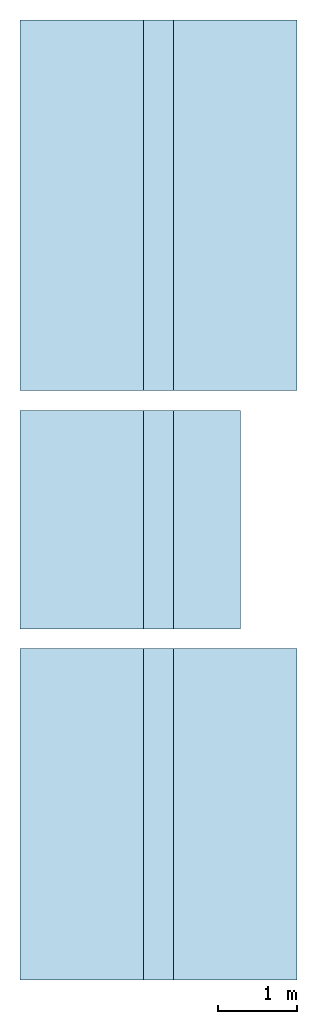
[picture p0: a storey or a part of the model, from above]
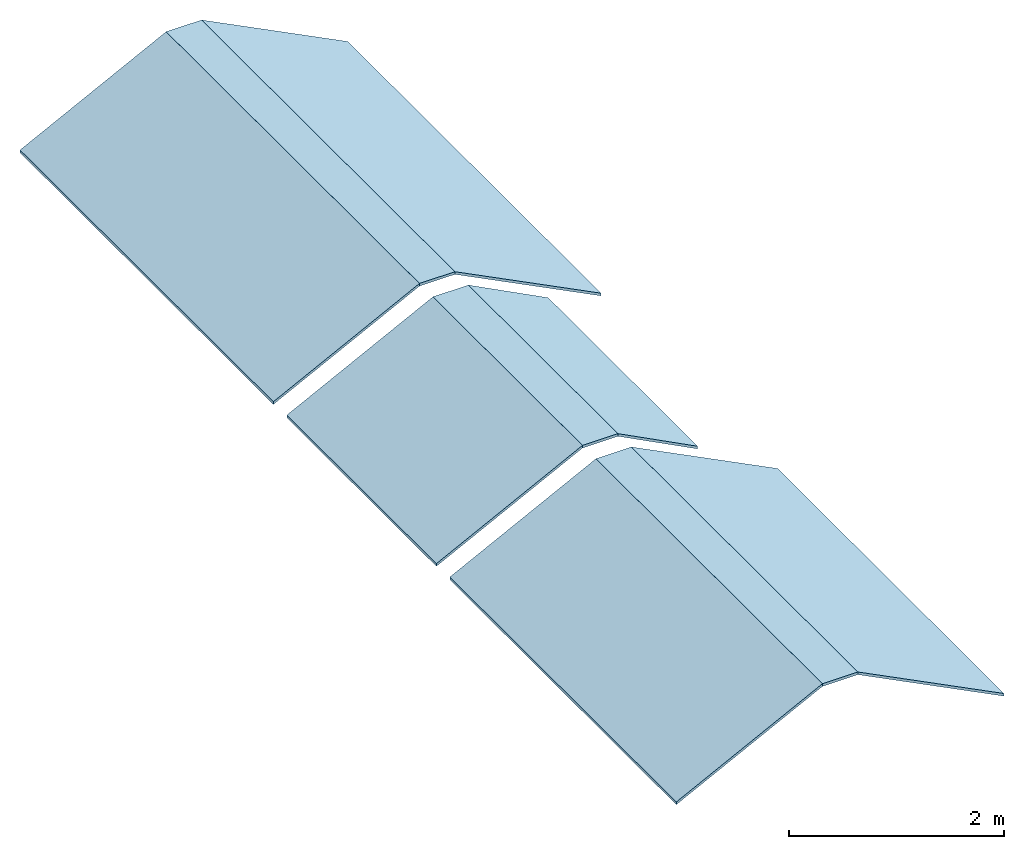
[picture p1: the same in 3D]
Properties of the parts of a building model (IFC2X3), part 1 of 5

# File
Description: ViewDefinition [CoordinationView_V2.0, QuantityTakeOffAddOnView], RevitIdentifiers [ContentGUID: d7be6c1a-651b-40f5-b81f-00204cea7fad, VersionGUID: a0f5081a-c94c-4963-9edc-757abe7cdd60, NumberOfSaves: 85], CoordinateReference [CoordinateBase: Gemeinsam genutzte Koordinaten, ProjectSite: Intern]
File name: Weber Haus.ifc
Time: 2025-12-15T00:05:59+01:00
Written by: ODA SDAI 24.12
Made in: Autodesk Revit 25.4.30.30 (DEU) - IFC 25.4.30.30

# IfcProject, 00-00
LongName: Scan2BIM - Beispiel Datei; Phase: Projekt Status

# IfcSite, Default
RefLatitude: 48, 8, 15, 359802; RefLongitude: 11, 34, 47, 783432; RefElevation: 0 m
Andere - Auftraggeber: Bauherr; Kategorie: Projektinformationen; Projektadresse: Projektadresse; Projektausgabedatum: Projekt Datum; Projektname: Scan2BIM - Beispiel Datei; Projektnummer: 00-00; Projektstatus: Projekt Status; Verfasser eMail: bjarne.weber@flyrender.de; Verfasser Firma 1: FlyRender; Verfasser PLZ Ort: 63928 Eichenbühl; Verfasser Strasse: Im Scheibling 19; Verfasser Telefon: +49 152 09980161; Verfasser URL: www.flyrender.de
Text - Bauherr: Dr. Thomas Weber; Baustellenort: Eichenbühl; Baustellenstraße: Im Scheibling 19; Einlagezahl: 123-45; Gerichtsbezirk: GERICHTSBEZIRK; Grundstücksnummer: GR; Katastralgemeinde: KG; Kundenadresse: KUNDENSTRASSE 1; Kundenort: KUNDENORT; Kundentelefon: 0000-00000-1; Kundenzusatz: KUNDENZUSATZ

# IfcBuilding
Pset_BuildingCommon - NumberOfStoreys: 4
Andere - Auftraggeber: Bauherr; Kategorie: Projektinformationen; Projektadresse: Projektadresse; Projektausgabedatum: Projekt Datum; Projektname: Scan2BIM - Beispiel Datei; Projektnummer: 00-00; Projektstatus: Projekt Status; Verfasser eMail: bjarne.weber@flyrender.de; Verfasser Firma 1: FlyRender; Verfasser PLZ Ort: 63928 Eichenbühl; Verfasser Strasse: Im Scheibling 19; Verfasser Telefon: +49 152 09980161; Verfasser URL: www.flyrender.de
Text - Bauherr: Dr. Thomas Weber; Baustellenort: Eichenbühl; Baustellenstraße: Im Scheibling 19; Einlagezahl: 123-45; Gerichtsbezirk: GERICHTSBEZIRK; Grundstücksnummer: GR; Katastralgemeinde: KG; Kundenadresse: KUNDENSTRASSE 1; Kundenort: KUNDENORT; Kundentelefon: 0000-00000-1; Kundenzusatz: KUNDENZUSATZ

# IfcBuildingStorey: Ebene:Ebene 2 (4)
Pset_AirSideSystemInformation - sets with these values: 2
00_EBENENLISTE - Tragwerk: no; Typ: Ebene 2; Gebäudegeschoss: yes
Andere - Familie: Ebene; Familie und Typ: Ebene: Ebene 2; Kategorie: Ebenen; Typ: Ebene 2; Typ-ID: 2017674
ID-Daten - Tragwerk: no; Gebäudegeschoss: yes
Andere(Typ) - Kategorie: Ebenen; Familienname: Ebene
Abhängigkeiten(Typ) - Basishöhe: Projekt-Basispunkt
Grafiken(Typ) - Farbe: 6579300; Linienmuster: (Referenzebene); Linienstärke: 2; Symbol: Beschriftung Ebene Oberkante : Rohbau; Symbol bei Ende 1 Standard: no; Symbol bei Ende 2 Standard: yes
ID-Daten(Typ) - Typname: Ebene 2
Name | LongName = Pset_AirSideSystemInformation, Name = 00_EBENENLISTE, Name = ID-Daten, Name | Elevation (m) = Ansicht (m) = Höhe (m) | Höhe für Berechnung (m)
Untergeschoss | Untergeschoss | 0 | 1 | Daten - FM Geschoss: EG
Erdgeschoss | Erdgeschoss | 2.6 | 1 | Daten - FM Geschoss: OG 1
1. Obergeschoss | 1. Obergeschoss | 5.4 | 0
First OK | First OK | 9.15 | 0

# IfcSpace: Abseite 1 18:2833431, 18
In: 1. Obergeschoss
LongName: Abseite 1; InteriorOrExteriorSpace: INTERNAL
Pset_AirSideSystemInformation - Name: Abseite 1; sets with these values: 2
Pset_SpaceCommon - Reference: Abseite 1 18
RÄUME - nach Tops und Flächenzuordnung - Nr: 18; Name: Abseite 1; sets with these values: 2
RÄUME - nach Ebene mit Fläche & Umfang - Ebene: 1. Obergeschoss; Nr: 18; Name: Abseite 1
BaseQuantities - GrossFloorArea: 6.17697 m2; NetFloorArea: 6.17697 m2; GrossCeilingArea: 6.17697 m2; Height: 2.4384 m
Andere - Kategorie: Räume; Phasen-ID: 3
Abhängigkeiten - Basisversatz: 0 m; Versatz Oberkante: 26.2467 m; Obergrenze: 1. Obergeschoss; Ebene: 1. Obergeschoss
Bemaßungen - Lichte Höhe: 26.2467 m; Höhe für Berechnung: 0 m; Fläche: 6.17697 m2; Umfang: 12.0429 m; Volumen: 7.10003 m3
Energieanalyse - Angegebene Beleuchtungslast: 0 W; Angegebene Versorgungsleistung: 0 W; Beleuchtungslast basieren auf: Nach Raumtyp; Beleuchtungslasteinheiten: Leistungsdichte; Heizlastwerte: Nach Raumtyp; Luftraum - Beitrag zu Beleuchtung: 0.2; Personenzahl: 0; Tatsächliche Beleuchtungslast: 0 W; Tatsächliche Versorgungsleistung: 0 W; Versorgungslasteinheiten: Leistungsdichte; Versorgungsleistung basieren auf: Nach Raumtyp; Angegebene Beleuchtungslast pro Fläche: 10.7639 kg/s3; Angegebene Versorgungsleistung pro Fläche: 13.9931 kg/s3; Fläche pro Person: 28.5714 m2; Latente Wärmelast pro Person: 58.6142 W; Tatsächliche Beleuchtungslast pro Fläche: 0 kg/s3; Tatsächliche Versorgungsleistung pro Fläche: 0 kg/s3; Wahrnehmbare Wärmelast pro Person: 73.2678 W; Wärmegewinn insgesamt pro Person: 131.882 W
ID-Daten - Name: Abseite 1; Nummer: 18
Phasen - Phase: Phase 01

# IfcSpace: Abseite 2 21:2833440, 21
In: 1. Obergeschoss
LongName: Abseite 2; InteriorOrExteriorSpace: INTERNAL
Pset_AirSideSystemInformation - Name: Abseite 2; sets with these values: 2
Pset_SpaceCommon - Reference: Abseite 2 21
RÄUME - nach Tops und Flächenzuordnung - Nr: 21; Name: Abseite 2; sets with these values: 2
RÄUME - nach Ebene mit Fläche & Umfang - Ebene: 1. Obergeschoss; Nr: 21; Name: Abseite 2
BaseQuantities - GrossFloorArea: 5.77079 m2; NetFloorArea: 5.77079 m2; GrossCeilingArea: 5.77079 m2; Height: 2.4384 m
Andere - Kategorie: Räume; Phasen-ID: 3
Abhängigkeiten - Basisversatz: 0 m; Versatz Oberkante: 26.2467 m; Obergrenze: 1. Obergeschoss; Ebene: 1. Obergeschoss
Bemaßungen - Lichte Höhe: 26.2467 m; Höhe für Berechnung: 0 m; Fläche: 5.77079 m2; Umfang: 11.1615 m; Volumen: 8.92186 m3
Energieanalyse - Angegebene Beleuchtungslast: 0 W; Angegebene Versorgungsleistung: 0 W; Beleuchtungslast basieren auf: Nach Raumtyp; Beleuchtungslasteinheiten: Leistungsdichte; Heizlastwerte: Nach Raumtyp; Luftraum - Beitrag zu Beleuchtung: 0.2; Personenzahl: 0; Tatsächliche Beleuchtungslast: 0 W; Tatsächliche Versorgungsleistung: 0 W; Versorgungslasteinheiten: Leistungsdichte; Versorgungsleistung basieren auf: Nach Raumtyp; Angegebene Beleuchtungslast pro Fläche: 10.7639 kg/s3; Angegebene Versorgungsleistung pro Fläche: 13.9931 kg/s3; Fläche pro Person: 28.5714 m2; Latente Wärmelast pro Person: 58.6142 W; Tatsächliche Beleuchtungslast pro Fläche: 0 kg/s3; Tatsächliche Versorgungsleistung pro Fläche: 0 kg/s3; Wahrnehmbare Wärmelast pro Person: 73.2678 W; Wärmegewinn insgesamt pro Person: 131.882 W
ID-Daten - Name: Abseite 2; Nummer: 21
Phasen - Phase: Phase 01

# IfcSpace: Arbeitszimmer 12:2832122, 12
In: Erdgeschoss
LongName: Arbeitszimmer; InteriorOrExteriorSpace: INTERNAL
Pset_AirSideSystemInformation - Name: Arbeitszimmer; sets with these values: 2
Pset_SpaceCommon - Reference: Arbeitszimmer 12
RÄUME - nach Tops und Flächenzuordnung - Nr: 12; Name: Arbeitszimmer; sets with these values: 2
RÄUME - nach Ebene mit Fläche & Umfang - Ebene: Erdgeschoss; Nr: 12; Name: Arbeitszimmer
BaseQuantities - GrossFloorArea: 14.6935 m2; NetFloorArea: 14.6935 m2; GrossCeilingArea: 14.6935 m2; Height: 2.4384 m
Andere - Kategorie: Räume; Phasen-ID: 3
Abhängigkeiten - Basisversatz: 0 m; Versatz Oberkante: 26.2467 m; Obergrenze: Erdgeschoss; Ebene: Erdgeschoss
Bemaßungen - Lichte Höhe: 26.2467 m; Fläche: 14.6935 m2; Höhe für Berechnung: 1 m; Umfang: 16.0728 m; Volumen: 35.8287 m3
Energieanalyse - Angegebene Beleuchtungslast: 0 W; Angegebene Versorgungsleistung: 0 W; Beleuchtungslast basieren auf: Nach Raumtyp; Beleuchtungslasteinheiten: Leistungsdichte; Heizlastwerte: Nach Raumtyp; Luftraum - Beitrag zu Beleuchtung: 0.2; Personenzahl: 0; Tatsächliche Beleuchtungslast: 0 W; Tatsächliche Versorgungsleistung: 0 W; Versorgungslasteinheiten: Leistungsdichte; Versorgungsleistung basieren auf: Nach Raumtyp; Angegebene Beleuchtungslast pro Fläche: 10.7639 kg/s3; Angegebene Versorgungsleistung pro Fläche: 13.9931 kg/s3; Fläche pro Person: 28.5714 m2; Latente Wärmelast pro Person: 58.6142 W; Tatsächliche Beleuchtungslast pro Fläche: 0 kg/s3; Tatsächliche Versorgungsleistung pro Fläche: 0 kg/s3; Wahrnehmbare Wärmelast pro Person: 73.2678 W; Wärmegewinn insgesamt pro Person: 131.882 W
ID-Daten - Name: Arbeitszimmer; Nummer: 12
Phasen - Phase: Phase 01

# IfcSpace: Bad 16:2832134, 16
In: Erdgeschoss
LongName: Bad; InteriorOrExteriorSpace: INTERNAL
Pset_AirSideSystemInformation - Name: Bad; sets with these values: 2
Pset_SpaceCommon - Reference: Bad 16
RÄUME - nach Tops und Flächenzuordnung - Nr: 16; Name: Bad; sets with these values: 2
RÄUME - nach Ebene mit Fläche & Umfang - Ebene: Erdgeschoss; Nr: 16; Name: Bad
BaseQuantities - GrossFloorArea: 5.03678 m2; NetFloorArea: 5.03678 m2; GrossCeilingArea: 5.03678 m2; Height: 2.4384 m
Andere - Kategorie: Räume; Phasen-ID: 3
Abhängigkeiten - Basisversatz: 0 m; Versatz Oberkante: 26.2467 m; Obergrenze: Erdgeschoss; Ebene: Erdgeschoss
Bemaßungen - Lichte Höhe: 26.2467 m; Fläche: 5.03678 m2; Höhe für Berechnung: 1 m; Umfang: 9.06593 m; Volumen: 12.2817 m3
Energieanalyse - Angegebene Beleuchtungslast: 0 W; Angegebene Versorgungsleistung: 0 W; Beleuchtungslast basieren auf: Nach Raumtyp; Beleuchtungslasteinheiten: Leistungsdichte; Heizlastwerte: Nach Raumtyp; Luftraum - Beitrag zu Beleuchtung: 0.2; Personenzahl: 0; Tatsächliche Beleuchtungslast: 0 W; Tatsächliche Versorgungsleistung: 0 W; Versorgungslasteinheiten: Leistungsdichte; Versorgungsleistung basieren auf: Nach Raumtyp; Angegebene Beleuchtungslast pro Fläche: 10.7639 kg/s3; Angegebene Versorgungsleistung pro Fläche: 13.9931 kg/s3; Fläche pro Person: 28.5714 m2; Latente Wärmelast pro Person: 58.6142 W; Tatsächliche Beleuchtungslast pro Fläche: 0 kg/s3; Tatsächliche Versorgungsleistung pro Fläche: 0 kg/s3; Wahrnehmbare Wärmelast pro Person: 73.2678 W; Wärmegewinn insgesamt pro Person: 131.882 W
ID-Daten - Name: Bad; Nummer: 16
Phasen - Phase: Phase 01

# IfcSpace: Bad 22:2833443, 22
In: 1. Obergeschoss
LongName: Bad; InteriorOrExteriorSpace: INTERNAL
Pset_AirSideSystemInformation - Name: Bad; sets with these values: 2
Pset_SpaceCommon - Reference: Bad 22
RÄUME - nach Tops und Flächenzuordnung - Nr: 22; Name: Bad; sets with these values: 2
RÄUME - nach Ebene mit Fläche & Umfang - Ebene: 1. Obergeschoss; Nr: 22; Name: Bad
BaseQuantities - GrossFloorArea: 5.27 m2; NetFloorArea: 5.27 m2; GrossCeilingArea: 5.27 m2; Height: 2.4384 m
Andere - Kategorie: Räume; Phasen-ID: 3
Abhängigkeiten - Basisversatz: 0 m; Versatz Oberkante: 26.2467 m; Obergrenze: 1. Obergeschoss; Ebene: 1. Obergeschoss
Bemaßungen - Lichte Höhe: 26.2467 m; Höhe für Berechnung: 0 m; Fläche: 5.27 m2; Umfang: 9.9 m; Volumen: 11.2929 m3
Energieanalyse - Angegebene Beleuchtungslast: 0 W; Angegebene Versorgungsleistung: 0 W; Beleuchtungslast basieren auf: Nach Raumtyp; Beleuchtungslasteinheiten: Leistungsdichte; Heizlastwerte: Nach Raumtyp; Luftraum - Beitrag zu Beleuchtung: 0.2; Personenzahl: 0; Tatsächliche Beleuchtungslast: 0 W; Tatsächliche Versorgungsleistung: 0 W; Versorgungslasteinheiten: Leistungsdichte; Versorgungsleistung basieren auf: Nach Raumtyp; Angegebene Beleuchtungslast pro Fläche: 10.7639 kg/s3; Angegebene Versorgungsleistung pro Fläche: 13.9931 kg/s3; Fläche pro Person: 28.5714 m2; Latente Wärmelast pro Person: 58.6142 W; Tatsächliche Beleuchtungslast pro Fläche: 0 kg/s3; Tatsächliche Versorgungsleistung pro Fläche: 0 kg/s3; Wahrnehmbare Wärmelast pro Person: 73.2678 W; Wärmegewinn insgesamt pro Person: 131.882 W
ID-Daten - Name: Bad; Nummer: 22
Phasen - Phase: Phase 01

# IfcSpace: Bad 7:2812981, 7
In: Untergeschoss
LongName: Bad; InteriorOrExteriorSpace: INTERNAL
Pset_AirSideSystemInformation - Name: Bad; sets with these values: 2
Pset_SpaceCommon - Reference: Bad 7
RÄUME - nach Tops und Flächenzuordnung - Nr: 7; Name: Bad; sets with these values: 2
RÄUME - nach Ebene mit Fläche & Umfang - Ebene: Untergeschoss; Nr: 7; Name: Bad
BaseQuantities - GrossFloorArea: 2.45626 m2; NetFloorArea: 2.45626 m2; GrossCeilingArea: 2.45626 m2; Height: 2.4384 m
Andere - Kategorie: Räume; Phasen-ID: 3
Abhängigkeiten - Basisversatz: 0 m; Obergrenze: Untergeschoss; Versatz Oberkante: 26.2467 m; Ebene: Untergeschoss
Bemaßungen - Lichte Höhe: 26.2467 m; Fläche: 2.45626 m2; Höhe für Berechnung: 1 m; Umfang: 6.66593 m; Volumen: 5.77221 m3
Energieanalyse - Angegebene Beleuchtungslast: 0 W; Angegebene Versorgungsleistung: 0 W; Beleuchtungslast basieren auf: Nach Raumtyp; Beleuchtungslasteinheiten: Leistungsdichte; Heizlastwerte: Nach Raumtyp; Luftraum - Beitrag zu Beleuchtung: 0.2; Personenzahl: 0; Tatsächliche Beleuchtungslast: 0 W; Tatsächliche Versorgungsleistung: 0 W; Versorgungslasteinheiten: Leistungsdichte; Versorgungsleistung basieren auf: Nach Raumtyp; Angegebene Beleuchtungslast pro Fläche: 10.7639 kg/s3; Angegebene Versorgungsleistung pro Fläche: 13.9931 kg/s3; Fläche pro Person: 28.5714 m2; Latente Wärmelast pro Person: 58.6142 W; Tatsächliche Beleuchtungslast pro Fläche: 0 kg/s3; Tatsächliche Versorgungsleistung pro Fläche: 0 kg/s3; Wahrnehmbare Wärmelast pro Person: 73.2678 W; Wärmegewinn insgesamt pro Person: 131.882 W
ID-Daten - Name: Bad; Nummer: 7
Phasen - Phase: Phase 01

# IfcSpace: Bibliothek 19:2833434, 19
In: 1. Obergeschoss
LongName: Bibliothek; InteriorOrExteriorSpace: INTERNAL
Pset_AirSideSystemInformation - Name: Bibliothek; sets with these values: 2
Pset_SpaceCommon - Reference: Bibliothek 19
RÄUME - nach Tops und Flächenzuordnung - Nr: 19; Name: Bibliothek; sets with these values: 2
RÄUME - nach Ebene mit Fläche & Umfang - Ebene: 1. Obergeschoss; Nr: 19; Name: Bibliothek
BaseQuantities - GrossFloorArea: 22.1961 m2; NetFloorArea: 22.1961 m2; GrossCeilingArea: 22.1961 m2; Height: 2.4384 m
Andere - Kategorie: Räume; Phasen-ID: 3
Abhängigkeiten - Basisversatz: 0 m; Versatz Oberkante: 26.2467 m; Obergrenze: 1. Obergeschoss; Ebene: 1. Obergeschoss
Bemaßungen - Lichte Höhe: 26.2467 m; Höhe für Berechnung: 0 m; Fläche: 22.1961 m2; Umfang: 26.1712 m; Volumen: 40.4515 m3
Energieanalyse - Angegebene Beleuchtungslast: 0 W; Angegebene Versorgungsleistung: 0 W; Beleuchtungslast basieren auf: Nach Raumtyp; Beleuchtungslasteinheiten: Leistungsdichte; Heizlastwerte: Nach Raumtyp; Luftraum - Beitrag zu Beleuchtung: 0.2; Personenzahl: 0; Tatsächliche Beleuchtungslast: 0 W; Tatsächliche Versorgungsleistung: 0 W; Versorgungslasteinheiten: Leistungsdichte; Versorgungsleistung basieren auf: Nach Raumtyp; Angegebene Beleuchtungslast pro Fläche: 10.7639 kg/s3; Angegebene Versorgungsleistung pro Fläche: 13.9931 kg/s3; Fläche pro Person: 28.5714 m2; Latente Wärmelast pro Person: 58.6142 W; Tatsächliche Beleuchtungslast pro Fläche: 0 kg/s3; Tatsächliche Versorgungsleistung pro Fläche: 0 kg/s3; Wahrnehmbare Wärmelast pro Person: 73.2678 W; Wärmegewinn insgesamt pro Person: 131.882 W
ID-Daten - Name: Bibliothek; Nummer: 19
Phasen - Phase: Phase 01

# IfcSpace: Billiardzimmer 5:2812975, 5
In: Untergeschoss
LongName: Billiardzimmer; InteriorOrExteriorSpace: INTERNAL
Pset_AirSideSystemInformation - Name: Billiardzimmer; sets with these values: 2
Pset_SpaceCommon - Reference: Billiardzimmer 5
RÄUME - nach Tops und Flächenzuordnung - Nr: 5; Name: Billiardzimmer; sets with these values: 2
RÄUME - nach Ebene mit Fläche & Umfang - Ebene: Untergeschoss; Nr: 5; Name: Billiardzimmer
BaseQuantities - GrossFloorArea: 38.6121 m2; NetFloorArea: 38.6121 m2; GrossCeilingArea: 38.6121 m2; Height: 2.4384 m
Andere - Kategorie: Räume; Phasen-ID: 3
Abhängigkeiten - Basisversatz: 0 m; Obergrenze: Untergeschoss; Versatz Oberkante: 26.2467 m; Ebene: Untergeschoss
Bemaßungen - Lichte Höhe: 26.2467 m; Fläche: 38.6121 m2; Höhe für Berechnung: 1 m; Umfang: 28.9258 m; Volumen: 90.7385 m3
Energieanalyse - Angegebene Beleuchtungslast: 0 W; Angegebene Versorgungsleistung: 0 W; Beleuchtungslast basieren auf: Nach Raumtyp; Beleuchtungslasteinheiten: Leistungsdichte; Heizlastwerte: Nach Raumtyp; Luftraum - Beitrag zu Beleuchtung: 0.2; Personenzahl: 0; Tatsächliche Beleuchtungslast: 0 W; Tatsächliche Versorgungsleistung: 0 W; Versorgungslasteinheiten: Leistungsdichte; Versorgungsleistung basieren auf: Nach Raumtyp; Angegebene Beleuchtungslast pro Fläche: 10.7639 kg/s3; Angegebene Versorgungsleistung pro Fläche: 13.9931 kg/s3; Fläche pro Person: 28.5714 m2; Latente Wärmelast pro Person: 58.6142 W; Tatsächliche Beleuchtungslast pro Fläche: 0 kg/s3; Tatsächliche Versorgungsleistung pro Fläche: 0 kg/s3; Wahrnehmbare Wärmelast pro Person: 73.2678 W; Wärmegewinn insgesamt pro Person: 131.882 W
ID-Daten - Name: Billiardzimmer; Nummer: 5
Phasen - Phase: Phase 01

# IfcSpace: Diele 11:2832119, 11
In: Erdgeschoss
LongName: Diele; InteriorOrExteriorSpace: INTERNAL
Pset_AirSideSystemInformation - Name: Diele; sets with these values: 2
Pset_SpaceCommon - Reference: Diele 11
RÄUME - nach Tops und Flächenzuordnung - Nr: 11; Name: Diele; sets with these values: 2
RÄUME - nach Ebene mit Fläche & Umfang - Ebene: Erdgeschoss; Nr: 11; Name: Diele
BaseQuantities - GrossFloorArea: 10.7251 m2; NetFloorArea: 10.7251 m2; GrossCeilingArea: 10.7251 m2; Height: 2.4384 m
Andere - Kategorie: Räume; Phasen-ID: 3
Abhängigkeiten - Basisversatz: 0 m; Versatz Oberkante: 26.2467 m; Obergrenze: Erdgeschoss; Ebene: Erdgeschoss
Bemaßungen - Lichte Höhe: 26.2467 m; Fläche: 10.7251 m2; Höhe für Berechnung: 1 m; Umfang: 13.2759 m; Volumen: 26.0136 m3
Energieanalyse - Angegebene Beleuchtungslast: 0 W; Angegebene Versorgungsleistung: 0 W; Beleuchtungslast basieren auf: Nach Raumtyp; Beleuchtungslasteinheiten: Leistungsdichte; Heizlastwerte: Nach Raumtyp; Luftraum - Beitrag zu Beleuchtung: 0.2; Personenzahl: 0; Tatsächliche Beleuchtungslast: 0 W; Tatsächliche Versorgungsleistung: 0 W; Versorgungslasteinheiten: Leistungsdichte; Versorgungsleistung basieren auf: Nach Raumtyp; Angegebene Beleuchtungslast pro Fläche: 10.7639 kg/s3; Angegebene Versorgungsleistung pro Fläche: 13.9931 kg/s3; Fläche pro Person: 28.5714 m2; Latente Wärmelast pro Person: 58.6142 W; Tatsächliche Beleuchtungslast pro Fläche: 0 kg/s3; Tatsächliche Versorgungsleistung pro Fläche: 0 kg/s3; Wahrnehmbare Wärmelast pro Person: 73.2678 W; Wärmegewinn insgesamt pro Person: 131.882 W
ID-Daten - Name: Diele; Nummer: 11
Phasen - Phase: Phase 01

# IfcSpace: Flur 1 4:2812972, 4
In: Untergeschoss
LongName: Flur 1; InteriorOrExteriorSpace: INTERNAL
Pset_AirSideSystemInformation - Name: Flur 1; sets with these values: 2
Pset_SpaceCommon - Reference: Flur 1 4
RÄUME - nach Tops und Flächenzuordnung - Nr: 4; Name: Flur 1; sets with these values: 2
RÄUME - nach Ebene mit Fläche & Umfang - Ebene: Untergeschoss; Nr: 4; Name: Flur 1
BaseQuantities - GrossFloorArea: 3.8512 m2; NetFloorArea: 3.8512 m2; GrossCeilingArea: 3.8512 m2; Height: 2.4384 m
Andere - Kategorie: Räume; Phasen-ID: 3
Abhängigkeiten - Basisversatz: 0 m; Obergrenze: Untergeschoss; Versatz Oberkante: 26.2467 m; Ebene: Untergeschoss
Bemaßungen - Lichte Höhe: 26.2467 m; Fläche: 3.8512 m2; Höhe für Berechnung: 1 m; Umfang: 9.56 m; Volumen: 9.05032 m3
Energieanalyse - Angegebene Beleuchtungslast: 0 W; Angegebene Versorgungsleistung: 0 W; Beleuchtungslast basieren auf: Nach Raumtyp; Beleuchtungslasteinheiten: Leistungsdichte; Heizlastwerte: Nach Raumtyp; Luftraum - Beitrag zu Beleuchtung: 0.2; Personenzahl: 0; Tatsächliche Beleuchtungslast: 0 W; Tatsächliche Versorgungsleistung: 0 W; Versorgungslasteinheiten: Leistungsdichte; Versorgungsleistung basieren auf: Nach Raumtyp; Angegebene Beleuchtungslast pro Fläche: 10.7639 kg/s3; Angegebene Versorgungsleistung pro Fläche: 13.9931 kg/s3; Fläche pro Person: 28.5714 m2; Latente Wärmelast pro Person: 58.6142 W; Tatsächliche Beleuchtungslast pro Fläche: 0 kg/s3; Tatsächliche Versorgungsleistung pro Fläche: 0 kg/s3; Wahrnehmbare Wärmelast pro Person: 73.2678 W; Wärmegewinn insgesamt pro Person: 131.882 W
ID-Daten - Name: Flur 1; Nummer: 4
Phasen - Phase: Phase 01

# IfcSpace: Flur 15:2832131, 15
In: Erdgeschoss
LongName: Flur; InteriorOrExteriorSpace: INTERNAL
Pset_AirSideSystemInformation - Name: Flur; sets with these values: 2
Pset_SpaceCommon - Reference: Flur 15
RÄUME - nach Tops und Flächenzuordnung - Nr: 15; Name: Flur; sets with these values: 2
RÄUME - nach Ebene mit Fläche & Umfang - Ebene: Erdgeschoss; Nr: 15; Name: Flur
BaseQuantities - GrossFloorArea: 2.09625 m2; NetFloorArea: 2.09625 m2; GrossCeilingArea: 2.09625 m2; Height: 2.4384 m
Andere - Kategorie: Räume; Phasen-ID: 3
Abhängigkeiten - Basisversatz: 0 m; Versatz Oberkante: 26.2467 m; Obergrenze: Erdgeschoss; Ebene: Erdgeschoss
Bemaßungen - Lichte Höhe: 26.2467 m; Fläche: 2.09625 m2; Höhe für Berechnung: 1 m; Umfang: 6.05 m; Volumen: 5.1115 m3
Energieanalyse - Angegebene Beleuchtungslast: 0 W; Angegebene Versorgungsleistung: 0 W; Beleuchtungslast basieren auf: Nach Raumtyp; Beleuchtungslasteinheiten: Leistungsdichte; Heizlastwerte: Nach Raumtyp; Luftraum - Beitrag zu Beleuchtung: 0.2; Personenzahl: 0; Tatsächliche Beleuchtungslast: 0 W; Tatsächliche Versorgungsleistung: 0 W; Versorgungslasteinheiten: Leistungsdichte; Versorgungsleistung basieren auf: Nach Raumtyp; Angegebene Beleuchtungslast pro Fläche: 10.7639 kg/s3; Angegebene Versorgungsleistung pro Fläche: 13.9931 kg/s3; Fläche pro Person: 28.5714 m2; Latente Wärmelast pro Person: 58.6142 W; Tatsächliche Beleuchtungslast pro Fläche: 0 kg/s3; Tatsächliche Versorgungsleistung pro Fläche: 0 kg/s3; Wahrnehmbare Wärmelast pro Person: 73.2678 W; Wärmegewinn insgesamt pro Person: 131.882 W
ID-Daten - Name: Flur; Nummer: 15
Phasen - Phase: Phase 01

# IfcSpace: Flur 2 8:2812984, 8
In: Untergeschoss
LongName: Flur 2; InteriorOrExteriorSpace: INTERNAL
Pset_AirSideSystemInformation - Name: Flur 2; sets with these values: 2
Pset_SpaceCommon - Reference: Flur 2 8
RÄUME - nach Tops und Flächenzuordnung - Nr: 8; Name: Flur 2; sets with these values: 2
RÄUME - nach Ebene mit Fläche & Umfang - Ebene: Untergeschoss; Nr: 8; Name: Flur 2
BaseQuantities - GrossFloorArea: 10.4721 m2; NetFloorArea: 10.4483 m2; GrossCeilingArea: 10.4721 m2; Height: 2.4384 m
Andere - Kategorie: Räume; Phasen-ID: 3
Abhängigkeiten - Basisversatz: 0 m; Obergrenze: Untergeschoss; Versatz Oberkante: 26.2467 m; Ebene: Untergeschoss
Bemaßungen - Lichte Höhe: 26.2467 m; Fläche: 10.4483 m2; Höhe für Berechnung: 1 m; Umfang: 13.8029 m; Volumen: 24.7864 m3
Energieanalyse - Angegebene Beleuchtungslast: 0 W; Angegebene Versorgungsleistung: 0 W; Beleuchtungslast basieren auf: Nach Raumtyp; Beleuchtungslasteinheiten: Leistungsdichte; Heizlastwerte: Nach Raumtyp; Luftraum - Beitrag zu Beleuchtung: 0.2; Personenzahl: 0; Tatsächliche Beleuchtungslast: 0 W; Tatsächliche Versorgungsleistung: 0 W; Versorgungslasteinheiten: Leistungsdichte; Versorgungsleistung basieren auf: Nach Raumtyp; Angegebene Beleuchtungslast pro Fläche: 10.7639 kg/s3; Angegebene Versorgungsleistung pro Fläche: 13.9931 kg/s3; Fläche pro Person: 28.5714 m2; Latente Wärmelast pro Person: 58.6142 W; Tatsächliche Beleuchtungslast pro Fläche: 0 kg/s3; Tatsächliche Versorgungsleistung pro Fläche: 0 kg/s3; Wahrnehmbare Wärmelast pro Person: 73.2678 W; Wärmegewinn insgesamt pro Person: 131.882 W
ID-Daten - Name: Flur 2; Nummer: 8
Phasen - Phase: Phase 01

# IfcSpace: Gästezimmer 1:2812963, 1
In: Untergeschoss
LongName: Gästezimmer; InteriorOrExteriorSpace: INTERNAL
Pset_AirSideSystemInformation - Name: Gästezimmer; sets with these values: 2
Pset_SpaceCommon - Reference: Gästezimmer 1
RÄUME - nach Tops und Flächenzuordnung - Nr: 1; Name: Gästezimmer; sets with these values: 2
RÄUME - nach Ebene mit Fläche & Umfang - Ebene: Untergeschoss; Nr: 1; Name: Gästezimmer
BaseQuantities - GrossFloorArea: 13.3279 m2; NetFloorArea: 13.3279 m2; GrossCeilingArea: 13.3279 m2; Height: 2.4384 m
Andere - Kategorie: Räume; Phasen-ID: 3
Abhängigkeiten - Basisversatz: 0 m; Ebene: Untergeschoss; Obergrenze: Untergeschoss; Versatz Oberkante: 26.2467 m
Bemaßungen - Fläche: 13.3279 m2; Höhe für Berechnung: 1 m; Lichte Höhe: 26.2467 m; Umfang: 14.6341 m; Volumen: 31.3205 m3
Energieanalyse - Angegebene Beleuchtungslast: 0 W; Angegebene Beleuchtungslast pro Fläche: 10.7639 kg/s3; Angegebene Versorgungsleistung: 0 W; Angegebene Versorgungsleistung pro Fläche: 13.9931 kg/s3; Beleuchtungslast basieren auf: Nach Raumtyp; Beleuchtungslasteinheiten: Leistungsdichte; Fläche pro Person: 28.5714 m2; Heizlastwerte: Nach Raumtyp; Latente Wärmelast pro Person: 58.6142 W; Luftraum - Beitrag zu Beleuchtung: 0.2; Personenzahl: 0; Tatsächliche Beleuchtungslast: 0 W; Tatsächliche Beleuchtungslast pro Fläche: 0 kg/s3; Tatsächliche Versorgungsleistung: 0 W; Tatsächliche Versorgungsleistung pro Fläche: 0 kg/s3; Versorgungslasteinheiten: Leistungsdichte; Versorgungsleistung basieren auf: Nach Raumtyp; Wahrnehmbare Wärmelast pro Person: 73.2678 W; Wärmegewinn insgesamt pro Person: 131.882 W
ID-Daten - Name: Gästezimmer; Nummer: 1
Phasen - Phase: Phase 01

# IfcSpace: Kinderzimmer 1 17:2833427, 17
In: 1. Obergeschoss
LongName: Kinderzimmer 1; InteriorOrExteriorSpace: INTERNAL
Pset_AirSideSystemInformation - Name: Kinderzimmer 1; sets with these values: 2
Pset_SpaceCommon - Reference: Kinderzimmer 1 17
RÄUME - nach Tops und Flächenzuordnung - Nr: 17; Name: Kinderzimmer 1; sets with these values: 2
RÄUME - nach Ebene mit Fläche & Umfang - Ebene: 1. Obergeschoss; Nr: 17; Name: Kinderzimmer 1
BaseQuantities - GrossFloorArea: 24.6849 m2; NetFloorArea: 24.6849 m2; GrossCeilingArea: 24.6849 m2; Height: 2.4384 m
Andere - Kategorie: Räume; Phasen-ID: 3
Abhängigkeiten - Basisversatz: 0 m; Versatz Oberkante: 26.2467 m; Ebene: 1. Obergeschoss; Obergrenze: 1. Obergeschoss
Bemaßungen - Lichte Höhe: 26.2467 m; Fläche: 24.6849 m2; Höhe für Berechnung: 0 m; Umfang: 22.5771 m; Volumen: 53.802 m3
Energieanalyse - Angegebene Beleuchtungslast: 0 W; Angegebene Versorgungsleistung: 0 W; Beleuchtungslast basieren auf: Nach Raumtyp; Beleuchtungslasteinheiten: Leistungsdichte; Heizlastwerte: Nach Raumtyp; Luftraum - Beitrag zu Beleuchtung: 0.2; Personenzahl: 0; Tatsächliche Beleuchtungslast: 0 W; Tatsächliche Versorgungsleistung: 0 W; Versorgungslasteinheiten: Leistungsdichte; Versorgungsleistung basieren auf: Nach Raumtyp; Angegebene Beleuchtungslast pro Fläche: 10.7639 kg/s3; Angegebene Versorgungsleistung pro Fläche: 13.9931 kg/s3; Fläche pro Person: 28.5714 m2; Latente Wärmelast pro Person: 58.6142 W; Tatsächliche Beleuchtungslast pro Fläche: 0 kg/s3; Tatsächliche Versorgungsleistung pro Fläche: 0 kg/s3; Wahrnehmbare Wärmelast pro Person: 73.2678 W; Wärmegewinn insgesamt pro Person: 131.882 W
ID-Daten - Name: Kinderzimmer 1; Nummer: 17
Phasen - Phase: Phase 01

# IfcSpace: Kinderzimmer 2 20:2833437, 20
In: 1. Obergeschoss
LongName: Kinderzimmer 2; InteriorOrExteriorSpace: INTERNAL
Pset_AirSideSystemInformation - Name: Kinderzimmer 2; sets with these values: 2
Pset_SpaceCommon - Reference: Kinderzimmer 2 20
RÄUME - nach Tops und Flächenzuordnung - Nr: 20; Name: Kinderzimmer 2; sets with these values: 2
RÄUME - nach Ebene mit Fläche & Umfang - Ebene: 1. Obergeschoss; Nr: 20; Name: Kinderzimmer 2
BaseQuantities - GrossFloorArea: 29.2271 m2; NetFloorArea: 29.2271 m2; GrossCeilingArea: 29.2271 m2; Height: 2.4384 m
Andere - Kategorie: Räume; Phasen-ID: 3
Abhängigkeiten - Basisversatz: 0 m; Versatz Oberkante: 26.2467 m; Obergrenze: 1. Obergeschoss; Ebene: 1. Obergeschoss
Bemaßungen - Lichte Höhe: 26.2467 m; Höhe für Berechnung: 0 m; Fläche: 29.2271 m2; Umfang: 22.3046 m; Volumen: 61.4922 m3
Energieanalyse - Angegebene Beleuchtungslast: 0 W; Angegebene Versorgungsleistung: 0 W; Beleuchtungslast basieren auf: Nach Raumtyp; Beleuchtungslasteinheiten: Leistungsdichte; Heizlastwerte: Nach Raumtyp; Luftraum - Beitrag zu Beleuchtung: 0.2; Personenzahl: 0; Tatsächliche Beleuchtungslast: 0 W; Tatsächliche Versorgungsleistung: 0 W; Versorgungslasteinheiten: Leistungsdichte; Versorgungsleistung basieren auf: Nach Raumtyp; Angegebene Beleuchtungslast pro Fläche: 10.7639 kg/s3; Angegebene Versorgungsleistung pro Fläche: 13.9931 kg/s3; Fläche pro Person: 28.5714 m2; Latente Wärmelast pro Person: 58.6142 W; Tatsächliche Beleuchtungslast pro Fläche: 0 kg/s3; Tatsächliche Versorgungsleistung pro Fläche: 0 kg/s3; Wahrnehmbare Wärmelast pro Person: 73.2678 W; Wärmegewinn insgesamt pro Person: 131.882 W
ID-Daten - Name: Kinderzimmer 2; Nummer: 20
Phasen - Phase: Phase 01

# IfcSpace: Küche 10:2832116, 10
In: Erdgeschoss
LongName: Küche; InteriorOrExteriorSpace: INTERNAL
Pset_AirSideSystemInformation - Name: Küche; sets with these values: 2
Pset_SpaceCommon - Reference: Küche 10
RÄUME - nach Tops und Flächenzuordnung - Nr: 10; Name: Küche; sets with these values: 2
RÄUME - nach Ebene mit Fläche & Umfang - Ebene: Erdgeschoss; Nr: 10; Name: Küche
BaseQuantities - GrossFloorArea: 10.0323 m2; NetFloorArea: 10.0323 m2; GrossCeilingArea: 10.0323 m2; Height: 2.4384 m
Andere - Kategorie: Räume; Phasen-ID: 3
Abhängigkeiten - Basisversatz: 0 m; Versatz Oberkante: 26.2467 m; Obergrenze: Erdgeschoss; Ebene: Erdgeschoss
Bemaßungen - Lichte Höhe: 26.2467 m; Fläche: 10.0323 m2; Höhe für Berechnung: 1 m; Umfang: 13.1859 m; Volumen: 24.4627 m3
Energieanalyse - Angegebene Beleuchtungslast: 0 W; Angegebene Versorgungsleistung: 0 W; Beleuchtungslast basieren auf: Nach Raumtyp; Beleuchtungslasteinheiten: Leistungsdichte; Heizlastwerte: Nach Raumtyp; Luftraum - Beitrag zu Beleuchtung: 0.2; Personenzahl: 0; Tatsächliche Beleuchtungslast: 0 W; Tatsächliche Versorgungsleistung: 0 W; Versorgungslasteinheiten: Leistungsdichte; Versorgungsleistung basieren auf: Nach Raumtyp; Angegebene Beleuchtungslast pro Fläche: 10.7639 kg/s3; Angegebene Versorgungsleistung pro Fläche: 13.9931 kg/s3; Fläche pro Person: 28.5714 m2; Latente Wärmelast pro Person: 58.6142 W; Tatsächliche Beleuchtungslast pro Fläche: 0 kg/s3; Tatsächliche Versorgungsleistung pro Fläche: 0 kg/s3; Wahrnehmbare Wärmelast pro Person: 73.2678 W; Wärmegewinn insgesamt pro Person: 131.882 W
ID-Daten - Name: Küche; Nummer: 10
Phasen - Phase: Phase 01

# IfcSpace: Sauna 3:2812969, 3
In: Untergeschoss
LongName: Sauna; InteriorOrExteriorSpace: INTERNAL
Pset_AirSideSystemInformation - Name: Sauna; sets with these values: 2
Pset_SpaceCommon - Reference: Sauna 3
RÄUME - nach Tops und Flächenzuordnung - Nr: 3; Name: Sauna; sets with these values: 2
RÄUME - nach Ebene mit Fläche & Umfang - Ebene: Untergeschoss; Nr: 3; Name: Sauna
BaseQuantities - GrossFloorArea: 4.86593 m2; NetFloorArea: 4.86593 m2; GrossCeilingArea: 4.86593 m2; Height: 2.4384 m
Andere - Kategorie: Räume; Phasen-ID: 3
Abhängigkeiten - Basisversatz: 0 m; Obergrenze: Untergeschoss; Versatz Oberkante: 26.2467 m; Ebene: Untergeschoss
Bemaßungen - Lichte Höhe: 26.2467 m; Fläche: 4.86593 m2; Höhe für Berechnung: 1 m; Umfang: 8.86593 m; Volumen: 11.4349 m3
Energieanalyse - Angegebene Beleuchtungslast: 0 W; Angegebene Versorgungsleistung: 0 W; Beleuchtungslast basieren auf: Nach Raumtyp; Beleuchtungslasteinheiten: Leistungsdichte; Heizlastwerte: Nach Raumtyp; Luftraum - Beitrag zu Beleuchtung: 0.2; Personenzahl: 0; Tatsächliche Beleuchtungslast: 0 W; Tatsächliche Versorgungsleistung: 0 W; Versorgungslasteinheiten: Leistungsdichte; Versorgungsleistung basieren auf: Nach Raumtyp; Angegebene Beleuchtungslast pro Fläche: 10.7639 kg/s3; Angegebene Versorgungsleistung pro Fläche: 13.9931 kg/s3; Fläche pro Person: 28.5714 m2; Latente Wärmelast pro Person: 58.6142 W; Tatsächliche Beleuchtungslast pro Fläche: 0 kg/s3; Tatsächliche Versorgungsleistung pro Fläche: 0 kg/s3; Wahrnehmbare Wärmelast pro Person: 73.2678 W; Wärmegewinn insgesamt pro Person: 131.882 W
ID-Daten - Name: Sauna; Nummer: 3
Phasen - Phase: Phase 01

# IfcSpace: Schlafzimmer 1 13:2832125, 13
In: Erdgeschoss
LongName: Schlafzimmer 1; InteriorOrExteriorSpace: INTERNAL
Pset_AirSideSystemInformation - Name: Schlafzimmer 1; sets with these values: 2
Pset_SpaceCommon - Reference: Schlafzimmer 1 13
RÄUME - nach Tops und Flächenzuordnung - Nr: 13; Name: Schlafzimmer 1; sets with these values: 2
RÄUME - nach Ebene mit Fläche & Umfang - Ebene: Erdgeschoss; Nr: 13; Name: Schlafzimmer 1
BaseQuantities - GrossFloorArea: 15.977 m2; NetFloorArea: 15.977 m2; GrossCeilingArea: 15.977 m2; Height: 2.4384 m
Andere - Kategorie: Räume; Phasen-ID: 3
Abhängigkeiten - Basisversatz: 0 m; Versatz Oberkante: 26.2467 m; Obergrenze: Erdgeschoss; Ebene: Erdgeschoss
Bemaßungen - Lichte Höhe: 26.2467 m; Fläche: 15.977 m2; Höhe für Berechnung: 1 m; Umfang: 16.4153 m; Volumen: 38.9583 m3
Energieanalyse - Angegebene Beleuchtungslast: 0 W; Angegebene Versorgungsleistung: 0 W; Beleuchtungslast basieren auf: Nach Raumtyp; Beleuchtungslasteinheiten: Leistungsdichte; Heizlastwerte: Nach Raumtyp; Luftraum - Beitrag zu Beleuchtung: 0.2; Personenzahl: 0; Tatsächliche Beleuchtungslast: 0 W; Tatsächliche Versorgungsleistung: 0 W; Versorgungslasteinheiten: Leistungsdichte; Versorgungsleistung basieren auf: Nach Raumtyp; Angegebene Beleuchtungslast pro Fläche: 10.7639 kg/s3; Angegebene Versorgungsleistung pro Fläche: 13.9931 kg/s3; Fläche pro Person: 28.5714 m2; Latente Wärmelast pro Person: 58.6142 W; Tatsächliche Beleuchtungslast pro Fläche: 0 kg/s3; Tatsächliche Versorgungsleistung pro Fläche: 0 kg/s3; Wahrnehmbare Wärmelast pro Person: 73.2678 W; Wärmegewinn insgesamt pro Person: 131.882 W
ID-Daten - Name: Schlafzimmer 1; Nummer: 13
Phasen - Phase: Phase 01

# IfcSpace: Schlafzimmer 2 14:2832128, 14
In: Erdgeschoss
LongName: Schlafzimmer 2; InteriorOrExteriorSpace: INTERNAL
Pset_AirSideSystemInformation - Name: Schlafzimmer 2; sets with these values: 2
Pset_SpaceCommon - Reference: Schlafzimmer 2 14
RÄUME - nach Tops und Flächenzuordnung - Nr: 14; Name: Schlafzimmer 2; sets with these values: 2
RÄUME - nach Ebene mit Fläche & Umfang - Ebene: Erdgeschoss; Nr: 14; Name: Schlafzimmer 2
BaseQuantities - GrossFloorArea: 9.87639 m2; NetFloorArea: 9.87639 m2; GrossCeilingArea: 9.87639 m2; Height: 2.4384 m
Andere - Kategorie: Räume; Phasen-ID: 3
Abhängigkeiten - Basisversatz: 0 m; Versatz Oberkante: 26.2467 m; Obergrenze: Erdgeschoss; Ebene: Erdgeschoss
Bemaßungen - Lichte Höhe: 26.2467 m; Fläche: 9.87639 m2; Höhe für Berechnung: 1 m; Umfang: 12.8359 m; Volumen: 24.0826 m3
Energieanalyse - Angegebene Beleuchtungslast: 0 W; Angegebene Versorgungsleistung: 0 W; Beleuchtungslast basieren auf: Nach Raumtyp; Beleuchtungslasteinheiten: Leistungsdichte; Heizlastwerte: Nach Raumtyp; Luftraum - Beitrag zu Beleuchtung: 0.2; Personenzahl: 0; Tatsächliche Beleuchtungslast: 0 W; Tatsächliche Versorgungsleistung: 0 W; Versorgungslasteinheiten: Leistungsdichte; Versorgungsleistung basieren auf: Nach Raumtyp; Angegebene Beleuchtungslast pro Fläche: 10.7639 kg/s3; Angegebene Versorgungsleistung pro Fläche: 13.9931 kg/s3; Fläche pro Person: 28.5714 m2; Latente Wärmelast pro Person: 58.6142 W; Tatsächliche Beleuchtungslast pro Fläche: 0 kg/s3; Tatsächliche Versorgungsleistung pro Fläche: 0 kg/s3; Wahrnehmbare Wärmelast pro Person: 73.2678 W; Wärmegewinn insgesamt pro Person: 131.882 W
ID-Daten - Name: Schlafzimmer 2; Nummer: 14
Phasen - Phase: Phase 01

# IfcSpace: Technikraum 6:2812978, 6
In: Untergeschoss
LongName: Technikraum; InteriorOrExteriorSpace: INTERNAL
Pset_AirSideSystemInformation - Name: Technikraum; sets with these values: 2
Pset_SpaceCommon - Reference: Technikraum 6
RÄUME - nach Tops und Flächenzuordnung - Nr: 6; Name: Technikraum; sets with these values: 2
RÄUME - nach Ebene mit Fläche & Umfang - Ebene: Untergeschoss; Nr: 6; Name: Technikraum
BaseQuantities - GrossFloorArea: 16.3753 m2; NetFloorArea: 16.3753 m2; GrossCeilingArea: 16.3753 m2; Height: 2.4384 m
Andere - Kategorie: Räume; Phasen-ID: 3
Abhängigkeiten - Basisversatz: 0 m; Obergrenze: Untergeschoss; Versatz Oberkante: 26.2467 m; Ebene: Untergeschoss
Bemaßungen - Lichte Höhe: 26.2467 m; Fläche: 16.3753 m2; Höhe für Berechnung: 1 m; Umfang: 22.2983 m; Volumen: 38.482 m3
Energieanalyse - Angegebene Beleuchtungslast: 0 W; Angegebene Versorgungsleistung: 0 W; Beleuchtungslast basieren auf: Nach Raumtyp; Beleuchtungslasteinheiten: Leistungsdichte; Heizlastwerte: Nach Raumtyp; Luftraum - Beitrag zu Beleuchtung: 0.2; Personenzahl: 0; Tatsächliche Beleuchtungslast: 0 W; Tatsächliche Versorgungsleistung: 0 W; Versorgungslasteinheiten: Leistungsdichte; Versorgungsleistung basieren auf: Nach Raumtyp; Angegebene Beleuchtungslast pro Fläche: 10.7639 kg/s3; Angegebene Versorgungsleistung pro Fläche: 13.9931 kg/s3; Fläche pro Person: 28.5714 m2; Latente Wärmelast pro Person: 58.6142 W; Tatsächliche Beleuchtungslast pro Fläche: 0 kg/s3; Tatsächliche Versorgungsleistung pro Fläche: 0 kg/s3; Wahrnehmbare Wärmelast pro Person: 73.2678 W; Wärmegewinn insgesamt pro Person: 131.882 W
ID-Daten - Name: Technikraum; Nummer: 6
Phasen - Phase: Phase 01

# IfcSpace: Vorratskeller 2:2812966, 2
In: Untergeschoss
LongName: Vorratskeller; InteriorOrExteriorSpace: INTERNAL
Pset_AirSideSystemInformation - Name: Vorratskeller; sets with these values: 2
Pset_SpaceCommon - Reference: Vorratskeller 2
RÄUME - nach Tops und Flächenzuordnung - Nr: 2; Name: Vorratskeller; sets with these values: 2
RÄUME - nach Ebene mit Fläche & Umfang - Ebene: Untergeschoss; Nr: 2; Name: Vorratskeller
BaseQuantities - GrossFloorArea: 8.33079 m2; NetFloorArea: 8.33079 m2; GrossCeilingArea: 8.33079 m2; Height: 2.4384 m
Andere - Kategorie: Räume; Phasen-ID: 3
Abhängigkeiten - Basisversatz: 0 m; Obergrenze: Untergeschoss; Versatz Oberkante: 26.2467 m; Ebene: Untergeschoss
Bemaßungen - Lichte Höhe: 26.2467 m; Fläche: 8.33079 m2; Höhe für Berechnung: 1 m; Umfang: 12.9059 m; Volumen: 19.5774 m3
Energieanalyse - Angegebene Beleuchtungslast: 0 W; Angegebene Versorgungsleistung: 0 W; Beleuchtungslast basieren auf: Nach Raumtyp; Beleuchtungslasteinheiten: Leistungsdichte; Heizlastwerte: Nach Raumtyp; Luftraum - Beitrag zu Beleuchtung: 0.2; Personenzahl: 0; Tatsächliche Beleuchtungslast: 0 W; Tatsächliche Versorgungsleistung: 0 W; Versorgungslasteinheiten: Leistungsdichte; Versorgungsleistung basieren auf: Nach Raumtyp; Angegebene Beleuchtungslast pro Fläche: 10.7639 kg/s3; Angegebene Versorgungsleistung pro Fläche: 13.9931 kg/s3; Fläche pro Person: 28.5714 m2; Latente Wärmelast pro Person: 58.6142 W; Tatsächliche Beleuchtungslast pro Fläche: 0 kg/s3; Tatsächliche Versorgungsleistung pro Fläche: 0 kg/s3; Wahrnehmbare Wärmelast pro Person: 73.2678 W; Wärmegewinn insgesamt pro Person: 131.882 W
ID-Daten - Name: Vorratskeller; Nummer: 2
Phasen - Phase: Phase 01

# IfcSpace: Wohnzimmer 9:2832112, 9
In: Erdgeschoss
LongName: Wohnzimmer; InteriorOrExteriorSpace: INTERNAL
Pset_AirSideSystemInformation - Name: Wohnzimmer; sets with these values: 2
Pset_SpaceCommon - Reference: Wohnzimmer 9
RÄUME - nach Tops und Flächenzuordnung - Nr: 9; Name: Wohnzimmer; sets with these values: 2
RÄUME - nach Ebene mit Fläche & Umfang - Ebene: Erdgeschoss; Nr: 9; Name: Wohnzimmer
BaseQuantities - GrossFloorArea: 31.7557 m2; NetFloorArea: 31.7557 m2; GrossCeilingArea: 31.7557 m2; Height: 2.4384 m
Andere - Kategorie: Räume; Phasen-ID: 3
Abhängigkeiten - Basisversatz: 0 m; Versatz Oberkante: 26.2467 m; Ebene: Erdgeschoss; Obergrenze: Erdgeschoss
Bemaßungen - Lichte Höhe: 26.2467 m; Fläche: 31.7557 m2; Höhe für Berechnung: 1 m; Umfang: 23.5058 m; Volumen: 77.433 m3
Energieanalyse - Angegebene Beleuchtungslast: 0 W; Angegebene Versorgungsleistung: 0 W; Beleuchtungslast basieren auf: Nach Raumtyp; Beleuchtungslasteinheiten: Leistungsdichte; Heizlastwerte: Nach Raumtyp; Luftraum - Beitrag zu Beleuchtung: 0.2; Personenzahl: 0; Tatsächliche Beleuchtungslast: 0 W; Tatsächliche Versorgungsleistung: 0 W; Versorgungslasteinheiten: Leistungsdichte; Versorgungsleistung basieren auf: Nach Raumtyp; Angegebene Beleuchtungslast pro Fläche: 10.7639 kg/s3; Angegebene Versorgungsleistung pro Fläche: 13.9931 kg/s3; Fläche pro Person: 28.5714 m2; Latente Wärmelast pro Person: 58.6142 W; Tatsächliche Beleuchtungslast pro Fläche: 0 kg/s3; Tatsächliche Versorgungsleistung pro Fläche: 0 kg/s3; Wahrnehmbare Wärmelast pro Person: 73.2678 W; Wärmegewinn insgesamt pro Person: 131.882 W
ID-Daten - Name: Wohnzimmer; Nummer: 9
Phasen - Phase: Phase 01

# IfcBeam: Skelettbau Holz - Pfette mit 2 Zierköpfen:140 x 160 (3)
In: 1. Obergeschoss
Type - PredefinedType: BEAM
Type - Andere - Kategorie: Skelettbau; Familienname: Skelettbau Holz - Pfette mit 2 Zierköpfen
Type - Konstruktion - Höhe Zierelement Anfang: 0.06 m; Höhe Zierelement Ende: 0.06 m; Winkel Anschnitt Zierkopf Anfang: 0 deg; Winkel Anschnitt Zierkopf Ende: 0 deg; Zierkopf Typ Anfang: 3; Zierkopf Typ Ende: 3; Zuschnitt Unten Versatz von Oben Anfang: 0.05 m; Zuschnitt Unten Versatz von Oben Ende: 0.05 m; Zuschnitt unten Winkel Anfang: 18 deg; Zuschnitt unten Winkel Ende: 18 deg
Type - ID-Daten - Beschreibung: Holzbau; OmniClass-Nummer: 23.25.30.21.17.11; OmniClass-Titel: Wood I Joists; Typenkommentare: Pfette; Typname: 140 x 160; URL: www.autodesk.de/BIM
Type - Materialien und Oberflächen - MAT_Hirnholz: Holz - Astfichte Hirnholz
Type - Vollständige Legende - Vertikaler Profilversatz 1: 0.32 m; Vertikaler Profilversatz 1a: 0.32 m; Vertikaler Profilversatz 2: 0.32 m; Vertikaler Profilversatz 2a: 0.32 m; Vertikaler Profilversatz 3: 0 m; Vertikaler Profilversatz 3a: 0 m; Vertikaler Profilversatz 4: 0.32 m; Vertikaler Profilversatz 4a: 0.32 m; Vertikaler Profilversatz 5: 0.32 m; Vertikaler Profilversatz 5a: 0.32 m; Vertikaler Profilversatz 6: 0.32 m; Vertikaler Profilversatz 6a: 0.32 m; Vertikaler Profilversatz 7: -0.32 m; Vertikaler Profilversatz 7a: -0.32 m
Type - Tragwerk - Querschnittsform: 31
Type - Geometrie von Tragwerksschnitt - Breite: 0.14 m; Höhe: 0.16 m; Schwerpunkt horizontal: 0.07 m; Schwerpunkt vertikal: 0.08 m
Type - Pset_BeamCommon - LoadBearing: yes
Material: Holz - Astfichte
BaseQuantities - Length: 14.192 m; CrossSectionArea: 0.0224 m2; OuterSurfaceArea: 8.51518 m2; GrossVolume: 0.3179 m3; NetVolume: 0.317396 m3
Pset_BeamCommon - Reference: 140 x 160; Span: 14.192 m
Pset_QuantityTakeOff - Reference: 140 x 160; sets with these values: 2
AVA - SKELETTBAULISTE - Typ: 140 x 160; Länge: 14.192 m; Volumen: 0.317396 m3
ING - TRÄGERLISTE - Typ: 140 x 160; Länge: 14.192 m; Schnittlänge: 14.192 m; Volumen: 0.317396 m3
Pset_AG_AIA - Balkenlänge: 14.192 m
Andere - Familie: Skelettbau Holz - Pfette mit 2 Zierköpfen; Familie und Typ: Skelettbau Holz - Pfette mit 2 Zierköpfen: 140 x 160; Typ: 140 x 160; Typ-ID: 2634051
Abhängigkeiten - Querschnittdrehung: 0 deg; Referenzebene: Traufe; Winkel Anfang: 90 deg; Winkel Ende: 90 deg; Höhe Referenzebene: 5.65 m
Bemaßungen - Balkenlänge: 14.192 m; Länge: 14.192 m; Volumen: 0.317396 m3
ID-Daten - Hat Verknüpfung: no
Vollständige Legende - Längenzugabe Anfang: 0 m; Längenzugabe Ende: 0 m; B-Verlängerung Balken Anfang: 0.16 m; B-Verlängerung Balken Ende: 0.16 m; Verlängerung Zierprofil: 14.192 m
Phasen - Phase erstellt: Phase 01
Tragwerk - Einfügesymbolposition: Geometrie - Mitte; Tragwerksverwendung: Sonstige; Schnittlänge: 14.192 m
Geometrische Position - Verbindungsstatus: Beide Verbindungen aktiviert; y-Ausrichtung: Ursprung; y-Versatzwert: 0 m; yz-Ausrichtung: Einheitlich; z-Ausrichtung: Oben; Endverlängerung: 0 m; Startverlängerung: 0 m
Name (Skelettbau Holz - Pfette mit 2 Zierköpfen:140 x 160:...) | IsExternal | Slope (deg) | Endebenenversatz (m) | Startebenenversatz (m) | Höhe oben (m) | Höhe unten (m) | Anfangsfugenkürzung (m) | z-Versatzwert (m)
2636648 | yes | 0 | 0.515252 | 0.515252 | 5.98585 | 5.82585 | -0.04 | -0.179399 | Abhängigkeiten - Ausrichtung: Horizontal; Arbeitsebene: Basisdach : Ziegeldach 340; Geometrische Position - Endfugenkürzung: 0 m
2640073 | no | 0.00150542 | 3.21553 | 3.21516 |  |  | -0.04 | -0.179399
2765392 | no | 0 | 0.385 | 0.385 | 6.035 | 5.875 |  | 0

# IfcBeam: Skelettbau Holz - Pfette mit 2 Zierköpfen:160 x 220 (2)
In: 1. Obergeschoss
Type - PredefinedType: BEAM
Type - Andere - Kategorie: Skelettbau; Familienname: Skelettbau Holz - Pfette mit 2 Zierköpfen
Type - Konstruktion - Winkel Anschnitt Zierkopf Anfang: 0 deg; Winkel Anschnitt Zierkopf Ende: 0 deg; Zierkopf Typ Anfang: 3; Zierkopf Typ Ende: 3; Zuschnitt unten Winkel Anfang: 18 deg; Zuschnitt unten Winkel Ende: 18 deg; Höhe Zierelement Anfang: 0.06 m; Höhe Zierelement Ende: 0.06 m; Zuschnitt Unten Versatz von Oben Anfang: 0.05 m; Zuschnitt Unten Versatz von Oben Ende: 0.05 m
Type - ID-Daten - Beschreibung: Holzbau; OmniClass-Nummer: 23.25.30.21.17.11; OmniClass-Titel: Wood I Joists; Typenkommentare: Pfette; Typname: 160 x 220; URL: www.autodesk.de/BIM
Type - Materialien und Oberflächen - MAT_Hirnholz: Holz - Astfichte Hirnholz
Type - Vollständige Legende - Vertikaler Profilversatz 3: 0 m; Vertikaler Profilversatz 3a: 0 m; Vertikaler Profilversatz 1: 0.44 m; Vertikaler Profilversatz 1a: 0.44 m; Vertikaler Profilversatz 2: 0.44 m; Vertikaler Profilversatz 2a: 0.44 m; Vertikaler Profilversatz 4: 0.44 m; Vertikaler Profilversatz 4a: 0.44 m; Vertikaler Profilversatz 5: 0.44 m; Vertikaler Profilversatz 5a: 0.44 m; Vertikaler Profilversatz 6: 0.44 m; Vertikaler Profilversatz 6a: 0.44 m; Vertikaler Profilversatz 7: -0.44 m; Vertikaler Profilversatz 7a: -0.44 m
Type - Tragwerk - Querschnittsform: 31
Type - Geometrie von Tragwerksschnitt - Breite: 0.16 m; Höhe: 0.22 m; Schwerpunkt horizontal: 0.08 m; Schwerpunkt vertikal: 0.11 m
Type - Pset_BeamCommon - LoadBearing: yes
Material: Holz - Astfichte
BaseQuantities - Length: 14.192 m; CrossSectionArea: 0.0352 m2; OuterSurfaceArea: 10.7859 m2; GrossVolume: 0.499557 m3; NetVolume: 0.498981 m3
Pset_BeamCommon - IsExternal: no; Slope: 0 deg; Reference: 160 x 220; Span: 14.192 m
Pset_QuantityTakeOff - Reference: 160 x 220; sets with these values: 2
AVA - SKELETTBAULISTE - Typ: 160 x 220; Länge: 14.192 m; Volumen: 0.498981 m3
ING - TRÄGERLISTE - Typ: 160 x 220; Länge: 14.192 m; Schnittlänge: 14.192 m; Volumen: 0.498981 m3
Pset_AG_AIA - Balkenlänge: 14.192 m
Andere - Familie: Skelettbau Holz - Pfette mit 2 Zierköpfen; Familie und Typ: Skelettbau Holz - Pfette mit 2 Zierköpfen: 160 x 220; Typ: 160 x 220; Typ-ID: 2638323
Abhängigkeiten - Querschnittdrehung: 0 deg; Winkel Anfang: 90 deg; Winkel Ende: 90 deg; Referenzebene: 1OG OK; Höhe Referenzebene: 8.4 m
Bemaßungen - Balkenlänge: 14.192 m; Länge: 14.192 m; Volumen: 0.498981 m3
ID-Daten - Hat Verknüpfung: no
Vollständige Legende - Längenzugabe Anfang: 0 m; Längenzugabe Ende: 0 m; B-Verlängerung Balken Anfang: 0.22 m; B-Verlängerung Balken Ende: 0.22 m; Verlängerung Zierprofil: 14.192 m
Phasen - Phase erstellt: Phase 01
Tragwerk - Einfügesymbolposition: Geometrie - Mitte; Tragwerksverwendung: Sonstige; Schnittlänge: 14.192 m
Geometrische Position - Verbindungsstatus: Beide Verbindungen aktiviert; y-Ausrichtung: Ursprung; y-Versatzwert: 0 m; yz-Ausrichtung: Einheitlich; z-Ausrichtung: Oben; Endfugenkürzung: 0 m; Endverlängerung: 0 m; Startverlängerung: 0 m; Anfangsfugenkürzung: 0 m; z-Versatzwert: -0.15 m
Name (Skelettbau Holz - Pfette mit 2 Zierköpfen:160 x 220:...) | Endebenenversatz (m) = Startebenenversatz (m) | Höhe oben (m) | Höhe unten (m)
2638933 | -0.523147 | 7.72685 | 7.50685
2639730 | -0.52104 | 7.72896 | 7.50896

# IfcBeam: Skelettbau Holz - Riegel mit Schwalbenschwanz:120 x 150 (2)
In: 1. Obergeschoss
Type - PredefinedType: BEAM
Type - Andere - Kategorie: Skelettbau; Familienname: Skelettbau Holz - Riegel mit Schwalbenschwanz
Type - Konstruktion - Winkel Zapfen: 10 deg; Winkel Zapfeneinschnitt: 10 deg; Radius Zapfenende: 0.01 m; Zapfen Tiefe: 0.02 m
Type - ID-Daten - Beschreibung: Holzbau; OmniClass-Nummer: 23.25.30.21.17.11; OmniClass-Titel: Wood I Joists; Typenkommentare: Riegel mit Schwalbenschwanz; Typname: 120 x 150; URL: www.autodesk.de/BIM
Type - Materialien und Oberflächen - MAT_Hirnholz: Holz - Astfichte Hirnholz
Type - Tragwerk - Querschnittsform: 31
Type - Geometrie von Tragwerksschnitt - Breite: 0.12 m; Höhe: 0.15 m; Schwerpunkt horizontal: 0.06 m; Schwerpunkt vertikal: 0.075 m
Type - Pset_BeamCommon - LoadBearing: yes
Material: Holz - Astfichte
Pset_BeamCommon - Slope: 0 deg; Reference: 120 x 150
Pset_QuantityTakeOff - Reference: 120 x 150; sets with these values: 2
AVA - SKELETTBAULISTE - Typ: 120 x 150
ING - TRÄGERLISTE - Typ: 120 x 150
Andere - Familie: Skelettbau Holz - Riegel mit Schwalbenschwanz; Familie und Typ: Skelettbau Holz - Riegel mit Schwalbenschwanz: 120 x 150; Typ: 120 x 150; Typ-ID: 2624598
Abhängigkeiten - Winkel Anfang: 90 deg; Winkel Ende: 90 deg
ID-Daten - Hat Verknüpfung: no
Vollständige Legende - Längenzugabe Anfang: 0 m; Längenzugabe Ende: 0 m
Phasen - Phase erstellt: Phase 01
Tragwerk - Einfügesymbolposition: Geometrie - Mitte; Tragwerksverwendung: Sonstige
Geometrische Position - y-Ausrichtung: Ursprung; y-Versatzwert: 0 m; yz-Ausrichtung: Einheitlich; z-Ausrichtung: Oben; z-Versatzwert: 0 m; Verbindungsstatus: Eine oder zwei Verbindungen deaktiviert; Endverlängerung: 0 m; Startverlängerung: 0 m
Name (Skelettbau Holz - Riegel mit Schwalbenschwanz:120 x 150:...) | CrossSectionArea (m2) | NetVolume (m3) = AVA - SKELETTBAULISTE, Volumen (m3) = ING - TRÄGERLISTE, Volumen (m3) = Bemaßungen, Volumen (m3) | IsExternal | Span (m) = AVA - SKELETTBAULISTE, Länge (m) = ING - TRÄGERLISTE, Länge (m) = Pset_AG_AIA, Balkenlänge (m) = Bemaßungen, Balkenlänge (m) = Bemaßungen, Länge (m) | ING - TRÄGERLISTE, Schnittlänge (m) = Tragwerk, Schnittlänge (m) | Querschnittdrehung (deg) | Referenzebene | Endebenenversatz (m) = Startebenenversatz (m) | Höhe Referenzebene (m) | Höhe oben (m) | Höhe unten (m)
2625228 | 0.399847 | 0.0251385 | yes | 1.3825 | 1.4225 | 0 | Traufe | 2.29859 | 5.65 | 7.97629 | 7.78783 | Abhängigkeiten - Arbeitsebene: Basisdach : Ziegeldach 340; Ausrichtung: Normal
2632803 | 0.380987 | 0.0238811 | no | 1.31265 | 1.35265 | -27.5 | 1OG OK | -0.814812 | 8.4 | 7.61289 | 7.42443

# IfcBeam: Skelettbau Holz - Sparren mit Zierkopf:80 x 150 (42)
In: 1. Obergeschoss
Type - PredefinedType: BEAM
Type - Andere - Kategorie: Skelettbau; Familienname: Skelettbau Holz - Sparren mit Zierkopf
Type - Konstruktion - Höhe Zierelement: 0.04 m; Winkel Anschnitt Zierkopf: 0 deg; Zierkopf Typ: 5; Zuschnitt Unten Versatz von Oben: 0.05 m; Zuschnitt Unten Winkel: 18 deg
Type - ID-Daten - Beschreibung: Holzbau; OmniClass-Nummer: 23.25.30.21.17.11; OmniClass-Titel: Wood I Joists; Typenkommentare: Sparren; Typname: 80 x 150; URL: www.autodesk.de/BIM
Type - Materialien und Oberflächen - MAT_Hirnholz: Holz - Astfichte Hirnholz
Type - Vollständige Legende - Hakenblattung Länge: 0.375 m; Horizontaler Profilversatz 7: 0 m; Vertikaler Profilversatz 1: 0.3 m; Vertikaler Profilversatz 2: 0.3 m; Vertikaler Profilversatz 3: 0.3 m; Vertikaler Profilversatz 4: 0.3 m; Vertikaler Profilversatz 5: 0 m; Vertikaler Profilversatz 6: 0.3 m; Vertikaler Profilversatz 7: -0.3 m
Type - Sekundäres Ende - Radius Zapfenende: 0.01 m; Winkel Zapfen: 10 deg; Winkel Zapfeneinschnitt: 10 deg; Zapfen Tiefe: 0.02 m
Type - Tragwerk - Querschnittsform: 31
Type - Geometrie von Tragwerksschnitt - Breite: 0.08 m; Höhe: 0.15 m; Schwerpunkt horizontal: 0.04 m; Schwerpunkt vertikal: 0.075 m
Type - Pset_BeamCommon - LoadBearing: yes
Material: Holz - Astfichte
Pset_BeamCommon - Reference: 80 x 150; Slope: 27.5 deg
Pset_QuantityTakeOff - Reference: 80 x 150; sets with these values: 2
AVA - SKELETTBAULISTE - Typ: 80 x 150
ING - TRÄGERLISTE - Typ: 80 x 150
Andere - Familie: Skelettbau Holz - Sparren mit Zierkopf; Familie und Typ: Skelettbau Holz - Sparren mit Zierkopf: 80 x 150; Typ: 80 x 150; Typ-ID: 2617096
Abhängigkeiten - Dachneigung: 27.5 deg; Querschnittdrehung: 0 deg; Winkel Anfang: 90 deg; Winkel Ende: 90 deg
ID-Daten - Hat Verknüpfung: no
Vollständige Legende - B_Breite 1 Ende: 0.02 m; B_Breite 2 Ende: 0.02 m; B_Dachneigung: 27.5 deg; B_Erstes Ende: 0.04 m; B_Hakenblattung Ende Oben: 0.15 m; B_Hakenblattung Ende Unten: 0.15 m; B_Verlängerung Ende: 0.02 m; B_Winkel Anfang: 90 deg; B_Winkel Ende: 90 deg; B_Zweites Ende: -0.04 m; B-Verlängerung Balken: 0.15 m; Keine Zapfenverbindung am Ende: yes; Längenzugabe Anfang: 0 m; Längenzugabe Ende: 0 m
Phasen - Phase erstellt: Phase 01
Sekundäres Ende - Hakenblattung Ende Oben: no; Hakenblattung Ende Unten: no; Zapfenverbindung am Ende: no
Tragwerk - Einfügesymbolposition: Geometrie - Mitte; Tragwerksverwendung: Sonstige
Geometrische Position - y-Ausrichtung: Ursprung; y-Versatzwert: 0 m; yz-Ausrichtung: Einheitlich; z-Ausrichtung: Oben; z-Versatzwert: 0 m
Name (Skelettbau Holz - Sparren mit Zierkopf:80 x 150:...) | CrossSectionArea (m2) | NetVolume (m3) = AVA - SKELETTBAULISTE, Volumen (m3) = ING - TRÄGERLISTE, Volumen (m3) = Bemaßungen, Volumen (m3) | IsExternal | Span (m) = AVA - SKELETTBAULISTE, Länge (m) = ING - TRÄGERLISTE, Länge (m) = ING - TRÄGERLISTE, Schnittlänge (m) = Pset_AG_AIA, Balkenlänge (m) = Bemaßungen, Balkenlänge (m) = Bemaßungen, Länge (m) = Verlängerung Zierprofil (m) = Tragwerk, Schnittlänge (m) | Arbeitsebene | Ausrichtung | Endebenenversatz (m) | Höhe Referenzebene (m) | Referenzebene | Startebenenversatz (m) | Endverlängerung (m) | Startverlängerung (m) | Verbindungsstatus
2618243 | 1.6415 | 0.0850039 | yes | 7.125 | Basisdach : Ziegeldach 340 | Horizontal | 3.21516 | 5.65 | Traufe | -0.0748014 | 0.685312 | 0.180414 | Beide Verbindungen aktiviert
2619582 | 1.6415 | 0.0850039 | yes | 7.125 | Basisdach : Ziegeldach 340 | Horizontal | 3.21516 | 5.65 | Traufe | -0.0748014 | 0.685312 | 0.180414 | Beide Verbindungen aktiviert
2619662 | 1.6415 | 0.0850039 | yes | 7.125 | Basisdach : Ziegeldach 340 | Horizontal | 3.21516 | 5.65 | Traufe | -0.0748014 | 0.685312 | 0.180414 | Beide Verbindungen aktiviert
2619673 | 1.6415 | 0.0850039 | yes | 7.125 | Basisdach : Ziegeldach 340 | Horizontal | 3.21516 | 5.65 | Traufe | -0.0748014 | 0.685312 | 0.180414 | Beide Verbindungen aktiviert
2619682 | 1.6415 | 0.0850039 | yes | 7.125 | Basisdach : Ziegeldach 340 | Horizontal | 3.21516 | 5.65 | Traufe | -0.0748014 | 0.685312 | 0.180414 | Beide Verbindungen aktiviert
2619875 | 1.6415 | 0.0850039 | yes | 7.125 | Basisdach : Ziegeldach 340 | Horizontal | 3.21516 | 5.65 | Traufe | -0.0748014 | 0.685312 | 0.180414 | Beide Verbindungen aktiviert
2619899 | 1.6415 | 0.0850039 | yes | 7.125 | Basisdach : Ziegeldach 340 | Horizontal | 3.21516 | 5.65 | Traufe | -0.0748014 | 0.685312 | 0.180414 | Beide Verbindungen aktiviert
2619928 | 1.6415 | 0.0850039 | yes | 7.125 | Basisdach : Ziegeldach 340 | Horizontal | 3.21516 | 5.65 | Traufe | -0.0748014 | 0.685312 | 0.180414 | Beide Verbindungen aktiviert
2619956 | 1.6415 | 0.0850039 | yes | 7.125 | Basisdach : Ziegeldach 340 | Horizontal | 3.21516 | 5.65 | Traufe | -0.0748014 | 0.685312 | 0.180414 | Beide Verbindungen aktiviert
2619967 | 1.64439 | 0.0848778 | yes | 7.125 | Basisdach : Ziegeldach 340 | Horizontal | 3.21516 | 5.65 | Traufe | -0.0748014 | 0.685312 | 0.180414 | Beide Verbindungen aktiviert
2619987 | 0.721504 | 0.037004 | yes | 3.125 | Basisdach : Ziegeldach 340 | Horizontal | 1.36816 | 5.65 | Traufe | -0.0748014 | -0.834637 | 0.180414 | Eine oder zwei Verbindungen deaktiviert
2619999 | 1.64439 | 0.0848778 | yes | 7.125 | Basisdach : Ziegeldach 340 | Horizontal | 3.21516 | 5.65 | Traufe | -0.0748014 | 0.685312 | 0.180414 | Beide Verbindungen aktiviert
2620029 | 1.6415 | 0.0850039 | yes | 7.125 | Basisdach : Ziegeldach 340 | Horizontal | 3.21516 | 5.65 | Traufe | -0.0748014 | 0.685312 | 0.180414 | Beide Verbindungen aktiviert
2620052 | 1.6415 | 0.0850039 | yes | 7.125 | Basisdach : Ziegeldach 340 | Horizontal | 3.21516 | 5.65 | Traufe | -0.0748014 | 0.685312 | 0.180414 | Beide Verbindungen aktiviert | Geometrische Position - Endfugenkürzung: 0 m
2620072 | 1.6415 | 0.0850039 | yes | 7.125 | Basisdach : Ziegeldach 340 | Horizontal | 3.21516 | 5.65 | Traufe | -0.0748014 | 0.685312 | 0.180414 | Beide Verbindungen aktiviert
2620087 | 1.6415 | 0.0850039 | yes | 7.125 | Basisdach : Ziegeldach 340 | Horizontal | 3.21516 | 5.65 | Traufe | -0.0748014 | 0.685312 | 0.180414 | Beide Verbindungen aktiviert
2620100 | 1.6415 | 0.0850039 | yes | 7.125 | Basisdach : Ziegeldach 340 | Horizontal | 3.21516 | 5.65 | Traufe | -0.0748014 | 0.685312 | 0.180414 | Beide Verbindungen aktiviert
2620134 | 1.6415 | 0.0850039 | yes | 7.125 | Basisdach : Ziegeldach 340 | Horizontal | 3.21516 | 5.65 | Traufe | -0.0748014 | 0.685312 | 0.180414 | Beide Verbindungen aktiviert
2620143 | 1.6415 | 0.0850039 | yes | 7.125 | Basisdach : Ziegeldach 340 | Horizontal | 3.21516 | 5.65 | Traufe | -0.0748014 | 0.685312 | 0.180414 | Beide Verbindungen aktiviert
2620156 | 1.6415 | 0.0850039 | yes | 7.125 | Basisdach : Ziegeldach 340 | Horizontal | 3.21516 | 5.65 | Traufe | -0.0748014 | 0.685312 | 0.180414 | Beide Verbindungen aktiviert
2620200 | 1.6415 | 0.0850039 | yes | 7.125 | Basisdach : Ziegeldach 340 | Horizontal | 3.21516 | 5.65 | Traufe | -0.0748014 | 0.685312 | 0.180414 | Beide Verbindungen aktiviert
2631950 | 1.6415 | 0.0850039 | no | 7.125 |  |  | 0.465157 | 8.4 | 1OG OK | -2.8248 | 0 | 0 | Beide Verbindungen aktiviert
2632204 | 1.6415 | 0.0850039 | no | 7.125 |  |  | 0.465157 | 8.4 | 1OG OK | -2.8248 | 0 | 0 | Beide Verbindungen aktiviert
2632213 | 1.6415 | 0.0850039 | no | 7.125 |  |  | 0.465157 | 8.4 | 1OG OK | -2.8248 | 0 | 0 | Beide Verbindungen aktiviert
2632222 | 1.6415 | 0.0850039 | no | 7.125 |  |  | 0.465157 | 8.4 | 1OG OK | -2.8248 | 0 | 0 | Beide Verbindungen aktiviert
2632231 | 1.6415 | 0.0850039 | no | 7.125 |  |  | 0.465157 | 8.4 | 1OG OK | -2.8248 | 0 | 0 | Beide Verbindungen aktiviert
2632246 | 1.6415 | 0.0850039 | no | 7.125 |  |  | 0.465157 | 8.4 | 1OG OK | -2.8248 | 0 | 0 | Beide Verbindungen aktiviert
2632361 | 1.64439 | 0.0848778 | no | 7.125 |  |  | 0.465157 | 8.4 | 1OG OK | -2.8248 | 0 | 0 | Beide Verbindungen aktiviert
2632373 | 0.65812 | 0.033697 | no | 2.84942 |  |  | -1.50909 | 8.4 | 1OG OK | -2.8248 | 0 | 0 | Beide Verbindungen aktiviert
2632382 | 1.64439 | 0.0848778 | no | 7.125 |  |  | 0.465157 | 8.4 | 1OG OK | -2.8248 | 0 | 0 | Beide Verbindungen aktiviert
2632396 | 1.6415 | 0.0850039 | no | 7.125 |  |  | 0.465157 | 8.4 | 1OG OK | -2.8248 | 0 | 0 | Beide Verbindungen aktiviert
2632405 | 1.6415 | 0.0850039 | no | 7.125 |  |  | 0.465157 | 8.4 | 1OG OK | -2.8248 | 0 | 0 | Beide Verbindungen aktiviert
2632418 | 1.6415 | 0.0850039 | no | 7.125 |  |  | 0.465157 | 8.4 | 1OG OK | -2.8248 | 0 | 0 | Beide Verbindungen aktiviert
2632427 | 1.6415 | 0.0850039 | no | 7.125 |  |  | 0.465157 | 8.4 | 1OG OK | -2.8248 | 0 | 0 | Beide Verbindungen aktiviert
2632436 | 1.6415 | 0.0850039 | no | 7.125 |  |  | 0.465157 | 8.4 | 1OG OK | -2.8248 | 0 | 0 | Beide Verbindungen aktiviert
2632449 | 1.6415 | 0.0850039 | no | 7.125 |  |  | 0.465157 | 8.4 | 1OG OK | -2.8248 | 0 | 0 | Beide Verbindungen aktiviert
2632458 | 1.6415 | 0.0850039 | no | 7.125 |  |  | 0.465157 | 8.4 | 1OG OK | -2.8248 | 0 | 0 | Beide Verbindungen aktiviert
2632467 | 1.6415 | 0.0850039 | no | 7.125 |  |  | 0.465157 | 8.4 | 1OG OK | -2.8248 | 0 | 0 | Beide Verbindungen aktiviert
2632476 | 1.6415 | 0.0850039 | no | 7.125 |  |  | 0.465157 | 8.4 | 1OG OK | -2.8248 | 0 | 0 | Beide Verbindungen aktiviert
2632485 | 1.6415 | 0.0850039 | no | 7.125 |  |  | 0.465157 | 8.4 | 1OG OK | -2.8248 | 0 | 0 | Beide Verbindungen aktiviert
2632498 | 1.6415 | 0.0850039 | no | 7.125 |  |  | 0.465157 | 8.4 | 1OG OK | -2.8248 | 0 | 0 | Beide Verbindungen aktiviert
2632507 | 1.6415 | 0.0850039 | yes | 7.125 | Basisdach : Ziegeldach 340 | Horizontal | 3.21516 | 5.65 | Traufe | -0.0748014 | 0 | 0 | Beide Verbindungen aktiviert

# IfcBeam: Skelettbau Holz - Sparren mit Zierkopf:80 x 150_ohne_Zirkopf (2)
In: 1. Obergeschoss
Type - PredefinedType: BEAM
Type - Andere - Kategorie: Skelettbau; Familienname: Skelettbau Holz - Sparren mit Zierkopf
Type - Konstruktion - Winkel Anschnitt Zierkopf: 0 deg; Zuschnitt Unten Winkel: 18 deg; Höhe Zierelement: 0.04 m; Zierkopf Typ: 1; Zuschnitt Unten Versatz von Oben: 0.05 m
Type - ID-Daten - Beschreibung: Holzbau; OmniClass-Nummer: 23.25.30.21.17.11; OmniClass-Titel: Wood I Joists; Typenkommentare: Sparren; Typname: 80 x 150_ohne_Zirkopf; URL: www.autodesk.de/BIM
Type - Materialien und Oberflächen - MAT_Hirnholz: Holz - Astfichte Hirnholz
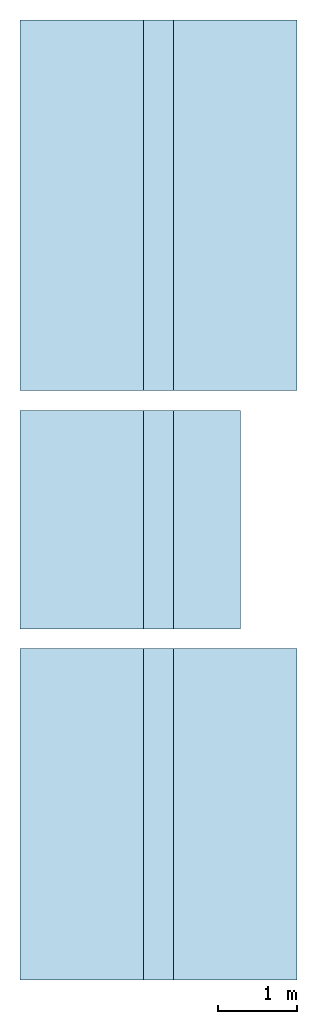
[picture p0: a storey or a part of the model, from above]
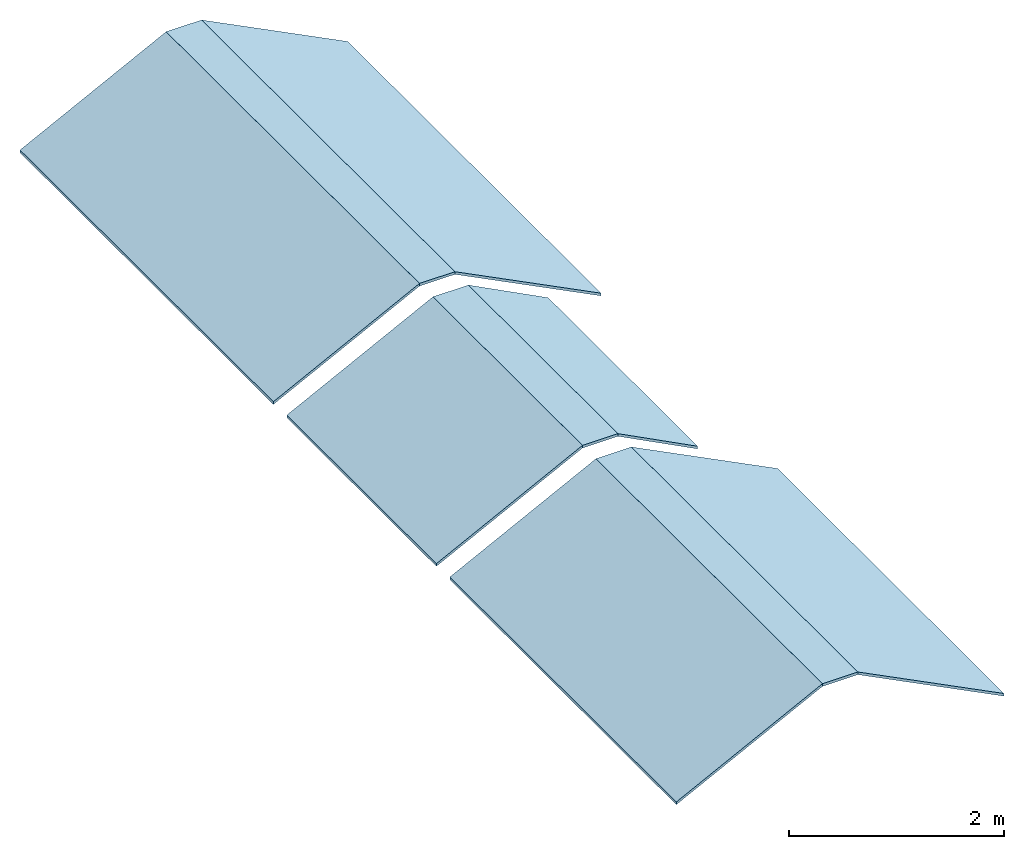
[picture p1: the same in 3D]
Properties of the parts of a building model (IFC2X3), part 2 of 5

# IfcBeam: Skelettbau Holz - Sparren mit Zierkopf:80 x 150_ohne_Zirkopf (2)
Type - Vollständige Legende - Horizontaler Profilversatz 7: 0 m; Hakenblattung Länge: 0.375 m; Vertikaler Profilversatz 1: 0 m; Vertikaler Profilversatz 2: 0.3 m; Vertikaler Profilversatz 3: 0.3 m; Vertikaler Profilversatz 4: 0.3 m; Vertikaler Profilversatz 5: 0.3 m; Vertikaler Profilversatz 6: 0.3 m; Vertikaler Profilversatz 7: -0.3 m
Type - Sekundäres Ende - Winkel Zapfen: 10 deg; Winkel Zapfeneinschnitt: 10 deg; Radius Zapfenende: 0.01 m; Zapfen Tiefe: 0.02 m
Type - Tragwerk - Querschnittsform: 31
Type - Geometrie von Tragwerksschnitt - Breite: 0.08 m; Höhe: 0.15 m; Schwerpunkt horizontal: 0.04 m; Schwerpunkt vertikal: 0.075 m
Type - Pset_BeamCommon - LoadBearing: yes
Material: Holz - Astfichte
BaseQuantities - CrossSectionArea: 0.012 m2
Pset_BeamCommon - Slope: 27.5 deg; Reference: 80 x 150_ohne_Zirkopf
Pset_QuantityTakeOff - Reference: 80 x 150_ohne_Zirkopf; sets with these values: 2
AVA - SKELETTBAULISTE - Typ: 80 x 150_ohne_Zirkopf
ING - TRÄGERLISTE - Typ: 80 x 150_ohne_Zirkopf
Andere - Familie: Skelettbau Holz - Sparren mit Zierkopf; Familie und Typ: Skelettbau Holz - Sparren mit Zierkopf: 80 x 150_ohne_Zirkopf; Typ: 80 x 150_ohne_Zirkopf; Typ-ID: 2627640
Abhängigkeiten - Querschnittdrehung: 0 deg; Winkel Anfang: 90 deg; Winkel Ende: 90 deg
ID-Daten - Hat Verknüpfung: no
Vollständige Legende - B_Winkel Anfang: 90 deg; B_Winkel Ende: 90 deg; Keine Zapfenverbindung am Ende: yes; Längenzugabe Anfang: 0 m; Längenzugabe Ende: 0 m; B_Breite 1 Ende: 0.02 m; B_Breite 2 Ende: 0.02 m; B_Erstes Ende: 0.04 m; B_Hakenblattung Ende Oben: 0.15 m; B_Hakenblattung Ende Unten: 0.15 m; B_Verlängerung Ende: 0.02 m; B_Zweites Ende: -0.04 m; B-Verlängerung Balken: 0.15 m
Phasen - Phase erstellt: Phase 01
Sekundäres Ende - Hakenblattung Ende Oben: no; Hakenblattung Ende Unten: no; Zapfenverbindung am Ende: no
Tragwerk - Einfügesymbolposition: Geometrie - Mitte; Tragwerksverwendung: Sonstige
Geometrische Position - y-Ausrichtung: Ursprung; y-Versatzwert: 0 m; yz-Ausrichtung: Einheitlich; z-Ausrichtung: Oben; z-Versatzwert: 0 m
Name (Skelettbau Holz - Sparren mit Zierkopf:80 x 150_ohne_Zirkopf:...) | Length (m) = Span (m) = AVA - SKELETTBAULISTE, Länge (m) = ING - TRÄGERLISTE, Länge (m) = ING - TRÄGERLISTE, Schnittlänge (m) = Pset_AG_AIA, Balkenlänge (m) = Bemaßungen, Balkenlänge (m) = Bemaßungen, Länge (m) = Verlängerung Zierprofil (m) = Tragwerk, Schnittlänge (m) | OuterSurfaceArea (m2) | GrossVolume (m3) | NetVolume (m3) = AVA - SKELETTBAULISTE, Volumen (m3) = ING - TRÄGERLISTE, Volumen (m3) = Bemaßungen, Volumen (m3) | IsExternal | Dachneigung (deg) = B_Dachneigung (deg) | Referenzebene | Endebenenversatz (m) | Höhe Referenzebene (m) | Startebenenversatz (m) | Verbindungsstatus | Endverlängerung (m) | Startverlängerung (m)
2626900 | 1.925 | 0.8855 | 0.0231 | 0.0226315 | yes | 27.5 | Traufe | 3.21516 | 5.65 | 2.32629 | Eine oder zwei Verbindungen deaktiviert | 0.685312 | -0.645363 | Abhängigkeiten - Ausrichtung: Horizontal; Arbeitsebene: Basisdach : Ziegeldach 340; Geometrische Position - Endfugenkürzung: 0 m
2633113 | 2.56 | 1.1776 | 0.03072 | 0.0304276 | no | 18 | 1OG OK | 0.39497 | 8.4 | -0.787107 | Beide Verbindungen aktiviert | 0 | -0.0684986 | Geometrische Position - Anfangsfugenkürzung: 0 m

# IfcBuildingElementProxy: Geländer 1:Geländer 1, Geländer 1:Geländer 1:2720004
In: Untergeschoss
Type - Andere - Kategorie: Allgemeines Modell; Familienname: Geländer 1
Type - ID-Daten - Bauelement: 18.01.01; Typname: Geländer 1
Pset_BuildingElementProxyCommon - Reference: Geländer 1; sets with these values: 2
Andere - Familie: Geländer 1; Familie und Typ: Geländer 1: Geländer 1; Typ: Geländer 1; Typ-ID: 2720003
Phasen - Phase erstellt: Phase 01
Tragwerk - Betonüberdeckung: c=2.0cm <2,0 cm>

# IfcColumn: STB Stütze - rund:STB ø60 (2)
In: Untergeschoss
Type - PredefinedType: COLUMN; Material: Ortbeton - bewehrt Verputzt
Type - Andere - Kategorie: Tragwerksstützen; Familienname: STB Stütze - rund; R: 0.03 m
Type - Bemaßungen - D: 0.06 m
Type - ID-Daten - Typenkommentare: D=20cm; Typname: STB ø60
Type - Materialien und Oberflächen - Tragendes Material: Ortbeton - bewehrt Verputzt
Type - Tragwerk - Querschnittsform: 35
Type - Statische Berechnung - Querschnittsfläche: 0.00282743 m2; Trägheitsmoment schwache Achse: 6.36173e-07 m4; Trägheitsmoment starke Achse: 6.36173e-07 m4; Umfang: 0.188496 m
Type - Geometrie von Tragwerksschnitt - Durchmesser: 0.06 m
Type - Pset_ColumnCommon - LoadBearing: yes
BaseQuantities - Length: 5.8589 m; CrossSectionArea: 0.00282706 m2; OuterSurfaceArea: 1.10438 m2; GrossVolume: 0.0165634 m3; NetVolume: 0.0165649 m3
Pset_ColumnCommon - IsExternal: no; Reference: STB ø60
Pset_QuantityTakeOff - Reference: STB ø60; sets with these values: 2
AVA - TRAGWERKSSTÜTZEN - Versatz unten: 0 m; Typ: STB ø60; Basisebene: Untergeschoss; Oberste Ebene: Balkon UK; Versatz oben: 3.5439 m; Länge: 5.8589 m; Volumen: 0.0165649 m3
ING - STÜTZENLISTE - Typ: STB ø60; Material: Ortbeton - bewehrt Verputzt; Länge: 5.8589 m; Volumen: 0.0165649 m3
Andere - Familie: STB Stütze - rund; Familie und Typ: STB Stütze - rund: STB ø60; Typ: STB ø60; Typ-ID: 2690563
Abhängigkeiten - Raumbegrenzung: yes; Versatz unten: 0 m; Ebene: Untergeschoss; Basisebene: Untergeschoss; Oberste Ebene: Balkon UK; Stützenstil: Vertikal; Versatz oben: 3.5439 m; Verschieben mit Raster: yes
Bemaßungen - Länge: 5.8589 m; Volumen: 0.0165649 m3
ID-Daten - Hat Verknüpfung: no
Phasen - Phase erstellt: Phase 01
Tragwerk - Betonüberdeckung - Andere Flächen: c=2.0cm <2,0 cm>; Betonüberdeckung - Obere Fläche: c=2.0cm <2,0 cm>; Betonüberdeckung - Untere Fläche: c=2.0cm <2,0 cm>
Name (STB Stütze - rund:STB ø60:...)
2690566
2690846

# IfcDoor: TU DF 1 - Haustüre:ML - 1010 x 2375, TU DF 1 - Haustüre:ML - 1010 x 2375:2563456
In: Erdgeschoss
Type - OperationType: SINGLE_SWING_RIGHT; ParameterTakesPrecedence: no; Sizeable: no; Material: Lack - grau 80-80-80, Metall - Edelstahl gebürstet
Type - TU DF 1 - Haustüre:ML - 1010 x 2375:2563456:1 - PanelOperation: SWINGING
Type - Andere - Kategorie: Türen; Familienname: TU DF 1 - Haustüre
Type - Konstruktion - Funktion: Außen; Wandabschluss: Nach Basisbauteil; Rahmenbreite Links: 0.075 m; Rahmenbreite Oben: 0.075 m; Rahmenbreite Rechts: 0.075 m; Rahmentiefe: 0.09 m
Type - Daten - Anschlag- / Bewegungsart Tür: Drehflügeltür; Anzahl Flügel: einflügelig; Anzahl Oberlichter: 0; Anzahl Seitenteile: 0; Ausführung Zarge: Blockzarge; Form Tür: rechteckig
Type - Bemaßungen - Höhe ab FBOK berechnen: yes; Angabe Lichter Durchgang Breite: 0.8 m; Angabe Lichter Durchgang Höhe: 2 m; Angabe Maueröffnungsmaß Breite: 1.01 m; Angabe Maueröffnungsmaß Höhe: 2.375 m; Breite: 1.01 m; Dicke: 0.09 m; Durchgangsbreite: 0.86 m; Durchgangshöhe: 2.3 m; Griffhöhe: 1.05 m; Größenberechnung über Lichten Durchgang: no; Größenberechnung über Maueröffnungsmaß: yes; Höhe ab FBOK: 2.375 m; Rohbaubreite: 1.01 m
Type - Grafiken - Randabstand Öffnungssymbol: 0 m
Type - ID-Daten - Beschreibung: Haustüren; OmniClass-Nummer: 23.30.10.00; OmniClass-Titel: Doors; Typenkommentare: Haustüre; Typenmarkierung: 233; Typname: ML - 1010 x 2375; URL: http://www.autodesk.de/BIM
Type - Materialien und Oberflächen - Material_Rahmen: Lack - grau 80-80-80; Material_Schwelle Fußboden: Lack - grau 80-80-80; Material_Sichtbeschläge: Metall - Edelstahl gebürstet; Material_Stoßprofil: Lack - grau 80-80-80; Material_Türblatt: Lack - grau 80-80-80; Material_Türschwelle: Metall - Edelstahl gebürstet
Type - Segmente und Formteile - Stangengriff Dicke: 0.025 m; Stangengriff Länge: 1.7 m; Stangengriff Tiefe: 0.06 m
Type - Analytische Eigenschaften - Thermische Eigenschaften definieren durch: Schemaplantypen; Analytische Konstruktion: <Keine Auswahl>
OverallHeight: 2.555 m; OverallWidth: 1.01 m
Pset_DoorCommon - IsExternal: yes; Reference: ML - 1010 x 2375
Pset_QuantityTakeOff - Reference: ML - 1010 x 2375
AVA - TÜRLISTE - Nr: TU 19; Familie: TU DF 1 - Haustüre; Typ: ML - 1010 x 2375; Breite: 1.01 m; Höhe: 2.375 m; Geschoss: Erdgeschoss
BaseQuantities - Height: 2.375 m; Width: 1.01 m; Area: 2.39875 m2
Andere - Host-ID: 2542777; AL Breite: 0.95 m; AL Höhe: 2.245 m; Familie: TU DF 1 - Haustüre; Familie und Typ: TU DF 1 - Haustüre: ML - 1010 x 2375; Sturzhöhe: 2.375 m; Typ: ML - 1010 x 2375; Typ-ID: 2563451
Abhängigkeiten - Ebene: Erdgeschoss; Schwelle/Brüstung: 0 m; Winkel Öffnungsbogen: 90 deg; Wandaufbau Innen: 0 m; Einbautiefe: 0 m; Fußbodenaufbau: 0.18 m; Wandaufbau Aussen: 0.16 m
Konstruktion - Leibungsschräge Oben: 0 m; Leibungsschräge Bandseite: 0 m; Leibungsschräge Drückerseite: 0 m
Bemaßungen - AL Abzug Bandseite: 0.03 m; AL Abzug Drückerseite: 0.03 m; AL Abzug Oben: 0.03 m; AL Abzug Unten: 0.1 m; Fläche: 5.6139 m2; Höhe: 2.375 m; Rohbauhöhe: 2.555 m; Volumen: 0.000211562 m3
Grafiken - Grundrissdarstellung Türsturz: no; Kollisionskörper einschalten: no; Tür mit Anschlag: no
ID-Daten - Kennzeichen: TU 19
Vollständige Legende - B_Einbautiefe: 1 m
Phasen - Phase erstellt: Phase 01
Schichten - Drücker Aussenseite: no; Stangengriff Aussenseite: yes

# IfcDoor: TU DF 1 - Rahmenstock flächenbündig:DL - 720 x 1300, TU DF 1 - Rahmenstock flächenbündig:DL - 720 x 1300:2817240
In: 1. Obergeschoss
Type - OperationType: SINGLE_SWING_RIGHT; ParameterTakesPrecedence: no; Sizeable: no; Material: Holz - generisch 140-100-70, Metall - Edelstahl gebürstet, Lack - grau 80-80-80
Type - TU DF 1 - Rahmenstock flächenbündig:DL - 720 x 1300:2817240:1 - PanelOperation: SWINGING
Type - Andere - Kategorie: Türen; Familienname: TU DF 1 - Rahmenstock flächenbündig
Type - Konstruktion - Funktion: Innen; Wandabschluss: Nach Basisbauteil; Drückerhöhe: 1.05 m; Rahmendicke: 0.045 m
Type - Daten - Anschlag- / Bewegungsart Tür: Drehflügeltür; Anzahl Flügel: einflügelig; Anzahl Oberlichter: 0; Anzahl Seitenteile: 0; Ausführung Zarge: Umfassungszarge; Form Tür: rechteckig
Type - Bemaßungen - Größenberechnung über Lichten Durchgang: yes; Größenberechnung über Maueröffnungsmaß: no; Höhe ab FBOK berechnen: yes; Randabstand Öffnungssymbol: 0 m; Angabe Lichter Durchgang Breite: 0.76 m; Angabe Lichter Durchgang Höhe: 1.3 m; Angabe Maueröffnungsmaß Breite: 0.76 m; Angabe Maueröffnungsmaß Höhe: 1.5 m; Breite: 0.85 m; Dicke: 0.045 m; Durchgangsbreite: 0.76 m; Durchgangshöhe: 1.3 m; Höhe ab FBOK: 1.345 m; Rohbaubreite: 0.85 m
Type - ID-Daten - Beschreibung: 1-teilig; OmniClass-Nummer: 23.30.10.00; OmniClass-Titel: Doors; Typenkommentare: Rahmenstock flächenbündig; Typenmarkierung: 236; Typname: DL - 720 x 1300; URL: http://www.autodesk.de/BIM
Type - Analytische Eigenschaften - Thermische Eigenschaften definieren durch: Schemaplantypen; Analytische Konstruktion: <Keine Auswahl>
OverallHeight: 1.525 m; OverallWidth: 0.85 m
Pset_DoorCommon - IsExternal: no; Reference: DL - 720 x 1300
Pset_QuantityTakeOff - Reference: DL - 720 x 1300
AVA - TÜRLISTE - Nr: TU 27; Familie: TU DF 1 - Rahmenstock flächenbündig; Typ: DL - 720 x 1300; Breite: 0.85 m; Höhe: 1.345 m; Geschoss: 1. Obergeschoss
BaseQuantities - Height: 1.345 m; Width: 0.85 m; Area: 1.14325 m2
Andere - Familie: TU DF 1 - Rahmenstock flächenbündig; Familie und Typ: TU DF 1 - Rahmenstock flächenbündig: DL - 720 x 1300; Host-ID: 2549374; Sturzhöhe: 1.345 m; Typ: DL - 720 x 1300; Typ-ID: 2817235
Abhängigkeiten - Schwelle/Brüstung: 0 m; Wandaufbau Bandseite: 0 m; Wandaufbau Gegenbandseite: 0 m; Winkel Öffnungsbogen: 90 deg; Ebene: 1. Obergeschoss; Fußbodenaufbau: 0.18 m
Bemaßungen - Fläche: 3.1238 m2; Höhe: 1.345 m; Rohbauhöhe: 1.525 m; Volumen: 0.000116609 m3
Grafiken - Grundrissdarstellung Türsturz: no; Kollisionskörper einschalten: no; Tür mit Anschlag: no
ID-Daten - Kennzeichen: TU 27
Vollständige Legende - Knauf Außenseite: no; Knauf Innenseite: no; Wandstärke: 0.25 m; Wandstärke Gesamt: 0.25 m
Phasen - Phase erstellt: Phase 01
Schichten - Drücker Bandseite: yes; Drücker Gegenbandseite: yes; Zylinderrosette: yes

# IfcDoor: TU DF 1 - Rahmenstock flächenbündig:DL - 720 x 1700, TU DF 1 - Rahmenstock flächenbündig:DL - 720 x 1700:2803522
In: 1. Obergeschoss
Type - OperationType: SINGLE_SWING_RIGHT; ParameterTakesPrecedence: no; Sizeable: no; Material: Holz - generisch 140-100-70, Metall - Edelstahl gebürstet, Lack - grau 80-80-80
Type - TU DF 1 - Rahmenstock flächenbündig:DL - 720 x 1700:2803522:1 - PanelOperation: SWINGING
Type - Andere - Kategorie: Türen; Familienname: TU DF 1 - Rahmenstock flächenbündig
Type - Konstruktion - Funktion: Innen; Wandabschluss: Nach Basisbauteil; Drückerhöhe: 1.05 m; Rahmendicke: 0.045 m
Type - Daten - Anschlag- / Bewegungsart Tür: Drehflügeltür; Anzahl Flügel: einflügelig; Anzahl Oberlichter: 0; Anzahl Seitenteile: 0; Ausführung Zarge: Umfassungszarge; Form Tür: rechteckig
Type - Bemaßungen - Größenberechnung über Lichten Durchgang: yes; Größenberechnung über Maueröffnungsmaß: no; Höhe ab FBOK berechnen: yes; Randabstand Öffnungssymbol: 0 m; Angabe Lichter Durchgang Breite: 0.76 m; Angabe Lichter Durchgang Höhe: 1.75 m; Angabe Maueröffnungsmaß Breite: 0.76 m; Angabe Maueröffnungsmaß Höhe: 1.5 m; Breite: 0.85 m; Dicke: 0.045 m; Durchgangsbreite: 0.76 m; Durchgangshöhe: 1.75 m; Höhe ab FBOK: 1.795 m; Rohbaubreite: 0.85 m
Type - ID-Daten - Beschreibung: 1-teilig; OmniClass-Nummer: 23.30.10.00; OmniClass-Titel: Doors; Typenkommentare: Rahmenstock flächenbündig; Typenmarkierung: 235; Typname: DL - 720 x 1700; URL: http://www.autodesk.de/BIM
Type - Analytische Eigenschaften - Thermische Eigenschaften definieren durch: Schemaplantypen; Analytische Konstruktion: <Keine Auswahl>
OverallHeight: 1.975 m; OverallWidth: 0.85 m
Pset_DoorCommon - IsExternal: no; Reference: DL - 720 x 1700
Pset_QuantityTakeOff - Reference: DL - 720 x 1700
AVA - TÜRLISTE - Nr: TU 26; Familie: TU DF 1 - Rahmenstock flächenbündig; Typ: DL - 720 x 1700; Breite: 0.85 m; Höhe: 1.795 m; Geschoss: 1. Obergeschoss
BaseQuantities - Height: 1.795 m; Width: 0.85 m; Area: 1.52575 m2
Andere - Familie: TU DF 1 - Rahmenstock flächenbündig; Familie und Typ: TU DF 1 - Rahmenstock flächenbündig: DL - 720 x 1700; Host-ID: 2549715; Sturzhöhe: 1.795 m; Typ: DL - 720 x 1700; Typ-ID: 2803517
Abhängigkeiten - Schwelle/Brüstung: 0 m; Wandaufbau Bandseite: 0 m; Wandaufbau Gegenbandseite: 0 m; Winkel Öffnungsbogen: 90 deg; Ebene: 1. Obergeschoss; Fußbodenaufbau: 0.18 m
Bemaßungen - Fläche: 3.91766 m2; Höhe: 1.795 m; Rohbauhöhe: 1.975 m; Volumen: 0.000140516 m3
Grafiken - Grundrissdarstellung Türsturz: no; Kollisionskörper einschalten: no; Tür mit Anschlag: no
ID-Daten - Kennzeichen: TU 26
Vollständige Legende - Knauf Außenseite: no; Knauf Innenseite: no; Wandstärke: 0.2 m; Wandstärke Gesamt: 0.2 m
Phasen - Phase erstellt: Phase 01
Schichten - Drücker Bandseite: yes; Drücker Gegenbandseite: yes; Zylinderrosette: yes

# IfcDoor: TU DF 1 - Rahmenstock flächenbündig:DL - 720 x 2000, TU DF 1 - Rahmenstock flächenbündig:DL - 720 x 2000:2573756
In: 1. Obergeschoss
Type - OperationType: SINGLE_SWING_LEFT; ParameterTakesPrecedence: no; Sizeable: no; Material: Holz - generisch 140-100-70, Metall - Edelstahl gebürstet, Lack - grau 80-80-80
Type - TU DF 1 - Rahmenstock flächenbündig:DL - 720 x 2000:2573756:1 - PanelOperation: SWINGING
Type - Andere - Kategorie: Türen; Familienname: TU DF 1 - Rahmenstock flächenbündig
Type - Konstruktion - Funktion: Innen; Wandabschluss: Nach Basisbauteil; Drückerhöhe: 1.05 m; Rahmendicke: 0.045 m
Type - Daten - Anschlag- / Bewegungsart Tür: Drehflügeltür; Anzahl Flügel: einflügelig; Anzahl Oberlichter: 0; Anzahl Seitenteile: 0; Ausführung Zarge: Umfassungszarge; Form Tür: rechteckig
Type - Bemaßungen - Größenberechnung über Lichten Durchgang: yes; Größenberechnung über Maueröffnungsmaß: no; Höhe ab FBOK berechnen: yes; Randabstand Öffnungssymbol: 0 m; Angabe Lichter Durchgang Breite: 0.76 m; Angabe Lichter Durchgang Höhe: 2 m; Angabe Maueröffnungsmaß Breite: 0.76 m; Angabe Maueröffnungsmaß Höhe: 2.005 m; Breite: 0.85 m; Dicke: 0.045 m; Durchgangsbreite: 0.76 m; Durchgangshöhe: 2 m; Höhe ab FBOK: 2.045 m; Rohbaubreite: 0.85 m
Type - ID-Daten - Beschreibung: 1-teilig; OmniClass-Nummer: 23.30.10.00; OmniClass-Titel: Doors; Typenkommentare: Rahmenstock flächenbündig; Typenmarkierung: 234; Typname: DL - 720 x 2000; URL: http://www.autodesk.de/BIM
Type - Analytische Eigenschaften - Thermische Eigenschaften definieren durch: Schemaplantypen; Analytische Konstruktion: <Keine Auswahl>
OverallHeight: 2.225 m; OverallWidth: 0.85 m
Pset_DoorCommon - IsExternal: no; Reference: DL - 720 x 2000
Pset_QuantityTakeOff - Reference: DL - 720 x 2000
AVA - TÜRLISTE - Nr: TU 20; Familie: TU DF 1 - Rahmenstock flächenbündig; Typ: DL - 720 x 2000; Breite: 0.85 m; Höhe: 2.045 m; Geschoss: 1. Obergeschoss
BaseQuantities - Height: 2.045 m; Width: 0.85 m; Area: 1.73825 m2
Andere - Familie: TU DF 1 - Rahmenstock flächenbündig; Familie und Typ: TU DF 1 - Rahmenstock flächenbündig: DL - 720 x 2000; Host-ID: 2549631; Sturzhöhe: 2.045 m; Typ: DL - 720 x 2000; Typ-ID: 2573752
Abhängigkeiten - Schwelle/Brüstung: 0 m; Wandaufbau Bandseite: 0 m; Wandaufbau Gegenbandseite: 0 m; Winkel Öffnungsbogen: 90 deg; Ebene: 1. Obergeschoss; Fußbodenaufbau: 0.18 m
Bemaßungen - Fläche: 4.35869 m2; Höhe: 2.045 m; Rohbauhöhe: 2.225 m; Volumen: 0.000153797 m3
Grafiken - Grundrissdarstellung Türsturz: no; Kollisionskörper einschalten: no; Tür mit Anschlag: no
ID-Daten - Kennzeichen: TU 20
Vollständige Legende - Knauf Außenseite: no; Knauf Innenseite: no; Wandstärke: 0.25 m; Wandstärke Gesamt: 0.25 m
Phasen - Phase erstellt: Phase 01
Schichten - Drücker Bandseite: yes; Drücker Gegenbandseite: yes; Zylinderrosette: yes

# IfcDoor: TU DF 1 - Rahmenstock flächenbündig:DL - 760 x 2000, TU DF 1 - Rahmenstock flächenbündig:DL - 760 x 2000:2553855
In: Erdgeschoss
Type - OperationType: SINGLE_SWING_LEFT; ParameterTakesPrecedence: no; Sizeable: no; Material: Holz - generisch 140-100-70, Metall - Edelstahl gebürstet, Lack - grau 80-80-80
Type - TU DF 1 - Rahmenstock flächenbündig:DL - 760 x 2000:2553855:1 - PanelOperation: SWINGING
Type - Andere - Kategorie: Türen; Familienname: TU DF 1 - Rahmenstock flächenbündig
Type - Konstruktion - Funktion: Innen; Wandabschluss: Nach Basisbauteil; Drückerhöhe: 1.05 m; Rahmendicke: 0.045 m
Type - Daten - Anschlag- / Bewegungsart Tür: Drehflügeltür; Anzahl Flügel: einflügelig; Anzahl Oberlichter: 0; Anzahl Seitenteile: 0; Ausführung Zarge: Umfassungszarge; Form Tür: rechteckig
Type - Bemaßungen - Größenberechnung über Lichten Durchgang: yes; Größenberechnung über Maueröffnungsmaß: no; Höhe ab FBOK berechnen: yes; Randabstand Öffnungssymbol: 0 m; Angabe Lichter Durchgang Breite: 0.76 m; Angabe Lichter Durchgang Höhe: 2 m; Angabe Maueröffnungsmaß Breite: 0.76 m; Angabe Maueröffnungsmaß Höhe: 2.005 m; Breite: 0.85 m; Dicke: 0.045 m; Durchgangsbreite: 0.76 m; Durchgangshöhe: 2 m; Höhe ab FBOK: 2.045 m; Rohbaubreite: 0.85 m
Type - ID-Daten - Beschreibung: 1-teilig; OmniClass-Nummer: 23.30.10.00; OmniClass-Titel: Doors; Typenkommentare: Rahmenstock flächenbündig; Typenmarkierung: 232; Typname: DL - 760 x 2000; URL: http://www.autodesk.de/BIM
Type - Analytische Eigenschaften - Thermische Eigenschaften definieren durch: Schemaplantypen; Analytische Konstruktion: <Keine Auswahl>
OverallHeight: 2.225 m; OverallWidth: 0.85 m
Pset_DoorCommon - IsExternal: no; Reference: DL - 760 x 2000
Pset_QuantityTakeOff - Reference: DL - 760 x 2000
AVA - TÜRLISTE - Nr: TU 14; Familie: TU DF 1 - Rahmenstock flächenbündig; Typ: DL - 760 x 2000; Breite: 0.85 m; Höhe: 2.045 m; Geschoss: Erdgeschoss
BaseQuantities - Height: 2.045 m; Width: 0.85 m; Area: 1.73825 m2
Andere - Familie: TU DF 1 - Rahmenstock flächenbündig; Familie und Typ: TU DF 1 - Rahmenstock flächenbündig: DL - 760 x 2000; Host-ID: 2543580; Sturzhöhe: 2.045 m; Typ: DL - 760 x 2000; Typ-ID: 2553532
Abhängigkeiten - Ebene: Erdgeschoss; Schwelle/Brüstung: 0 m; Wandaufbau Bandseite: 0 m; Wandaufbau Gegenbandseite: 0 m; Winkel Öffnungsbogen: 90 deg; Fußbodenaufbau: 0.18 m
Bemaßungen - Fläche: 4.35869 m2; Höhe: 2.045 m; Rohbauhöhe: 2.225 m; Volumen: 0.000153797 m3
Grafiken - Grundrissdarstellung Türsturz: no; Kollisionskörper einschalten: no; Tür mit Anschlag: no
ID-Daten - Kennzeichen: TU 14
Vollständige Legende - Knauf Außenseite: no; Knauf Innenseite: no; Wandstärke: 0.2 m; Wandstärke Gesamt: 0.2 m
Phasen - Phase erstellt: Phase 01
Schichten - Drücker Bandseite: yes; Drücker Gegenbandseite: yes; Zylinderrosette: yes

# IfcDoor: TU DF 1 - Rahmenstock flächenbündig:DL - 760 x 2000 (2)
In: 1. Obergeschoss
Type - OperationType: SINGLE_SWING_RIGHT; ParameterTakesPrecedence: no; Sizeable: no; Material: Holz - generisch 140-100-70, Metall - Edelstahl gebürstet, Lack - grau 80-80-80
Type - Andere - Kategorie: Türen; Familienname: TU DF 1 - Rahmenstock flächenbündig
Type - Konstruktion - Funktion: Innen; Wandabschluss: Nach Basisbauteil; Drückerhöhe: 1.05 m; Rahmendicke: 0.045 m
Type - Daten - Anschlag- / Bewegungsart Tür: Drehflügeltür; Anzahl Flügel: einflügelig; Anzahl Oberlichter: 0; Anzahl Seitenteile: 0; Ausführung Zarge: Umfassungszarge; Form Tür: rechteckig
Type - Bemaßungen - Größenberechnung über Lichten Durchgang: yes; Größenberechnung über Maueröffnungsmaß: no; Höhe ab FBOK berechnen: yes; Randabstand Öffnungssymbol: 0 m; Angabe Lichter Durchgang Breite: 0.76 m; Angabe Lichter Durchgang Höhe: 2 m; Angabe Maueröffnungsmaß Breite: 0.76 m; Angabe Maueröffnungsmaß Höhe: 2.005 m; Breite: 0.85 m; Dicke: 0.045 m; Durchgangsbreite: 0.76 m; Durchgangshöhe: 2 m; Höhe ab FBOK: 2.045 m; Rohbaubreite: 0.85 m
Type - ID-Daten - Beschreibung: 1-teilig; OmniClass-Nummer: 23.30.10.00; OmniClass-Titel: Doors; Typenkommentare: Rahmenstock flächenbündig; Typenmarkierung: 232; Typname: DL - 760 x 2000; URL: http://www.autodesk.de/BIM
Type - Analytische Eigenschaften - Thermische Eigenschaften definieren durch: Schemaplantypen; Analytische Konstruktion: <Keine Auswahl>
Type - TU DF 1 - Rahmenstock flächenbündig:DL - 760 x 2000:2574201:1 - PanelOperation: SWINGING
OverallHeight: 2.225 m; OverallWidth: 0.85 m
Pset_DoorCommon - IsExternal: no; Reference: DL - 760 x 2000
Pset_QuantityTakeOff - Reference: DL - 760 x 2000
AVA - TÜRLISTE - Familie: TU DF 1 - Rahmenstock flächenbündig; Typ: DL - 760 x 2000; Breite: 0.85 m; Höhe: 2.045 m; Geschoss: 1. Obergeschoss
BaseQuantities - Height: 2.045 m; Width: 0.85 m; Area: 1.73825 m2
Andere - Familie: TU DF 1 - Rahmenstock flächenbündig; Familie und Typ: TU DF 1 - Rahmenstock flächenbündig: DL - 760 x 2000; Typ: DL - 760 x 2000; Typ-ID: 2553532; Sturzhöhe: 2.045 m
Abhängigkeiten - Schwelle/Brüstung: 0 m; Wandaufbau Bandseite: 0 m; Wandaufbau Gegenbandseite: 0 m; Winkel Öffnungsbogen: 90 deg; Ebene: 1. Obergeschoss; Fußbodenaufbau: 0.18 m
Bemaßungen - Fläche: 4.35869 m2; Höhe: 2.045 m; Rohbauhöhe: 2.225 m; Volumen: 0.000153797 m3
Grafiken - Grundrissdarstellung Türsturz: no; Kollisionskörper einschalten: no; Tür mit Anschlag: no
Vollständige Legende - Knauf Außenseite: no; Knauf Innenseite: no; Wandstärke: 0.25 m; Wandstärke Gesamt: 0.25 m
Phasen - Phase erstellt: Phase 01
Schichten - Drücker Bandseite: yes; Drücker Gegenbandseite: yes; Zylinderrosette: yes
Name (TU DF 1 - Rahmenstock flächenbündig:DL - 760 x 2000:...) | Nr = Kennzeichen | Host-ID
2574201 | TU 22 | 2549120
2885807 | TU 29 | 2548959

# IfcDoor: TU DF 1 - Rahmenstock flächenbündig:DL - 780 x 2000 (6)
In: Untergeschoss
Type - OperationType: SINGLE_SWING_LEFT; ParameterTakesPrecedence: no; Sizeable: no; Material: Holz - generisch 140-100-70, Metall - Edelstahl gebürstet, Lack - grau 80-80-80
Type - TU DF 1 - Rahmenstock flächenbündig:DL - 780 x 2000:2550031:1 - PanelOperation: SWINGING
Type - Andere - Kategorie: Türen; Familienname: TU DF 1 - Rahmenstock flächenbündig
Type - Konstruktion - Funktion: Innen; Drückerhöhe: 1.05 m; Rahmendicke: 0.045 m; Wandabschluss: Nach Basisbauteil
Type - Daten - Anschlag- / Bewegungsart Tür: Drehflügeltür; Anzahl Flügel: einflügelig; Anzahl Oberlichter: 0; Anzahl Seitenteile: 0; Ausführung Zarge: Umfassungszarge; Form Tür: rechteckig
Type - Bemaßungen - Angabe Lichter Durchgang Breite: 0.78 m; Angabe Lichter Durchgang Höhe: 2 m; Angabe Maueröffnungsmaß Breite: 0.76 m; Angabe Maueröffnungsmaß Höhe: 2.005 m; Breite: 0.87 m; Dicke: 0.045 m; Durchgangsbreite: 0.78 m; Durchgangshöhe: 2 m; Größenberechnung über Lichten Durchgang: yes; Größenberechnung über Maueröffnungsmaß: no; Höhe ab FBOK: 2.045 m; Höhe ab FBOK berechnen: yes; Randabstand Öffnungssymbol: 0 m; Rohbaubreite: 0.87 m
Type - ID-Daten - Beschreibung: 1-teilig; OmniClass-Nummer: 23.30.10.00; OmniClass-Titel: Doors; Typenkommentare: Rahmenstock flächenbündig; Typenmarkierung: 230; Typname: DL - 780 x 2000; URL: http://www.autodesk.de/BIM
Type - Analytische Eigenschaften - Analytische Konstruktion: <Keine Auswahl>; Thermische Eigenschaften definieren durch: Schemaplantypen
OverallHeight: 2.225 m; OverallWidth: 0.87 m
Pset_DoorCommon - IsExternal: no; Reference: DL - 780 x 2000
Pset_QuantityTakeOff - Reference: DL - 780 x 2000
AVA - TÜRLISTE - Familie: TU DF 1 - Rahmenstock flächenbündig; Typ: DL - 780 x 2000; Breite: 0.87 m; Höhe: 2.045 m; Geschoss: Untergeschoss
BaseQuantities - Height: 2.045 m; Width: 0.87 m; Area: 1.77915 m2
Andere - Familie: TU DF 1 - Rahmenstock flächenbündig; Familie und Typ: TU DF 1 - Rahmenstock flächenbündig: DL - 780 x 2000; Sturzhöhe: 2.045 m; Typ: DL - 780 x 2000; Typ-ID: 2550027
Abhängigkeiten - Ebene: Untergeschoss; Fußbodenaufbau: 0.18 m; Schwelle/Brüstung: 0 m; Wandaufbau Bandseite: 0 m; Wandaufbau Gegenbandseite: 0 m; Winkel Öffnungsbogen: 90 deg
Bemaßungen - Fläche: 4.47921 m2; Höhe: 2.045 m; Rohbauhöhe: 2.225 m; Volumen: 0.000158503 m3
Grafiken - Grundrissdarstellung Türsturz: no; Kollisionskörper einschalten: no; Tür mit Anschlag: no
Vollständige Legende - Knauf Außenseite: no; Knauf Innenseite: no; Wandstärke: 0.2 m; Wandstärke Gesamt: 0.2 m
Phasen - Phase erstellt: Phase 01
Schichten - Drücker Bandseite: yes; Drücker Gegenbandseite: yes; Zylinderrosette: yes
Name (TU DF 1 - Rahmenstock flächenbündig:DL - 780 x 2000:...) | Nr = Kennzeichen | Host-ID
2550031 | TU 1 | 2521004
2550363 | TU 2 | 2521336
2550474 | TU 3 | 2521438
2550607 | TU 4 | 2521985
2551221 | TU 8 | 2522173
2551358 | TU 9 | 2522173

# IfcDoor: TU DF 1 - Rahmenstock flächenbündig:DL - 800 x 2000, TU DF 1 - Rahmenstock flächenbündig:DL - 800 x 2000:2552536
In: Erdgeschoss
Type - OperationType: SINGLE_SWING_LEFT; ParameterTakesPrecedence: no; Sizeable: no; Material: Holz - generisch 140-100-70, Metall - Edelstahl gebürstet, Lack - grau 80-80-80
Type - Andere(Typ) - Kategorie: Türen; Familienname: TU DF 1 - Rahmenstock flächenbündig
Type - Konstruktion(Typ) - Funktion: Innen; Wandabschluss: Nach Basisbauteil; Drückerhöhe: 1.05 m; Rahmendicke: 0.045 m
Type - Daten(Typ) - Anschlag- / Bewegungsart Tür: Drehflügeltür; Anzahl Flügel: einflügelig; Anzahl Oberlichter: 0; Anzahl Seitenteile: 0; Ausführung Zarge: Umfassungszarge; Form Tür: rechteckig
Type - Bemaßungen(Typ) - Größenberechnung über Lichten Durchgang: yes; Größenberechnung über Maueröffnungsmaß: no; Höhe ab FBOK berechnen: yes; Randabstand Öffnungssymbol: 0 m; Angabe Lichter Durchgang Breite: 0.8 m; Angabe Lichter Durchgang Höhe: 2 m; Angabe Maueröffnungsmaß Breite: 0.76 m; Angabe Maueröffnungsmaß Höhe: 2.005 m; Breite: 0.89 m; Dicke: 0.045 m; Durchgangsbreite: 0.8 m; Durchgangshöhe: 2 m; Höhe ab FBOK: 2.045 m; Rohbaubreite: 0.89 m
Type - ID-Daten(Typ) - Beschreibung: 1-teilig; OmniClass-Nummer: 23.30.10.00; OmniClass-Titel: Doors; Typenkommentare: Rahmenstock flächenbündig; Typenmarkierung: 185; Typname: DL - 800 x 2000; URL: http://www.autodesk.de/BIM
Type - Analytische Eigenschaften(Typ) - Thermische Eigenschaften definieren durch: Schemaplantypen; Analytische Konstruktion: <Keine Auswahl>
Type - TU DF 1 - Rahmenstock flächenbündig:DL - 800 x 2000:2552536:1 - PanelOperation: SWINGING
OverallHeight: 2.225 m; OverallWidth: 0.89 m
Pset_DoorCommon - IsExternal: no; Reference: DL - 800 x 2000
Pset_QuantityTakeOff - Reference: DL - 800 x 2000
AVA - TÜRLISTE - Nr: TU 10; Familie: TU DF 1 - Rahmenstock flächenbündig; Typ: DL - 800 x 2000; Breite: 0.89 m; Höhe: 2.045 m; Geschoss: Erdgeschoss
BaseQuantities - Height: 2.045 m; Width: 0.89 m; Area: 1.82005 m2
Andere - Familie: TU DF 1 - Rahmenstock flächenbündig; Kategorie: Türen; Familie und Typ: TU DF 1 - Rahmenstock flächenbündig: DL - 800 x 2000; Host-ID: 2544267; Sturzhöhe: 2.045 m; Typ: DL - 800 x 2000; Typ-ID: 2097345
Abhängigkeiten - Ebene: Erdgeschoss; Schwelle/Brüstung: 0 m; Wandaufbau Bandseite: 0 m; Wandaufbau Gegenbandseite: 0 m; Winkel Öffnungsbogen: 90 deg; Fußbodenaufbau: 0.18 m
Bemaßungen - Fläche: 4.60059 m2; Höhe: 2.045 m; Rohbauhöhe: 2.225 m; Volumen: 0.000163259 m3
Grafiken - Grundrissdarstellung Türsturz: no; Kollisionskörper einschalten: no; Tür mit Anschlag: no
ID-Daten - Kennzeichen: TU 10
Vollständige Legende - Knauf Außenseite: no; Knauf Innenseite: no; Wandstärke: 0.2 m; Wandstärke Gesamt: 0.2 m
Phasen - Phase erstellt: Phase 01
Schichten - Drücker Bandseite: yes; Drücker Gegenbandseite: yes; Zylinderrosette: yes

# IfcDoor: TU DF 1 - Rahmenstock flächenbündig:DL - 800 x 2000 (2)
In: Erdgeschoss
Type - OperationType: SINGLE_SWING_RIGHT; ParameterTakesPrecedence: no; Sizeable: no; Material: Holz - generisch 140-100-70, Metall - Edelstahl gebürstet, Lack - grau 80-80-80
Type - Andere(Typ) - Kategorie: Türen; Familienname: TU DF 1 - Rahmenstock flächenbündig
Type - Konstruktion(Typ) - Funktion: Innen; Wandabschluss: Nach Basisbauteil; Drückerhöhe: 1.05 m; Rahmendicke: 0.045 m
Type - Daten(Typ) - Anschlag- / Bewegungsart Tür: Drehflügeltür; Anzahl Flügel: einflügelig; Anzahl Oberlichter: 0; Anzahl Seitenteile: 0; Ausführung Zarge: Umfassungszarge; Form Tür: rechteckig
Type - Bemaßungen(Typ) - Größenberechnung über Lichten Durchgang: yes; Größenberechnung über Maueröffnungsmaß: no; Höhe ab FBOK berechnen: yes; Randabstand Öffnungssymbol: 0 m; Angabe Lichter Durchgang Breite: 0.8 m; Angabe Lichter Durchgang Höhe: 2 m; Angabe Maueröffnungsmaß Breite: 0.76 m; Angabe Maueröffnungsmaß Höhe: 2.005 m; Breite: 0.89 m; Dicke: 0.045 m; Durchgangsbreite: 0.8 m; Durchgangshöhe: 2 m; Höhe ab FBOK: 2.045 m; Rohbaubreite: 0.89 m
Type - ID-Daten(Typ) - Beschreibung: 1-teilig; OmniClass-Nummer: 23.30.10.00; OmniClass-Titel: Doors; Typenkommentare: Rahmenstock flächenbündig; Typenmarkierung: 185; Typname: DL - 800 x 2000; URL: http://www.autodesk.de/BIM
Type - Analytische Eigenschaften(Typ) - Thermische Eigenschaften definieren durch: Schemaplantypen; Analytische Konstruktion: <Keine Auswahl>
Type - TU DF 1 - Rahmenstock flächenbündig:DL - 800 x 2000:2552634:1 - PanelOperation: SWINGING
OverallHeight: 2.225 m; OverallWidth: 0.89 m
Pset_DoorCommon - IsExternal: no; Reference: DL - 800 x 2000
Pset_QuantityTakeOff - Reference: DL - 800 x 2000
AVA - TÜRLISTE - Familie: TU DF 1 - Rahmenstock flächenbündig; Typ: DL - 800 x 2000; Breite: 0.89 m; Höhe: 2.045 m; Geschoss: Erdgeschoss
BaseQuantities - Height: 2.045 m; Width: 0.89 m; Area: 1.82005 m2
Andere - Familie: TU DF 1 - Rahmenstock flächenbündig; Kategorie: Türen; Familie und Typ: TU DF 1 - Rahmenstock flächenbündig: DL - 800 x 2000; Typ: DL - 800 x 2000; Typ-ID: 2097345; Sturzhöhe: 2.045 m
Abhängigkeiten - Ebene: Erdgeschoss; Schwelle/Brüstung: 0 m; Wandaufbau Bandseite: 0 m; Wandaufbau Gegenbandseite: 0 m; Winkel Öffnungsbogen: 90 deg; Fußbodenaufbau: 0.18 m
Bemaßungen - Fläche: 4.60059 m2; Höhe: 2.045 m; Rohbauhöhe: 2.225 m; Volumen: 0.000163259 m3
Grafiken - Grundrissdarstellung Türsturz: no; Kollisionskörper einschalten: no; Tür mit Anschlag: no
Vollständige Legende - Knauf Außenseite: no; Knauf Innenseite: no; Wandstärke: 0.2 m; Wandstärke Gesamt: 0.2 m
Phasen - Phase erstellt: Phase 01
Schichten - Drücker Bandseite: yes; Drücker Gegenbandseite: yes; Zylinderrosette: yes
Name (TU DF 1 - Rahmenstock flächenbündig:DL - 800 x 2000:...) | Nr = Kennzeichen | Host-ID
2552634 | TU 11 | 2544570
2554094 | TU 15 | 2543580

# IfcDoor: TU DF 1 - Rahmenstock flächenbündig:DL - 800 x 2000, TU DF 1 - Rahmenstock flächenbündig:DL - 800 x 2000:2554294
In: Erdgeschoss
Type - OperationType: SINGLE_SWING_RIGHT; ParameterTakesPrecedence: no; Sizeable: no; Material: Holz - generisch 140-100-70, Metall - Edelstahl gebürstet, Lack - grau 80-80-80
Type - Andere(Typ) - Kategorie: Türen; Familienname: TU DF 1 - Rahmenstock flächenbündig
Type - Konstruktion(Typ) - Funktion: Innen; Wandabschluss: Nach Basisbauteil; Drückerhöhe: 1.05 m; Rahmendicke: 0.045 m
Type - Daten(Typ) - Anschlag- / Bewegungsart Tür: Drehflügeltür; Anzahl Flügel: einflügelig; Anzahl Oberlichter: 0; Anzahl Seitenteile: 0; Ausführung Zarge: Umfassungszarge; Form Tür: rechteckig
Type - Bemaßungen(Typ) - Größenberechnung über Lichten Durchgang: yes; Größenberechnung über Maueröffnungsmaß: no; Höhe ab FBOK berechnen: yes; Randabstand Öffnungssymbol: 0 m; Angabe Lichter Durchgang Breite: 0.8 m; Angabe Lichter Durchgang Höhe: 2 m; Angabe Maueröffnungsmaß Breite: 0.76 m; Angabe Maueröffnungsmaß Höhe: 2.005 m; Breite: 0.89 m; Dicke: 0.045 m; Durchgangsbreite: 0.8 m; Durchgangshöhe: 2 m; Höhe ab FBOK: 2.045 m; Rohbaubreite: 0.89 m
Type - ID-Daten(Typ) - Beschreibung: 1-teilig; OmniClass-Nummer: 23.30.10.00; OmniClass-Titel: Doors; Typenkommentare: Rahmenstock flächenbündig; Typenmarkierung: 185; Typname: DL - 800 x 2000; URL: http://www.autodesk.de/BIM
Type - Analytische Eigenschaften(Typ) - Thermische Eigenschaften definieren durch: Schemaplantypen; Analytische Konstruktion: <Keine Auswahl>
Type - TU DF 1 - Rahmenstock flächenbündig:DL - 800 x 2000:2554294:1 - PanelOperation: SWINGING
OverallHeight: 2.225 m; OverallWidth: 0.89 m
Pset_DoorCommon - IsExternal: no; Reference: DL - 800 x 2000
Pset_QuantityTakeOff - Reference: DL - 800 x 2000
AVA - TÜRLISTE - Nr: TU 16; Familie: TU DF 1 - Rahmenstock flächenbündig; Typ: DL - 800 x 2000; Breite: 0.89 m; Höhe: 2.045 m; Geschoss: Erdgeschoss
BaseQuantities - Height: 2.045 m; Width: 0.89 m; Area: 1.82005 m2
Andere - Familie: TU DF 1 - Rahmenstock flächenbündig; Kategorie: Türen; Familie und Typ: TU DF 1 - Rahmenstock flächenbündig: DL - 800 x 2000; Typ: DL - 800 x 2000; Typ-ID: 2097345; Host-ID: 2543919; Sturzhöhe: 2.045 m
Abhängigkeiten - Ebene: Erdgeschoss; Schwelle/Brüstung: 0 m; Wandaufbau Bandseite: 0 m; Wandaufbau Gegenbandseite: 0 m; Winkel Öffnungsbogen: 90 deg; Fußbodenaufbau: 0.18 m
Bemaßungen - Fläche: 4.60059 m2; Höhe: 2.045 m; Rohbauhöhe: 2.225 m; Volumen: 0.000163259 m3
Grafiken - Grundrissdarstellung Türsturz: no; Kollisionskörper einschalten: no; Tür mit Anschlag: no
ID-Daten - Kennzeichen: TU 16
Vollständige Legende - Knauf Außenseite: no; Knauf Innenseite: no; Wandstärke: 0.25 m; Wandstärke Gesamt: 0.25 m
Phasen - Phase erstellt: Phase 01
Schichten - Drücker Bandseite: yes; Drücker Gegenbandseite: yes; Zylinderrosette: yes

# IfcDoor: TU DF 1 - Rahmenstock flächenbündig:DL - 900 x 2000, TU DF 1 - Rahmenstock flächenbündig:DL - 900 x 2000:2550906
In: Untergeschoss
Type - OperationType: SINGLE_SWING_LEFT; ParameterTakesPrecedence: no; Sizeable: no; Material: Holz - generisch 140-100-70, Metall - Edelstahl gebürstet, Lack - grau 80-80-80
Type - TU DF 1 - Rahmenstock flächenbündig:DL - 900 x 2000:2550906:1 - PanelOperation: SWINGING
Type - Andere - Kategorie: Türen; Familienname: TU DF 1 - Rahmenstock flächenbündig
Type - Konstruktion - Funktion: Innen; Wandabschluss: Nach Basisbauteil; Drückerhöhe: 1.05 m; Rahmendicke: 0.045 m
Type - Daten - Anschlag- / Bewegungsart Tür: Drehflügeltür; Anzahl Flügel: einflügelig; Anzahl Oberlichter: 0; Anzahl Seitenteile: 0; Ausführung Zarge: Umfassungszarge; Form Tür: rechteckig
Type - Bemaßungen - Größenberechnung über Lichten Durchgang: yes; Größenberechnung über Maueröffnungsmaß: no; Höhe ab FBOK berechnen: yes; Randabstand Öffnungssymbol: 0 m; Angabe Lichter Durchgang Breite: 0.78 m; Angabe Lichter Durchgang Höhe: 2 m; Angabe Maueröffnungsmaß Breite: 0.9 m; Angabe Maueröffnungsmaß Höhe: 2.005 m; Breite: 0.87 m; Dicke: 0.045 m; Durchgangsbreite: 0.78 m; Durchgangshöhe: 2 m; Höhe ab FBOK: 2.045 m; Rohbaubreite: 0.87 m
Type - ID-Daten - Beschreibung: 1-teilig; OmniClass-Nummer: 23.30.10.00; OmniClass-Titel: Doors; Typenkommentare: Rahmenstock flächenbündig; Typenmarkierung: 231; Typname: DL - 900 x 2000; URL: http://www.autodesk.de/BIM
Type - Analytische Eigenschaften - Thermische Eigenschaften definieren durch: Schemaplantypen; Analytische Konstruktion: <Keine Auswahl>
OverallHeight: 2.225 m; OverallWidth: 0.87 m
Pset_DoorCommon - IsExternal: no; Reference: DL - 900 x 2000
Pset_QuantityTakeOff - Reference: DL - 900 x 2000
AVA - TÜRLISTE - Nr: TU 7; Familie: TU DF 1 - Rahmenstock flächenbündig; Typ: DL - 900 x 2000; Breite: 0.87 m; Höhe: 2.045 m; Geschoss: Untergeschoss
BaseQuantities - Height: 2.045 m; Width: 0.87 m; Area: 1.77915 m2
Andere - Familie: TU DF 1 - Rahmenstock flächenbündig; Host-ID: 2521004; Familie und Typ: TU DF 1 - Rahmenstock flächenbündig: DL - 900 x 2000; Sturzhöhe: 2.045 m; Typ: DL - 900 x 2000; Typ-ID: 2550728
Abhängigkeiten - Ebene: Untergeschoss; Schwelle/Brüstung: 0 m; Wandaufbau Bandseite: 0 m; Wandaufbau Gegenbandseite: 0 m; Winkel Öffnungsbogen: 90 deg; Fußbodenaufbau: 0.18 m
Bemaßungen - Fläche: 4.47921 m2; Höhe: 2.045 m; Rohbauhöhe: 2.225 m; Volumen: 0.000158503 m3
Grafiken - Grundrissdarstellung Türsturz: no; Kollisionskörper einschalten: no; Tür mit Anschlag: no
ID-Daten - Kennzeichen: TU 7
Vollständige Legende - Knauf Außenseite: no; Knauf Innenseite: no; Wandstärke: 0.2 m; Wandstärke Gesamt: 0.2 m
Phasen - Phase erstellt: Phase 01
Schichten - Drücker Bandseite: yes; Drücker Gegenbandseite: yes; Zylinderrosette: yes

# IfcFlowTerminal: Duschwanne 01:750x1100, Duschwanne 01:750x1100:2808811
In: 7
Type - Material: Metall - Edelstahl satiniert, Keramik - weiß 255_255_255
Type - Andere - Kategorie: Sanitärinstallationen; Familienname: Duschwanne 01
Type - Abhängigkeiten - Vorgabe-Ansicht: 0 m
Type - Bemaßungen - Breite: 0.75 m; Tiefe: 1.1 m
Type - ID-Daten - OmniClass-Nummer: 23.40.35.00; OmniClass-Titel: Casework; Typenkommentare: Duschwanne; Typname: 750x1100; URL: www.autodesk.de/BIM
Type - Materialien und Oberflächen - Ablauf: Metall - Edelstahl satiniert; Wanne: Keramik - weiß 255_255_255
Pset_DistributionFlowElementCommon - Reference: 750x1100; sets with these values: 2
Andere - Familie: Duschwanne 01; Familie und Typ: Duschwanne 01: 750x1100; Typ: 750x1100; Typ-ID: 2808660
Abhängigkeiten - Ebene: Untergeschoss; Bauteillistenebene: Untergeschoss; Versatz von Host: 0 m; Höhe von Ebene: 0 m; Arbeitsebene: Geschossdecke : Geschossdecke 200 + 50 Bad
Bemaßungen - Fläche: 1.08149 m2; Volumen: 0.0462262 m3
Phasen - Phase erstellt: Phase 01

# IfcFlowTerminal: Duschwanne 01:750x1200, Duschwanne 01:750x1200:2807819
In: 16
Type - Material: Metall - Edelstahl satiniert, Keramik - weiß 255_255_255
Type - Andere - Kategorie: Sanitärinstallationen; Familienname: Duschwanne 01
Type - Abhängigkeiten - Vorgabe-Ansicht: 0 m
Type - Bemaßungen - Breite: 0.75 m; Tiefe: 1.2 m
Type - ID-Daten - OmniClass-Nummer: 23.40.35.00; OmniClass-Titel: Casework; Typenkommentare: Duschwanne; Typname: 750x1200; URL: www.autodesk.de/BIM
Type - Materialien und Oberflächen - Ablauf: Metall - Edelstahl satiniert; Wanne: Keramik - weiß 255_255_255
Pset_DistributionFlowElementCommon - Reference: 750x1200; sets with these values: 2
Andere - Familie: Duschwanne 01; Familie und Typ: Duschwanne 01: 750x1200; Typ: 750x1200; Typ-ID: 2807471
Abhängigkeiten - Ebene: Erdgeschoss; Versatz von Host: 0 m; Höhe von Ebene: 0 m; Arbeitsebene: Geschossdecke : Geschossdecke 200 + 50 Bad; Bauteillistenebene: Erdgeschoss
Bemaßungen - Fläche: 1.17061 m2; Volumen: 0.0502537 m3
Phasen - Phase erstellt: Phase 01

# IfcFlowTerminal: Duschwanne 01:750x900, Duschwanne 01:750x900:2806094
In: 22
Type - Material: Metall - Edelstahl satiniert, Keramik - weiß 255_255_255
Type - Andere - Kategorie: Sanitärinstallationen; Familienname: Duschwanne 01
Type - Abhängigkeiten - Vorgabe-Ansicht: 0 m
Type - Bemaßungen - Breite: 0.75 m; Tiefe: 0.9 m
Type - ID-Daten - OmniClass-Nummer: 23.40.35.00; OmniClass-Titel: Casework; Typenkommentare: Duschwanne; Typname: 750x900; URL: www.autodesk.de/BIM
Type - Materialien und Oberflächen - Ablauf: Metall - Edelstahl satiniert; Wanne: Keramik - weiß 255_255_255
Pset_DistributionFlowElementCommon - Reference: 750x900; sets with these values: 2
Andere - Familie: Duschwanne 01; Familie und Typ: Duschwanne 01: 750x900; Typ: 750x900; Typ-ID: 1602378
Abhängigkeiten - Ebene: 1. Obergeschoss; Versatz von Host: 0 m; Bauteillistenebene: 1. Obergeschoss; Höhe von Ebene: 0 m; Arbeitsebene: Geschossdecke : Geschossdecke 200 + 50 Bad
Bemaßungen - Fläche: 0.903243 m2; Volumen: 0.0381712 m3
Phasen - Phase erstellt: Phase 01

# IfcFlowTerminal: WC 03:WC (3)
Type - Material: Keramik - weiß 255_255_255
Type - Andere - Kategorie: Sanitärinstallationen; Familienname: WC 03
Type - Abhängigkeiten - Vorgabe-Ansicht: 0 m
Type - ID-Daten - Typenkommentare: WC; Typname: WC; URL: www.autodesk.de/BIM
Type - Materialien und Oberflächen - Material: Keramik - weiß 255_255_255
Pset_DistributionFlowElementCommon - Reference: WC; sets with these values: 2
Andere - Familie: WC 03; Familie und Typ: WC 03: WC; Typ: WC; Typ-ID: 1602365
Abhängigkeiten - Versatz von Host: 0 m; Höhe von Ebene: 0 m
Bemaßungen - Fläche: 0.933012 m2; Volumen: 0.0258186 m3
Phasen - Phase erstellt: Phase 01
Name (WC 03:WC:...) | In | Ebene = Bauteillistenebene | Arbeitsebene
2804312 | 22 | 1. Obergeschoss | Geschossdecke : Geschossdecke 200 + 50
2807962 | 16 | Erdgeschoss | Geschossdecke : Geschossdecke 200 + 50 Bad
2809467 | 7 | Untergeschoss | Geschossdecke : Geschossdecke 200 + 50 Bad

# IfcFlowTerminal: Waschbecken 08:300 x 500, Waschbecken 08:300 x 500:2810055
In: 7
Type - Material: Metall - Edelstahl satiniert, Keramik - weiß 255_255_255
Type - Andere - Kategorie: Sanitärinstallationen; Familienname: Waschbecken 08
Type - Abhängigkeiten - Vorgabe-Ansicht: 0 m
Type - Bemaßungen - Breite: 0.5 m; Tiefe: 0.3 m
Type - ID-Daten - Beschreibung: Waschbecken; OmniClass-Nummer: 23.45.00.00; OmniClass-Titel: Sanitary, Laundry, and Cleaning Equipment; Typenkommentare: Waschbecken; Typname: 300 x 500; URL: www.autodesk.de/BIM
Type - Materialien und Oberflächen - Ablauf: Metall - Edelstahl satiniert; Schüssel: Keramik - weiß 255_255_255
Pset_DistributionFlowElementCommon - Reference: 300 x 500; sets with these values: 2
Andere - Familie: Waschbecken 08; Familie und Typ: Waschbecken 08: 300 x 500; Typ: 300 x 500; Typ-ID: 2809886
Abhängigkeiten - Ebene: Untergeschoss; Bauteillistenebene: Untergeschoss; Versatz von Host: 0 m; Höhe von Ebene: 0 m; Arbeitsebene: Geschossdecke : Geschossdecke 200 + 50 Bad
Bemaßungen - Fläche: 0.310444 m2; Volumen: 0.0120063 m3
Phasen - Phase erstellt: Phase 01

# IfcFlowTerminal: Waschbecken 08:900 x 500 (2)
Type - Material: Metall - Edelstahl satiniert, Keramik - weiß 255_255_255
Type - Andere - Kategorie: Sanitärinstallationen; Familienname: Waschbecken 08
Type - Abhängigkeiten - Vorgabe-Ansicht: 0 m
Type - Bemaßungen - Breite: 0.9 m; Tiefe: 0.5 m
Type - ID-Daten - Beschreibung: Waschbecken; OmniClass-Nummer: 23.45.00.00; OmniClass-Titel: Sanitary, Laundry, and Cleaning Equipment; Typenkommentare: Waschbecken; Typname: 900 x 500; URL: www.autodesk.de/BIM
Type - Materialien und Oberflächen - Ablauf: Metall - Edelstahl satiniert; Schüssel: Keramik - weiß 255_255_255
Pset_DistributionFlowElementCommon - Reference: 900 x 500; sets with these values: 2
Andere - Familie: Waschbecken 08; Familie und Typ: Waschbecken 08: 900 x 500; Typ: 900 x 500; Typ-ID: 2292323
Abhängigkeiten - Arbeitsebene: Geschossdecke : Geschossdecke 200 + 50 Bad
Bemaßungen - Fläche: 0.747287 m2; Volumen: 0.0240946 m3
Phasen - Phase erstellt: Phase 01
Name (Waschbecken 08:900 x 500:...) | In | Ebene = Bauteillistenebene | Höhe von Ebene (m) = Versatz von Host (m)
2805156 | 22 | 1. Obergeschoss | 0.78
2808381 | 16 | Erdgeschoss | 0.8

# IfcFooting: Wandfundament:STB 1000 x 500 (6)
In: Untergeschoss
Type - Andere - Kategorie: Fundamente; Familienname: Wandfundament
Type - Bemaßungen - Breite: 1 m; Fundamentstärke: 0.5 m; Keine Unterbrechung bei eingefügten Elementen: yes; Standardlänge der Enderweiterung: 0 m
Type - ID-Daten - Beschreibung: Wandfundament; Modell: Streifenfundament; Typenkommentare: B/H=100/50cm; Typname: STB 1000 x 500
Type - Materialien und Oberflächen - Tragendes Material: Ortbeton - bewehrt
Type - Tragwerk - Tragwerksverwendung: Tragend
PredefinedType: STRIP_FOOTING; Material: Ortbeton - bewehrt
Pset_QuantityTakeOff - Reference: STB 1000 x 500; sets with these values: 3
ING - FUNDAMENTLISTE - Typ: STB 1000 x 500; Material: Ortbeton - bewehrt; Breite: 1 m
Andere - Familie: Wandfundament; Familie und Typ: Wandfundament: STB 1000 x 500; Typ: STB 1000 x 500; Typ-ID: 712163
Abhängigkeiten - Exzentrizität: 0 m
Bemaßungen - Höhe oben: -0.2 m; Höhe unten: -0.7 m; Höhe Vermessung oben: -0.2 m; Höhe Vermessung unten: -0.7 m
ID-Daten - Hat Verknüpfung: no
Phasen - Phase erstellt: Phase 01
Tragwerk - Betonüberdeckung - Andere Flächen: c=2.0cm <2,0 cm>; Betonüberdeckung - Obere Fläche: c=2.0cm <2,0 cm>; Betonüberdeckung - Untere Fläche: c=2.0cm <2,0 cm>
Name (Wandfundament:STB 1000 x 500:...) | ING - FUNDAMENTLISTE, Länge (m) = Bemaßungen, Länge (m) | ING - FUNDAMENTLISTE, Volumen (m3) = Bemaßungen, Volumen (m3) | Fläche (m2)
2538050 | 4.51 | 2.755 | 5.51
2538065 | 10.2759 | 5.13794 | 10.2759
2538080 | 1.98588 | 0.992939 | 1.98588
2538095 | 7.69 | 3.995 | 7.99
2538110 | 8.59 | 3.97 | 7.94
2538125 | 12.5 | 5.925 | 11.85

# IfcFurnishingElement: Küchenzeile-01 Generisch:Typ1 (2)
In: 10
Type - Material: Holz - Dunkelbraun 90-80-70, Kunststoff - grau 80-80-80
Type - Andere - Kategorie: Möbel; Familienname: Küchenzeile-01 Generisch
Type - Abhängigkeiten - Vorgabe-Ansicht: 0 m
Type - Bemaßungen - Arbeitsplatten Stärke: 0.03 m; Frontplatte: 0.03 m; Korpushöhe: 0.795 m; Korpustiefe: 0.6 m; Sockelhöhe: 0.085 m; Sockeltiefe: 0.55 m; Tiefe: 0.63 m; Tiefe Arbeitsplatte: 0.66 m
Type - ID-Daten - OmniClass-Nummer: 23.40.00.00; OmniClass-Titel: Equipment and Furnishings; Typenkommentare: Küche; Typname: Typ1; URL: www.autodesk.de/BIM
Type - Materialien und Oberflächen - Arbeitsplatte: Kunststoff - grau 80-80-80; Front: Holz - Dunkelbraun 90-80-70; Korpus: Holz - Dunkelbraun 90-80-70; Sockel: Kunststoff - grau 80-80-80
Pset_QuantityTakeOff - Reference: Typ1
Andere - Typ: Typ1; Familie: Küchenzeile-01 Generisch; Familie und Typ: Küchenzeile-01 Generisch: Typ1; Typ-ID: 2299038
Abhängigkeiten - Ebene: Erdgeschoss; Höhe von Ebene: 0 m; Bauteillistenebene: Erdgeschoss
Bemaßungen - Länge 2: 3 m
Phasen - Phase erstellt: Phase 01
Sichtbarkeit - L Form: no; U Form: no; Zeile: yes
Name (Küchenzeile-01 Generisch:Typ1:...) | Versatz von Host (m) | Arbeitsebene | Fläche (m2) | Länge 1 (m) | Länge 3 (m) | Volumen (m3)
2864523 | 0 | Geschossdecke : Geschossdecke 200 + 50 | 44.3786 | 1.76216 | 3 | 0.999851
2864679 | 0.149213 | Geschossdecke : FB Hof | 32.5942 | 1.38 | 0.822252 | 0.783012

# IfcFurnishingElement: Küchenzeile-03 Kombination:Typ1, Küchenzeile-03 Kombination:Typ1:2859376
In: 10
Type - Material: Holz - Dunkelbraun 90-80-70, Kunststoff - grau 80-80-80, <Unnamed>, Metall - Stahl matt, Metall - Edelstahl satiniert
Type - Andere - Kategorie: Möbel; Familienname: Küchenzeile-03 Kombination
Type - Abhängigkeiten - Vorgabe-Ansicht: 0 m
Type - Bemaßungen - Korpushöhe: 0.87 m; Schrankhöhe: 0.91 m; Sockelhöhe: 0.08 m; Sockeltiefe: 0.05 m
Type - Grafiken - Symbolik: yes
Type - ID-Daten - OmniClass-Nummer: 23.40.00.00; OmniClass-Titel: Equipment and Furnishings; Typenkommentare: Küche; Typname: Typ1; URL: www.autodesk.de/BIM
Type - Materialien und Oberflächen - Arbeitsplatte: Kunststoff - grau 80-80-80; Front: Holz - Dunkelbraun 90-80-70; Korpus: Holz - Dunkelbraun 90-80-70; Sockel: Kunststoff - grau 80-80-80
Pset_QuantityTakeOff - Reference: Typ1
Andere - Familie: Küchenzeile-03 Kombination; Familie und Typ: Küchenzeile-03 Kombination: Typ1; Typ: Typ1; Typ-ID: 2858735
Abhängigkeiten - Ebene: Erdgeschoss; Versatz von Host: 0 m; Höhe von Ebene: 0 m; Basisbauteil: Geschossdecke : Geschossdecke 200 + 50; Verschieben mit umliegenden Elementen: no
Bemaßungen - Fläche: 17.5341 m2; Volumen: 0.765813 m3
Phasen - Phase erstellt: Phase 01

# IfcMember: Wange:Metall 10 x 260 (3)
Type - PredefinedType: STRINGER
Material: <Unnamed>
Pset_MemberCommon - IsExternal: no; Reference: Metall 10 x 260
Pset_QuantityTakeOff - Reference: Metall 10 x 260
Andere - Familie: Wange; Familie und Typ: Wange: Metall 10 x 260; Kategorie: Treppen: Auflager; Typ: Metall 10 x 260; Typ-ID: 769396
Abhängigkeiten - Auflager von oben schneiden: Nicht abschneiden; Schnitt oberes Ende: Vertikal schneiden; Schnitt unteres Ende: Vertikal schneiden
Phasen - Phase erstellt: Phase 01
Andere(Typ) - Kategorie: Treppen: Auflager; Familienname: Wange
Bemaßungen(Typ) - Breite: 0.01 m; Gesamttiefe: 0.26 m; Konstruktionstiefe an Lauf: 0.04 m; Konstruktionstiefe an Podest: 0.1 m; Schnittprofil umkehren: no
ID-Daten(Typ) - Typname: Metall 10 x 260
Name (Zusammengebaute Treppe:Treppe:...) | In | Slope (deg) | CrossSectionArea (m2) | OuterSurfaceArea (m2) | GrossSurfaceArea (m2) | GrossVolume (m3) = NetVolume (m3)
2594539 Stringer 1 | Erdgeschoss | 52.0848 | 0.162315 | 0.0192865 | 0.343916 | 0.00162315
2594539 Stringer 2 | Erdgeschoss | 42.7971 | 0.658346 | 0.0577288 | 1.37442 | 0.00658346
2595612 Stringer 1 | 1. Obergeschoss | 0 | 0.0026 | 0.1404 | 0.1456 | 0.000676 | BaseQuantities - Length: 0.26 m; Height: 0.01 m; Width: 0.26 m

# IfcOpeningElement: Opening (36)
Name | In | Depth (m) | Height (m) | Width (m)
Basiswand:Ziegel 200:2522307 | Untergeschoss | 0.2 | 2.03546 | 0.843828 | Pset_OpeningElementCommon - Reference: Ziegel 200; sets with these values: 2; Andere - Kategorie: Wände: Rechteckige Öffnung der geraden Wand; Abhängigkeiten - Abhängigkeit unten: Untergeschoss; Versatz unten: 0 m; Abhängigkeit oben: Bis Ebene: Erdgeschoss; Nicht verknüpfte Höhe: 2.03546 m; Versatz oben: -0.564544 m; Phasen - Phase erstellt: Phase 01
Geschossdecke:Geschossdecke 200 + 50:712247 | Erdgeschoss | Pset_OpeningElementCommon - Reference: Geschossdecke 200 + 50; sets with these values: 2; Andere - Kategorie: Linien: <Skizze>; Betonauskragung: 0 m; Stahlauskragung: 0 m; BaseQuantities - Area: 2.8366 m2; Abhängigkeiten - Bestimmt Neigung: no; Definiert die konstante Höhe: no; Versatz von Basis: 0 m; Bemaßungen - Länge: 1.8 m; Neigung: 0.0833333
Geschossdecke:Geschossdecke 200 + 50:712247 | Erdgeschoss |  | 1.95 | 2.58297 | Pset_OpeningElementCommon - Reference: Geschossdecke 200 + 50; sets with these values: 2; Andere - Kategorie: Linien: <Skizze>; Betonauskragung: 0 m; Stahlauskragung: 0 m; Abhängigkeiten - Bestimmt Neigung: no; Definiert die konstante Höhe: no; Versatz von Basis: 0 m; Bemaßungen - Länge: 2.58297 m; Neigung: 0.0833333
Geschossdecke:Geschossdecke 200 + 50:712247 | Erdgeschoss |  | 1.55 | 3.4 | Pset_OpeningElementCommon - Reference: Geschossdecke 200 + 50; sets with these values: 2; Andere - Kategorie: Linien: <Skizze>; Betonauskragung: 0 m; Stahlauskragung: 0 m; Abhängigkeiten - Bestimmt Neigung: no; Definiert die konstante Höhe: no; Versatz von Basis: 0 m; Bemaßungen - Länge: 3.4 m; Neigung: 0.0833333
Basiswand:Ziegel 200:2551705 | Untergeschoss | 0.2 | 1.96 | 0.86 | Pset_OpeningElementCommon - Reference: Ziegel 200; sets with these values: 2; Andere - Kategorie: Wände: Rechteckige Öffnung der geraden Wand; Abhängigkeiten - Abhängigkeit unten: Untergeschoss; Versatz unten: 0 m; Abhängigkeit oben: Bis Ebene: Erdgeschoss; Nicht verknüpfte Höhe: 1.96 m; Versatz oben: -0.64 m; Phasen - Phase erstellt: Phase 01
Basiswand:Ziegel 200:2551705 | Untergeschoss | 3.048 | 2.225 | 0.89 | Pset_OpeningElementCommon - Reference: DL - 800 x 2000; sets with these values: 2; Andere - Kategorie: Türen; Familie: TU DF 1 - Rahmenstock flächenbündig; Familie und Typ: TU DF 1 - Rahmenstock flächenbündig: DL - 800 x 2000; Host-ID: 2544267; Sturzhöhe: 2.045 m; Typ: DL - 800 x 2000; Typ-ID: 2097345; Phasen - Phase erstellt: Phase 01; AVA - TÜRLISTE - Nr: TU 10; Familie: TU DF 1 - Rahmenstock flächenbündig; Typ: DL - 800 x 2000; Breite: 0.89 m; Höhe: 2.045 m; Geschoss: Erdgeschoss; Abhängigkeiten - Ebene: Erdgeschoss; Schwelle/Brüstung: 0 m; Wandaufbau Bandseite: 0 m; Wandaufbau Gegenbandseite: 0 m; Winkel Öffnungsbogen: 90 deg; Fußbodenaufbau: 0.18 m; Bemaßungen - Fläche: 4.60059 m2; Höhe: 2.045 m; Rohbauhöhe: 2.225 m; Volumen: 0.000163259 m3; Grafiken - Grundrissdarstellung Türsturz: no; Kollisionskörper einschalten: no; Tür mit Anschlag: no; ID-Daten - Kennzeichen: TU 10; Vollständige Legende - Knauf Außenseite: no; Knauf Innenseite: no; Wandstärke: 0.2 m; Wandstärke Gesamt: 0.2 m; Schichten - Drücker Bandseite: yes; Drücker Gegenbandseite: yes; Zylinderrosette: yes
Geschossdecke:1OG Decke 30:2776395 | 1. Obergeschoss |  | 0.799979 | 0.948706 | Pset_OpeningElementCommon - Reference: 1OG Decke 30; sets with these values: 2; Andere - Kategorie: Geschossdecken: Geschossdeckenöffnungsschnitt; Phasen - Phase erstellt: Phase 01
Geschossdecke:1OG Decke 30:2776395 | 1. Obergeschoss |  | 1.104 | 0.916134 | Pset_OpeningElementCommon - Reference: 1OG Decke 30; sets with these values: 2; Andere - Kategorie: Geschossdecken: Geschossdeckenöffnungsschnitt; Phasen - Phase erstellt: Phase 01
TU DF 1 - Rahmenstock flächenbündig:DL - 780 x 2000:2550031:1 | Untergeschoss | 0.2 | 0.87 | 2.225
TU DF 1 - Rahmenstock flächenbündig:DL - 900 x 2000:2550906:1 | Untergeschoss | 0.2 | 0.87 | 2.225
TU DF 1 - Rahmenstock flächenbündig:DL - 780 x 2000:2550363:1 | Untergeschoss | 0.2 | 2.225 | 0.87
TU DF 1 - Rahmenstock flächenbündig:DL - 780 x 2000:2550474:1 | Untergeschoss | 0.2 | 0.87 | 2.225
TU DF 1 - Rahmenstock flächenbündig:DL - 780 x 2000:2550607:1 | Untergeschoss | 0.2 | 2.225 | 0.87
TU DF 1 - Rahmenstock flächenbündig:DL - 780 x 2000:2551221:1 | Untergeschoss | 0.2 | 2.225 | 0.87
TU DF 1 - Rahmenstock flächenbündig:DL - 780 x 2000:2551358:1 | Untergeschoss | 0.2 | 2.225 | 0.87
2 x Basiswand:Ziegel+WD hart 300+250:2542197 | Untergeschoss
Basiswand:Ziegel+WD hart 300+250:2542556 | Erdgeschoss
TU DF 1 - Rahmenstock flächenbündig:DL - 760 x 2000:2553855:1 | Erdgeschoss | 0.2 | 0.85 | 2.225
TU DF 1 - Rahmenstock flächenbündig:DL - 800 x 2000:2554094:1 | Erdgeschoss | 0.2 | 0.89 | 2.225
TU DF 1 - Rahmenstock flächenbündig:DL - 800 x 2000:2554294:1 | Erdgeschoss | 0.25 | 2.225 | 0.89
Basiswand:Ziegel 250:2543919 | Erdgeschoss | 3.048 | 2.18 | 0.84
Basiswand:Ziegel 200:2544161 | Erdgeschoss | 3.048 | 2.18 | 0.84
TU DF 1 - Rahmenstock flächenbündig:DL - 800 x 2000:2552536:1 | Erdgeschoss | 0.2 | 2.225 | 0.89
TU DF 1 - Rahmenstock flächenbündig:DL - 800 x 2000:2552634:1 | Erdgeschoss | 0.2 | 0.89 | 2.225
Basiswand:Ziegel 250:2544834 | Erdgeschoss | 3.048 | 2.18 | 0.84
5 x Basiswand:Ziegel+WD hart 300+250:2546884 | 1. Obergeschoss
TU DF 1 - Rahmenstock flächenbündig:DL - 760 x 2000:2885807:1 | 1. Obergeschoss | 0.25 | 2.225 | 0.85
TU DF 1 - Rahmenstock flächenbündig:DL - 760 x 2000:2574201:1 | 1. Obergeschoss | 0.25 | 2.225 | 0.85
TU DF 1 - Rahmenstock flächenbündig:DL - 720 x 1300:2817240:1 | 1. Obergeschoss | 0.25 | 0.85 | 1.525
TU DF 1 - Rahmenstock flächenbündig:DL - 720 x 2000:2573756:1 | 1. Obergeschoss | 0.25 | 2.225 | 0.85
TU DF 1 - Rahmenstock flächenbündig:DL - 720 x 1700:2803522:1 | 1. Obergeschoss | 0.2 | 0.85 | 1.975

# IfcRailing: Geländer:Vertikale Stäbe (2)
Type - Andere - Kategorie: Geländer; Familienname: Geländer
Type - Konstruktion - Geländerhöhe: 1 m; Geländerholmversatz: -0.02 m; Geländerverbindung: Verschmelzen; Podesthöhenanpassung: 0 m; Podesthöhenanpassung verwenden: no; Tangentiales Anschlussstück: Geländer bis Berührung verlängern; Winkeliges Anschlussstück: Vertikale/Horizontale Segmente hinzufügen
Type - ID-Daten - Typname: Vertikale Stäbe
Material: Kunststoff - grau 70-70-70
Pset_QuantityTakeOff - Reference: Vertikale Stäbe
Pset_RailingCommon - IsExternal: no; Reference: Vertikale Stäbe; Height: 1.2192 m
AVA - GELÄNDERLISTE - Typ: Vertikale Stäbe
Andere - Familie: Geländer; Familie und Typ: Geländer: Vertikale Stäbe; Typ: Vertikale Stäbe; Typ-ID: 90568
Phasen - Phase erstellt: Phase 01
Name (Geländer:Vertikale Stäbe:...) | In | AVA - GELÄNDERLISTE, Länge (m) = Length (m) = Bemaßungen, Länge (m) | Versatz unten (m) | Versatz von Pfad (m)
2592438 | 1. Obergeschoss | 1.96 | -0.335 | 0 | Abhängigkeiten - Basisebene: 1. Obergeschoss
2595321 | Erdgeschoss | 3.19165 | 0 | 0.0254

# IfcRoof: Basisdach:Ziegeldach 340, Basisdach:Ziegeldach 340:2600419
In: 1. Obergeschoss
Type - Andere - Kategorie: Dächer; Familienname: Basisdach
Type - Konstruktion - Standarddicke: 0.24 m
Type - Grafiken - Farbfüllung für groben Maßstab: 12632256
Type - ID-Daten - Typenkommentare: Ziegeldach; Typname: Ziegeldach 340
Type - Analytische Eigenschaften - Absorptionsgrad: 0.1; Rauigkeit: 1; Thermischer Widerstand (R): 4.9888 s3*K/kg; Thermisch wirksame Masse: 77822.4 kg/s2/K; Wärmedurchgangskoeffizient (U): 0.200449 kg/s3/K
Material: Dachdeckung - Ziegeldach 0.04 m, Dämmung - ausgeschäumt 0.04 m, Dachdeckung - Holz 0.02 m, Dämmung - weich 0.1 m, Dämmung - ausgeschäumt 0.02 m, Dachdeckung - Holz 0.02 m
Pset_QuantityTakeOff - Reference: Ziegeldach 340
Pset_RoofCommon - IsExternal: yes; Reference: Ziegeldach 340; ProjectedArea: 186.534 m2; TotalArea: 208.41 m2
AVA - DACHLISTE - Typ: Ziegeldach 340; Fläche: 208.41 m2; Volumen: 49.5844 m3
BaseQuantities - GrossArea: 208.41 m2; NetArea: 208.41 m2
Andere - Familie: Basisdach; Familie und Typ: Basisdach: Ziegeldach 340; Typ: Ziegeldach 340; Typ-ID: 4036
Abhängigkeiten - Abhängig von Körper: no; Raumbegrenzung: yes; Basisebene: Traufe; Basisversatz von Ebene: -0.1425 m; Zuschnittsversatz oben: 0 m
Konstruktion - Dachabschluss Traufe: Lotrecht zur Dachhaut mit Zuschnitt unten; Firsthöhe von Ebene: 9.13573 m; Zuschnittsversatz unten: 0.3 m
Bemaßungen - Dicke: 0.24 m; Fläche: 208.41 m2; Neigung: 0.520567; Volumen: 49.5844 m3
Phasen - Phase erstellt: Phase 01

# IfcSlab: Geschossdecke:1OG Decke 30 (12)
Type - PredefinedType: FLOOR; Material: Trockenbau - Gipsplatte 0.03 m
Type - Andere - Kategorie: Geschossdecken; Familienname: Geschossdecke
Type - Konstruktion - Funktion: Innen; Standarddicke: 0.03 m
Type - Grafiken - Füllmuster für groben Maßstab: <Flächenfüllung>; Farbfüllung für groben Maßstab: 32768
Type - ID-Daten - Bauelement: 50.A9; Beschreibung: STB_200; Typname: 1OG Decke 30
Type - Materialien und Oberflächen - Tragendes Material: Trockenbau - Gipsplatte
Type - Tragwerk - Filter Tragend / Nichttragend: yes
Type - Analytische Eigenschaften - Absorptionsgrad: 0.1; Rauigkeit: 1; Thermischer Widerstand (R): 0.0461538 s3*K/kg; Thermisch wirksame Masse: 27720 kg/s2/K; Wärmedurchgangskoeffizient (U): 21.6667 kg/s3/K
Type - Pset_SlabCommon - ThermalTransmittance: 21.6667 kg/s3/K
Pset_QuantityTakeOff - Reference: 1OG Decke 30; sets with these values: 2
Pset_SlabCommon - IsExternal: no; LoadBearing: no; Reference: 1OG Decke 30
AVA - GESCHOSSDECKENLISTE - Typ: 1OG Decke 30
ING - GESCHOSSDECKENLISTE - Typ: 1OG Decke 30; Material: Trockenbau - Gipsplatte
Andere - Familie: Geschossdecke; Familie und Typ: Geschossdecke: 1OG Decke 30; Typ: 1OG Decke 30; Typ-ID: 2776395
Abhängigkeiten - Abhängig von Körper: no; Raumbegrenzung: yes
Bemaßungen - Dicke: 0.03 m
ID-Daten - Hat Verknüpfung: no
Phasen - Phase erstellt: Phase 01
Plattenformbearbeitung - Bedingung für gekrümmte Kante: 0
Tragwerk - Tragwerk: no
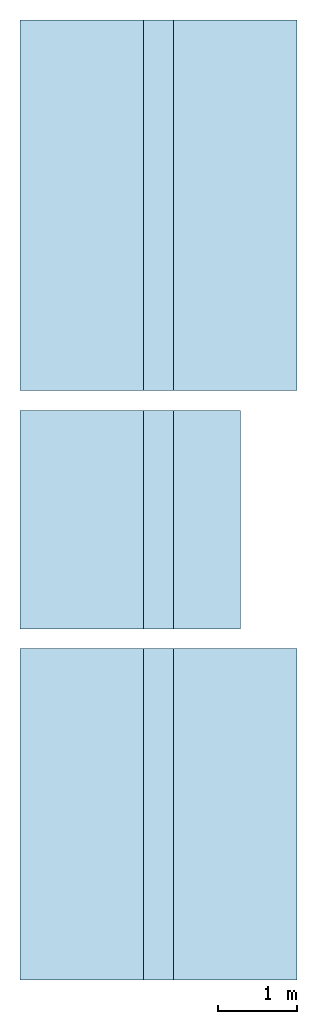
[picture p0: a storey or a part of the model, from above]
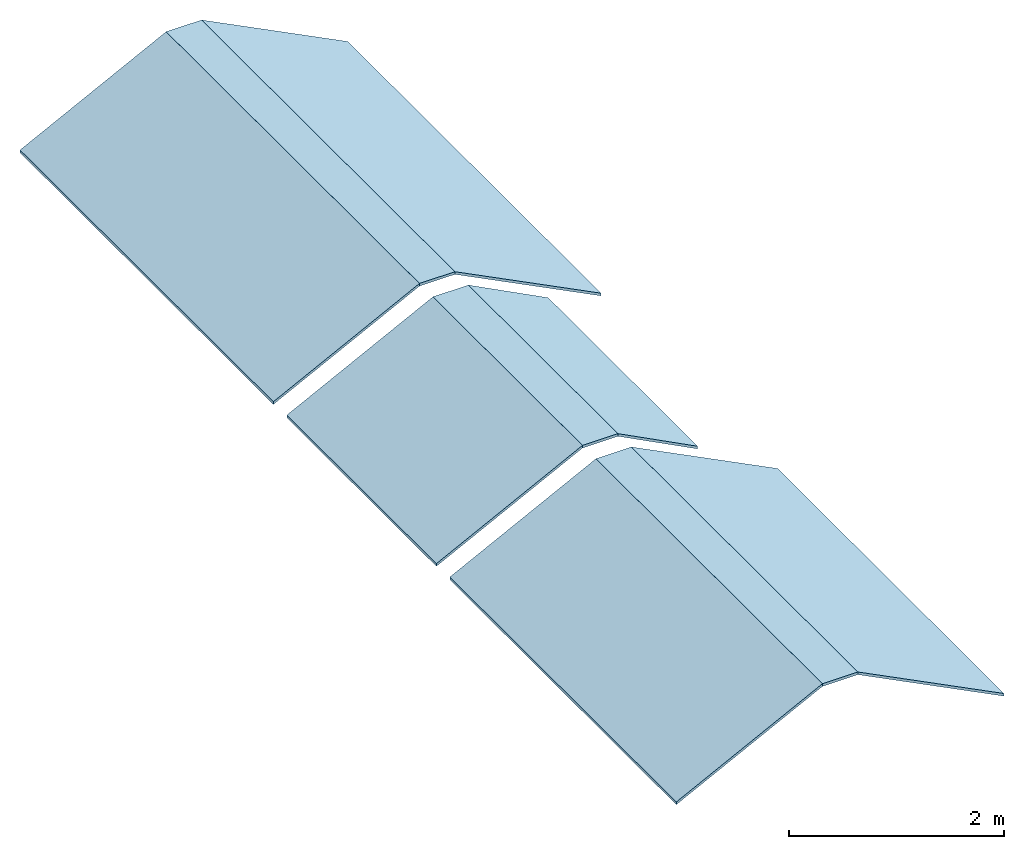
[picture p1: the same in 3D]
Properties of the parts of a building model (IFC2X3), part 3 of 5

# IfcSlab: Geschossdecke:1OG Decke 30 (12)
Name (Geschossdecke:1OG Decke 30:...) | In | PitchAngle (deg) | AVA - GESCHOSSDECKENLISTE, Umfang (m) = ING - GESCHOSSDECKENLISTE, Umfang (m) = Bemaßungen, Umfang (m) | AVA - GESCHOSSDECKENLISTE, Fläche (m2) = ING - GESCHOSSDECKENLISTE, Fläche (m2) = NetArea (m2) = Bemaßungen, Fläche (m2) | AVA - GESCHOSSDECKENLISTE, Volumen (m3) = ING - GESCHOSSDECKENLISTE, Volumen (m3) = Bemaßungen, Volumen (m3) | Perimeter (m) | GrossArea (m2) | GrossVolume (m3) | NetVolume (m3) | Ebene | Höhenversatz von Ebene (m)
2776090 | 1. Obergeschoss | 27.4415 | 12.2451 | 9.07272 | 0.272182 | 12.7301 | 9.07276 | 0.272254 | 0.241557 | 1OG OK | -0.893139
2777304 | First OK | 26.8238 | 11.5571 | 7.39968 | 0.22199 | 11.9353 | 7.39972 | 0.222048 | 0.198104 | First OK | -0.624235
2777830 | First OK | 26.8227 | 11.5571 | 7.39968 | 0.22199 | 11.9353 | 7.39965 | 0.222046 | 0.198105 | First OK | -0.624191
2777893 | 1. Obergeschoss | 27.8953 | 9.56538 | 2.71829 | 0.0815486 |  | 2.71829 |  | 0.072331 | 1OG OK | -0.891531 | Material: Trockenbau - Gipsplatte
2778571 | 1. Obergeschoss | 27.5754 | 11.0346 | 4.28961 | 0.128688 | 11.2415 | 4.28965 | 0.128724 | 0.11407 | 1OG OK | -0.893139
2778585 | First OK | 26.8238 | 12.5571 | 8.2785 | 0.248355 | 12.9353 | 8.27854 | 0.248419 | 0.221632 | First OK | -0.624235
2778600 | First OK | 26.8227 | 12.5571 | 8.2785 | 0.248355 | 12.9353 | 8.27847 | 0.248417 | 0.221633 | First OK | -0.624191
2778607 | 1. Obergeschoss | 27.3093 | 12.0484 | 6.11221 | 0.183366 | 12.3781 | 6.96632 | 0.209044 | 0.162928 | 1OG OK | -0.891531
2831610 | 1. Obergeschoss | 28.085 | 7.31459 | 1.75294 | 0.0525883 | 7.31459 | 2.43888 | 0.064551 | 0.0463963 | 1OG OK | -0.893139
2831617 | First OK | 26.8238 | 8.69705 | 4.88625 | 0.146587 | 9.07529 | 4.88627 | 0.146625 | 0.130815 | First OK | -0.624235
2842198 | First OK | 27.362 | 7.27243 | 2.68015 | 0.0804046 | 7.48817 | 2.68013 | 0.0804251 | 0.0714087 | First OK | -0.624191
2842517 | 1. Obergeschoss | 32.8462 | 11.5795 | 9.95938 | 0.298782 | 12.725 | 9.95936 | 0.29889 | 0.251015 | 1OG OK | -0.891047

# IfcSlab: Geschossdecke:Decke 1OG 30 (9)
Type - PredefinedType: FLOOR; Material: Trockenbau - Gipsplatte 0.03 m
Type - Andere - Kategorie: Geschossdecken; Familienname: Geschossdecke
Type - Konstruktion - Funktion: Innen; Standarddicke: 0.03 m
Type - Grafiken - Füllmuster für groben Maßstab: <Flächenfüllung>; Farbfüllung für groben Maßstab: 32768
Type - ID-Daten - Bauelement: 50.A9; Beschreibung: STB_200; Typname: Decke 1OG 30
Type - Materialien und Oberflächen - Tragendes Material: Trockenbau - Gipsplatte
Type - Tragwerk - Filter Tragend / Nichttragend: yes
Type - Analytische Eigenschaften - Absorptionsgrad: 0.1; Rauigkeit: 1; Thermischer Widerstand (R): 0.0461538 s3*K/kg; Thermisch wirksame Masse: 27720 kg/s2/K; Wärmedurchgangskoeffizient (U): 21.6667 kg/s3/K
Type - Pset_SlabCommon - ThermalTransmittance: 21.6667 kg/s3/K
Pset_QuantityTakeOff - Reference: Decke 1OG 30; sets with these values: 2
Pset_SlabCommon - IsExternal: no; LoadBearing: no; PitchAngle: 0 deg; Reference: Decke 1OG 30
AVA - GESCHOSSDECKENLISTE - Typ: Decke 1OG 30
ING - GESCHOSSDECKENLISTE - Typ: Decke 1OG 30; Material: Trockenbau - Gipsplatte
Andere - Familie: Geschossdecke; Familie und Typ: Geschossdecke: Decke 1OG 30; Typ: Decke 1OG 30; Typ-ID: 2771339
Abhängigkeiten - Abhängig von Körper: no; Raumbegrenzung: yes
Bemaßungen - Dicke: 0.03 m
ID-Daten - Hat Verknüpfung: no
Phasen - Phase erstellt: Phase 01
Tragwerk - Tragwerk: no
Name (Geschossdecke:Decke 1OG 30:...) | In | AVA - GESCHOSSDECKENLISTE, Umfang (m) = ING - GESCHOSSDECKENLISTE, Umfang (m) = Perimeter (m) = Bemaßungen, Umfang (m) | AVA - GESCHOSSDECKENLISTE, Fläche (m2) = ING - GESCHOSSDECKENLISTE, Fläche (m2) = GrossArea (m2) = NetArea (m2) = Bemaßungen, Fläche (m2) | AVA - GESCHOSSDECKENLISTE, Volumen (m3) = ING - GESCHOSSDECKENLISTE, Volumen (m3) = GrossVolume (m3) = NetVolume (m3) = Bemaßungen, Volumen (m3) | Width (m) | Ebene | Höhenversatz von Ebene (m) | Höhe oben (m) = Höhe oben Kern (m) | Höhe unten (m) = Höhe unten Kern (m)
2775191 | 1. Obergeschoss | 9.42 | 2.105 | 0.06315 | 0.5 | 1OG OK | -0.893147 | 7.50685 | 7.47685
2776993 | First OK | 9.18 | 1.5998 | 0.047994 | 0.38 | First OK | -0.624213 | 8.52579 | 8.49579
2777592 | 1. Obergeschoss | 9.42 | 2.105 | 0.06315 | 0.5 | 1OG OK | -0.89104 | 7.50896 | 7.47896
2778564 | 1. Obergeschoss | 10.42 | 2.355 | 0.07065 | 0.5 | 1OG OK | -0.893147 | 7.50685 | 7.47685
2778578 | First OK | 10.18 | 1.7898 | 0.053694 | 0.38 | First OK | -0.624213 | 8.52579 | 8.49579
2778593 | 1. Obergeschoss | 10.42 | 2.355 | 0.07065 | 0.5 | 1OG OK | -0.89104 | 7.50896 | 7.47896
2831541 | First OK | 6.32 | 1.0564 | 0.031692 | 0.38 | First OK | -0.624213 | 8.52579 | 8.49579
2831603 | 1. Obergeschoss | 6.42 | 1.1954 | 0.035862 | 0.43 | 1OG OK | -0.893147 | 7.50685 | 7.47685
2842268 | 1. Obergeschoss | 7.2564 | 2.358 | 0.0707399 | 0.8482 | 1OG OK | -0.89104 | 7.50896 | 7.47896

# IfcSlab: Geschossdecke:FB 100 Vorsprung, Geschossdecke:FB 100 Vorsprung:2575144
In: 1. Obergeschoss
Type - PredefinedType: FLOOR; Material: Fußboden - Parkett Roteiche 0.06 m
Type - Andere - Kategorie: Geschossdecken; Familienname: Geschossdecke
Type - Konstruktion - Funktion: Innen; Standarddicke: 0.06 m
Type - Grafiken - Füllmuster für groben Maßstab: <Flächenfüllung>; Farbfüllung für groben Maßstab: 12632256
Type - ID-Daten - Beschreibung: FB_180_Parkett; Typname: FB 100 Vorsprung
Type - Tragwerk - Filter Tragend / Nichttragend: no
Type - Analytische Eigenschaften - Absorptionsgrad: 0.1; Rauigkeit: 1
Pset_QuantityTakeOff - Reference: FB 100 Vorsprung; sets with these values: 2
Pset_SlabCommon - IsExternal: no; LoadBearing: no; PitchAngle: 0 deg; Reference: FB 100 Vorsprung
AVA - GESCHOSSDECKENLISTE - Typ: FB 100 Vorsprung; Umfang: 82.021 m; Fläche: 2.8634 m2; Volumen: 0.171804 m3
ING - GESCHOSSDECKENLISTE - Umfang: 82.021 m; Typ: FB 100 Vorsprung; Fläche: 2.8634 m2; Volumen: 0.171804 m3
BaseQuantities - Width: 1.03 m; Perimeter: 7.62 m; GrossArea: 2.8634 m2; NetArea: 2.8634 m2; GrossVolume: 0.171804 m3; NetVolume: 0.171804 m3
Andere - Familie: Geschossdecke; Familie und Typ: Geschossdecke: FB 100 Vorsprung; Typ: FB 100 Vorsprung; Typ-ID: 2836132
Abhängigkeiten - Abhängig von Körper: no; Raumbegrenzung: yes; Ebene: 1. Obergeschoss; Höhenversatz von Ebene: -0.35 m
Bemaßungen - Umfang: 82.021 m; Dicke: 0.06 m; Fläche: 2.8634 m2; Höhe oben: 5.05 m; Höhe oben Kern: 5.05 m; Höhe unten: 4.99 m; Höhe unten Kern: 4.99 m; Volumen: 0.171804 m3
ID-Daten - Hat Verknüpfung: no
Phasen - Phase erstellt: Phase 01
Tragwerk - Tragwerk: no

# IfcSlab: Geschossdecke:FB Hof (19)
Type - PredefinedType: FLOOR; Material: Mauerwerk - Kalksandstein 0.2 m
Type - Andere - Kategorie: Geschossdecken; Familienname: Geschossdecke
Type - Konstruktion - Funktion: Innen; Standarddicke: 0.2 m
Type - Grafiken - Füllmuster für groben Maßstab: <Flächenfüllung>; Farbfüllung für groben Maßstab: 32768
Type - ID-Daten - Bauelement: 50.A9; Beschreibung: STB_200; Typname: FB Hof
Type - Materialien und Oberflächen - Tragendes Material: Mauerwerk - Kalksandstein
Type - Tragwerk - Filter Tragend / Nichttragend: yes
Type - Analytische Eigenschaften - Absorptionsgrad: 0.1; Rauigkeit: 1; Thermischer Widerstand (R): 0.0689655 s3*K/kg; Thermisch wirksame Masse: 462000 kg/s2/K; Wärmedurchgangskoeffizient (U): 14.5 kg/s3/K
Type - Pset_SlabCommon - ThermalTransmittance: 14.5 kg/s3/K
Pset_QuantityTakeOff - Reference: FB Hof; sets with these values: 2
Pset_SlabCommon - IsExternal: no; LoadBearing: no; Reference: FB Hof
AVA - GESCHOSSDECKENLISTE - Typ: FB Hof
ING - GESCHOSSDECKENLISTE - Typ: FB Hof; Material: Mauerwerk - Kalksandstein
Andere - Familie: Geschossdecke; Familie und Typ: Geschossdecke: FB Hof; Typ: FB Hof; Typ-ID: 2836272
Abhängigkeiten - Abhängig von Körper: no; Raumbegrenzung: yes
Bemaßungen - Dicke: 0.2 m
ID-Daten - Hat Verknüpfung: no
Phasen - Phase erstellt: Phase 01
Tragwerk - Tragwerk: no
Name (Geschossdecke:FB Hof:...) | In | PitchAngle (deg) | AVA - GESCHOSSDECKENLISTE, Umfang (m) = ING - GESCHOSSDECKENLISTE, Umfang (m) = Bemaßungen, Umfang (m) | AVA - GESCHOSSDECKENLISTE, Fläche (m2) = ING - GESCHOSSDECKENLISTE, Fläche (m2) = NetArea (m2) = Bemaßungen, Fläche (m2) | AVA - GESCHOSSDECKENLISTE, Volumen (m3) = ING - GESCHOSSDECKENLISTE, Volumen (m3) = NetVolume (m3) = Bemaßungen, Volumen (m3) | Perimeter (m) | GrossArea (m2) | GrossVolume (m3) | Ebene | Höhenversatz von Ebene (m) | Höhe oben (m) = Höhe oben Kern (m) | Höhe unten (m) = Höhe unten Kern (m)
2688692 | Untergeschoss | 0 | 24.2711 | 31.5774 | 6.31547 | 24.1841 | 31.491 | 6.2982 | Fundament OK | 0.2 | 0 | -0.2
2689714 | Untergeschoss | 0 | 30.2054 | 3.68891 | 0.737783 | 2.96279 | 0.352813 | 0.0705625 | Fundament OK | 0.2 | 0 | -0.2
2689714:2 | Untergeschoss | 0 | 30.2054 | 3.68891 | 0.737783 | 3.02696 | 0.370678 | 0.0741356 | Fundament OK | 0.2 | 0 | -0.2
2689714:3 | Untergeschoss | 0 | 30.2054 | 3.68891 | 0.737783 | 3.02696 | 0.370678 | 0.0741356 | Fundament OK | 0.2 | 0 | -0.2
2689714:4 | Untergeschoss | 0 | 30.2054 | 3.68891 | 0.737783 | 3.02696 | 0.370678 | 0.0741356 | Fundament OK | 0.2 | 0 | -0.2
2689714:5 | Untergeschoss | 0 | 30.2054 | 3.68891 | 0.737783 | 3.02696 | 0.370678 | 0.0741356 | Fundament OK | 0.2 | 0 | -0.2
2689714:6 | Untergeschoss | 0 | 30.2054 | 3.68891 | 0.737783 | 3.02696 | 0.370678 | 0.0741356 | Fundament OK | 0.2 | 0 | -0.2
2689714:7 | Untergeschoss | 0 | 30.2054 | 3.68891 | 0.737783 | 3.02696 | 0.370678 | 0.0741356 | Fundament OK | 0.2 | 0 | -0.2
2689714:8 | Untergeschoss | 0 | 30.2054 | 3.68891 | 0.737783 | 3.02696 | 0.370678 | 0.0741356 | Fundament OK | 0.2 | 0 | -0.2
2689714:9 | Untergeschoss | 0 | 30.2054 | 3.68891 | 0.737783 | 3.02696 | 0.370678 | 0.0741356 | Fundament OK | 0.2 | 0 | -0.2
2689714:10 | Untergeschoss | 0 | 30.2054 | 3.68891 | 0.737783 | 3.02696 | 0.370678 | 0.0741356 | Fundament OK | 0.2 | 0 | -0.2
2689907 | Untergeschoss | 0 | 10.9819 | 1.1153 | 0.223061 | 1.83032 | 0.185884 | 0.0371768 | Fundament OK | 0.2 | 0 | -0.2
2689907:2 | Untergeschoss | 0 | 10.9819 | 1.1153 | 0.223061 | 1.83032 | 0.185884 | 0.0371768 | Fundament OK | 0.2 | 0 | -0.2
2689907:3 | Untergeschoss | 0 | 10.9819 | 1.1153 | 0.223061 | 1.83032 | 0.185884 | 0.0371768 | Fundament OK | 0.2 | 0 | -0.2
2689907:4 | Untergeschoss | 0 | 10.9819 | 1.1153 | 0.223061 | 1.83032 | 0.185884 | 0.0371768 | Fundament OK | 0.2 | 0 | -0.2
2689907:5 | Untergeschoss | 0 | 10.9819 | 1.1153 | 0.223061 | 1.83032 | 0.185884 | 0.0371768 | Fundament OK | 0.2 | 0 | -0.2
2689907:6 | Untergeschoss | 0 | 10.9819 | 1.1153 | 0.223061 | 1.83032 | 0.185884 | 0.0371768 | Fundament OK | 0.2 | 0 | -0.2
2690997 | Untergeschoss | 11.3 | 16.2958 | 7.0368 | 1.40736 | 16.58 | 7.0368 | 1.43518 | Untergeschoss | 0.084375 | Bemaßungen - Neigung: 0.19982
2706644 | Erdgeschoss | 0 | 38.32 | 42.976 | 8.5952 | 38.0983 | 41.362 | 8.2724 | Erdgeschoss | -0.149213 | 2.45079 | 2.25079

# IfcSlab: Geschossdecke:Geschossdecke 150 + 50, Geschossdecke:Geschossdecke 150 + 50:2538128
In: Untergeschoss
Type - PredefinedType: FLOOR; Material: Fußboden - Parkett Roteiche 0.05 m, Ortbeton - bewehrt 0.1 m, Dämmung - hart 0.05 m
Type - Andere - Kategorie: Geschossdecken; Familienname: Geschossdecke
Type - Konstruktion - Funktion: Innen; Standarddicke: 0.2 m
Type - Grafiken - Füllmuster für groben Maßstab: <Flächenfüllung>; Farbfüllung für groben Maßstab: 32768
Type - ID-Daten - Beschreibung: STB_300; Typname: Geschossdecke 150 + 50
Type - Materialien und Oberflächen - Tragendes Material: Ortbeton - bewehrt
Type - Tragwerk - Filter Tragend / Nichttragend: yes
Type - Analytische Eigenschaften - Absorptionsgrad: 0.1; Rauigkeit: 1; Thermischer Widerstand (R): 1.94745 s3*K/kg; Thermisch wirksame Masse: 153682 kg/s2/K; Wärmedurchgangskoeffizient (U): 0.513491 kg/s3/K
Type - Pset_SlabCommon - ThermalTransmittance: 0.513491 kg/s3/K
Pset_QuantityTakeOff - Reference: Geschossdecke 150 + 50; sets with these values: 2
Pset_SlabCommon - IsExternal: no; LoadBearing: no; Reference: Geschossdecke 150 + 50; PitchAngle: 0 deg
AVA - GESCHOSSDECKENLISTE - Typ: Geschossdecke 150 + 50; Umfang: 44.3518 m; Fläche: 85.8592 m2; Volumen: 17.1718 m3
ING - GESCHOSSDECKENLISTE - Typ: Geschossdecke 150 + 50; Material: Ortbeton - bewehrt; Umfang: 44.3518 m; Fläche: 85.8592 m2; Volumen: 17.1718 m3
BaseQuantities - Perimeter: 44.3518 m; GrossArea: 85.8592 m2; NetArea: 85.8592 m2; GrossVolume: 17.1718 m3; NetVolume: 17.1718 m3
Andere - Familie: Geschossdecke; Familie und Typ: Geschossdecke: Geschossdecke 150 + 50; Typ: Geschossdecke 150 + 50; Typ-ID: 2711870
Abhängigkeiten - Abhängig von Körper: no; Raumbegrenzung: yes; Ebene: Untergeschoss; Höhenversatz von Ebene: 0 m
Bemaßungen - Dicke: 0.2 m; Fläche: 85.8592 m2; Höhe oben: 0 m; Höhe oben Kern: 0 m; Höhe unten: -0.2 m; Höhe unten Kern: -0.15 m; Umfang: 44.3518 m; Volumen: 17.1718 m3
ID-Daten - Hat Verknüpfung: no
Phasen - Phase erstellt: Phase 01
Tragwerk - Tragwerk: no

# IfcSlab: Geschossdecke:Geschossdecke 200 + 50 (2)
In: Erdgeschoss
Type - PredefinedType: FLOOR; Material: Fußboden - Parkett Roteiche 0.05 m, Ortbeton - bewehrt 0.2 m
Type - Andere - Kategorie: Geschossdecken; Familienname: Geschossdecke
Type - Konstruktion - Funktion: Innen; Standarddicke: 0.25 m
Type - Grafiken - Füllmuster für groben Maßstab: <Flächenfüllung>; Farbfüllung für groben Maßstab: 32768
Type - ID-Daten - Beschreibung: STB_300; Typname: Geschossdecke 200 + 50
Type - Materialien und Oberflächen - Tragendes Material: Ortbeton - bewehrt
Type - Tragwerk - Filter Tragend / Nichttragend: yes
Type - Analytische Eigenschaften - Absorptionsgrad: 0.1; Rauigkeit: 1; Thermischer Widerstand (R): 0.191205 s3*K/kg; Thermisch wirksame Masse: 302220 kg/s2/K; Wärmedurchgangskoeffizient (U): 5.23 kg/s3/K
Type - Pset_SlabCommon - ThermalTransmittance: 5.23 kg/s3/K
Pset_QuantityTakeOff - Reference: Geschossdecke 200 + 50; sets with these values: 2
Pset_SlabCommon - IsExternal: no; LoadBearing: no; PitchAngle: 0 deg; Reference: Geschossdecke 200 + 50
AVA - GESCHOSSDECKENLISTE - Typ: Geschossdecke 200 + 50
ING - GESCHOSSDECKENLISTE - Typ: Geschossdecke 200 + 50; Material: Ortbeton - bewehrt
Andere - Familie: Geschossdecke; Familie und Typ: Geschossdecke: Geschossdecke 200 + 50; Typ: Geschossdecke 200 + 50; Typ-ID: 712247
Abhängigkeiten - Abhängig von Körper: no; Raumbegrenzung: yes; Ebene: Erdgeschoss
Bemaßungen - Dicke: 0.25 m
ID-Daten - Hat Verknüpfung: no
Phasen - Phase erstellt: Phase 01
Tragwerk - Tragwerk: no
Name (Geschossdecke:Geschossdecke 200 + 50:...) | AVA - GESCHOSSDECKENLISTE, Umfang (m) = ING - GESCHOSSDECKENLISTE, Umfang (m) = Bemaßungen, Umfang (m) | AVA - GESCHOSSDECKENLISTE, Fläche (m2) = ING - GESCHOSSDECKENLISTE, Fläche (m2) = NetArea (m2) = Bemaßungen, Fläche (m2) | AVA - GESCHOSSDECKENLISTE, Volumen (m3) = ING - GESCHOSSDECKENLISTE, Volumen (m3) = NetVolume (m3) = Bemaßungen, Volumen (m3) | Perimeter (m) | GrossArea (m2) | GrossVolume (m3) | Höhenversatz von Ebene (m) | Höhe oben (m) = Höhe oben Kern (m) | Höhe unten (m) = Höhe unten Kern (m)
2542265 | 64.2177 | 112.069 | 28.0172 | 47.2518 | 119.942 | 29.9855 | 0 | 2.6 | 2.35
2545365 | 64.8677 | 103.593 | 25.8982 | 54.9677 | 108.863 | 27.2157 | 2.8 | 5.4 | 5.15

# IfcSlab: Geschossdecke:Geschossdecke 200 + 50 Bad (3)
Type - PredefinedType: FLOOR; Material: Fußboden - Fliese Travertin 500 x 500 0.05 m, Ortbeton - bewehrt 0.2 m
Type - Andere - Kategorie: Geschossdecken; Familienname: Geschossdecke
Type - Konstruktion - Funktion: Innen; Standarddicke: 0.25 m
Type - Grafiken - Füllmuster für groben Maßstab: <Flächenfüllung>; Farbfüllung für groben Maßstab: 32768
Type - ID-Daten - Beschreibung: STB_300; Typname: Geschossdecke 200 + 50 Bad
Type - Materialien und Oberflächen - Tragendes Material: Ortbeton - bewehrt
Type - Tragwerk - Filter Tragend / Nichttragend: yes
Type - Analytische Eigenschaften - Absorptionsgrad: 0.1; Rauigkeit: 1; Thermischer Widerstand (R): 0.191205 s3*K/kg; Thermisch wirksame Masse: 302220 kg/s2/K; Wärmedurchgangskoeffizient (U): 5.23 kg/s3/K
Type - Pset_SlabCommon - ThermalTransmittance: 5.23 kg/s3/K
Pset_QuantityTakeOff - Reference: Geschossdecke 200 + 50 Bad; sets with these values: 2
Pset_SlabCommon - IsExternal: no; LoadBearing: no; PitchAngle: 0 deg; Reference: Geschossdecke 200 + 50 Bad
AVA - GESCHOSSDECKENLISTE - Typ: Geschossdecke 200 + 50 Bad
ING - GESCHOSSDECKENLISTE - Typ: Geschossdecke 200 + 50 Bad; Material: Ortbeton - bewehrt
Andere - Familie: Geschossdecke; Familie und Typ: Geschossdecke: Geschossdecke 200 + 50 Bad; Typ: Geschossdecke 200 + 50 Bad; Typ-ID: 2804732
Abhängigkeiten - Abhängig von Körper: no; Raumbegrenzung: yes; Höhenversatz von Ebene: 0 m
Bemaßungen - Dicke: 0.25 m
ID-Daten - Hat Verknüpfung: no
Phasen - Phase erstellt: Phase 01
Tragwerk - Tragwerk: no
Name (Geschossdecke:Geschossdecke 200 + 50 Bad:...) | In | AVA - GESCHOSSDECKENLISTE, Umfang (m) = ING - GESCHOSSDECKENLISTE, Umfang (m) = Perimeter (m) = Bemaßungen, Umfang (m) | AVA - GESCHOSSDECKENLISTE, Fläche (m2) = ING - GESCHOSSDECKENLISTE, Fläche (m2) = GrossArea (m2) = NetArea (m2) = Bemaßungen, Fläche (m2) | AVA - GESCHOSSDECKENLISTE, Volumen (m3) = ING - GESCHOSSDECKENLISTE, Volumen (m3) = GrossVolume (m3) = NetVolume (m3) = Bemaßungen, Volumen (m3) | Width (m) | Ebene | Höhe oben (m) = Höhe oben Kern (m) | Höhe unten (m) = Höhe unten Kern (m)
2804730 | 1. Obergeschoss | 9.9 | 5.27 | 1.3175 | 3.4 | 1. Obergeschoss | 5.4 | 5.15
2806546 | Erdgeschoss | 9.06593 | 5.03678 | 1.2592 | 2.58297 | Erdgeschoss | 2.6 | 2.35
2807044 | Untergeschoss | 17.8859 | 19.9794 | 4.99485 | 4.59297 | Untergeschoss | 0 | -0.25

# IfcSlab: Geschossdecke:STB & Granite 120, Geschossdecke:STB & Granite 120:2663823
In: Erdgeschoss
Type - PredefinedType: FLOOR; Material: Fußboden - Granit grau 500 x 500 0.04 m, Ortbeton - bewehrt 0.08 m
Type - Andere - Kategorie: Geschossdecken; Familienname: Geschossdecke
Type - Konstruktion - Funktion: Innen; Standarddicke: 0.12 m
Type - Grafiken - Füllmuster für groben Maßstab: <Flächenfüllung>; Farbfüllung für groben Maßstab: 32768
Type - ID-Daten - Beschreibung: STB_250; Typname: STB & Granite 120
Type - Materialien und Oberflächen - Tragendes Material: Ortbeton - bewehrt
Type - Tragwerk - Filter Tragend / Nichttragend: yes
Type - Analytische Eigenschaften - Absorptionsgrad: 0.1; Rauigkeit: 1; Thermischer Widerstand (R): 0.0764818 s3*K/kg; Thermisch wirksame Masse: 120888 kg/s2/K; Wärmedurchgangskoeffizient (U): 13.075 kg/s3/K
Type - Pset_SlabCommon - ThermalTransmittance: 13.075 kg/s3/K
Pset_QuantityTakeOff - Reference: STB & Granite 120; sets with these values: 2
Pset_SlabCommon - IsExternal: no; LoadBearing: no; PitchAngle: 1.2 deg; Reference: STB & Granite 120
AVA - GESCHOSSDECKENLISTE - Typ: STB & Granite 120; Umfang: 20.6566 m; Fläche: 14.3993 m2; Volumen: 1.72792 m3
ING - GESCHOSSDECKENLISTE - Typ: STB & Granite 120; Material: Ortbeton - bewehrt; Umfang: 20.6566 m; Fläche: 14.3993 m2; Volumen: 1.72792 m3
BaseQuantities - Perimeter: 20.6575 m; GrossArea: 14.3993 m2; NetArea: 14.3993 m2; GrossVolume: 1.7283 m3; NetVolume: 1.72792 m3
Andere - Familie: Geschossdecke; Familie und Typ: Geschossdecke: STB & Granite 120; Typ: STB & Granite 120; Typ-ID: 712246
Abhängigkeiten - Abhängig von Körper: no; Raumbegrenzung: yes; Ebene: Erdgeschoss; Höhenversatz von Ebene: -0.036732 m
Bemaßungen - Dicke: 0.12 m; Fläche: 14.3993 m2; Neigung: 0.020947; Umfang: 20.6566 m; Volumen: 1.72792 m3
ID-Daten - Hat Verknüpfung: no
Phasen - Phase erstellt: Phase 01
Tragwerk - Tragwerk: no

# IfcSlab: Geschossdecke:STB 100 (3)
In: Untergeschoss
Type - PredefinedType: FLOOR; Material: Ortbeton - bewehrt 0.1 m
Type - Andere - Kategorie: Geschossdecken; Familienname: Geschossdecke
Type - Konstruktion - Funktion: Innen; Standarddicke: 0.1 m
Type - Grafiken - Füllmuster für groben Maßstab: <Flächenfüllung>; Farbfüllung für groben Maßstab: 32768
Type - ID-Daten - Bauelement: 50.A9; Beschreibung: STB_200; Typname: STB 100
Type - Materialien und Oberflächen - Tragendes Material: Ortbeton - bewehrt
Type - Tragwerk - Filter Tragend / Nichttragend: yes
Type - Analytische Eigenschaften - Absorptionsgrad: 0.1; Rauigkeit: 1; Thermischer Widerstand (R): 0.0956023 s3*K/kg; Thermisch wirksame Masse: 151110 kg/s2/K; Wärmedurchgangskoeffizient (U): 10.46 kg/s3/K
Type - Pset_SlabCommon - ThermalTransmittance: 10.46 kg/s3/K
Pset_QuantityTakeOff - Reference: STB 100; sets with these values: 2
Pset_SlabCommon - IsExternal: no; LoadBearing: no; PitchAngle: 0 deg; Reference: STB 100
AVA - GESCHOSSDECKENLISTE - Typ: STB 100; Umfang: 3.28 m; Fläche: 0.496 m2; Volumen: 0.0496 m3
ING - GESCHOSSDECKENLISTE - Typ: STB 100; Material: Ortbeton - bewehrt; Umfang: 3.28 m; Fläche: 0.496 m2; Volumen: 0.0496 m3
BaseQuantities - Width: 0.4 m; Perimeter: 3.28 m; GrossArea: 0.496 m2; NetArea: 0.496 m2; GrossVolume: 0.0496 m3; NetVolume: 0.0496 m3
Andere - Familie: Geschossdecke; Typ: STB 100; Familie und Typ: Geschossdecke: STB 100; Typ-ID: 2705334
Abhängigkeiten - Abhängig von Körper: no; Raumbegrenzung: yes; Ebene: Schacht UK; Höhenversatz von Ebene: 0.1 m
Bemaßungen - Dicke: 0.1 m; Fläche: 0.496 m2; Höhe oben: 1.83496 m; Höhe oben Kern: 1.83496 m; Höhe unten: 1.73496 m; Höhe unten Kern: 1.73496 m; Umfang: 3.28 m; Volumen: 0.0496 m3
ID-Daten - Hat Verknüpfung: no
Phasen - Phase erstellt: Phase 01
Tragwerk - Tragwerk: no
Name (Geschossdecke:STB 100:...)
2705304
2706568
2706609

# IfcSlab: Geschossdecke:STB 140, Geschossdecke:STB 140:2662547
In: Untergeschoss
Type - PredefinedType: FLOOR; Material: Ortbeton - bewehrt 0.14 m
Type - Andere - Kategorie: Geschossdecken; Familienname: Geschossdecke
Type - Konstruktion - Funktion: Innen; Standarddicke: 0.14 m
Type - Grafiken - Füllmuster für groben Maßstab: <Flächenfüllung>; Farbfüllung für groben Maßstab: 32768
Type - ID-Daten - Beschreibung: STB_250; Typname: STB 140
Type - Materialien und Oberflächen - Tragendes Material: Ortbeton - bewehrt
Type - Tragwerk - Filter Tragend / Nichttragend: yes
Type - Analytische Eigenschaften - Absorptionsgrad: 0.1; Rauigkeit: 1; Thermischer Widerstand (R): 0.133843 s3*K/kg; Thermisch wirksame Masse: 211554 kg/s2/K; Wärmedurchgangskoeffizient (U): 7.47143 kg/s3/K
Type - Pset_SlabCommon - ThermalTransmittance: 7.47143 kg/s3/K
Pset_QuantityTakeOff - Reference: STB 140; sets with these values: 2
Pset_SlabCommon - IsExternal: no; LoadBearing: no; Reference: STB 140; PitchAngle: 1.2 deg
AVA - GESCHOSSDECKENLISTE - Typ: STB 140; Umfang: 18.8871 m; Fläche: 13.0645 m2; Volumen: 1.59866 m3
ING - GESCHOSSDECKENLISTE - Typ: STB 140; Material: Ortbeton - bewehrt; Umfang: 18.8871 m; Fläche: 13.0645 m2; Volumen: 1.59866 m3
BaseQuantities - Perimeter: 3.61224 m; GrossArea: 0.206013 m2; NetArea: 13.0645 m2; GrossVolume: 1.59866 m3; NetVolume: 1.59866 m3
Andere - Familie: Geschossdecke; Familie und Typ: Geschossdecke: STB 140; Typ: STB 140; Typ-ID: 2662570
Abhängigkeiten - Abhängig von Körper: no; Raumbegrenzung: yes; Ebene: Balkon UK; Höhenversatz von Ebene: 0.164974 m
Bemaßungen - Dicke: 0.14 m; Fläche: 13.0645 m2; Höhe oben Kern: 2.47997 m; Höhe unten: 2.33997 m; Höhe unten Kern: 2.33997 m; Umfang: 18.8871 m; Volumen: 1.59866 m3
ID-Daten - Hat Verknüpfung: no
Phasen - Phase erstellt: Phase 01
Tragwerk - Tragwerk: no

# IfcSlab: Geschossdecke:STB 160, Geschossdecke:STB 160:2708547
In: Erdgeschoss
Type - PredefinedType: FLOOR
Type - Andere - Kategorie: Geschossdecken; Familienname: Geschossdecke
Type - Konstruktion - Funktion: Innen; Standarddicke: 0.16 m
Type - Grafiken - Füllmuster für groben Maßstab: <Flächenfüllung>; Farbfüllung für groben Maßstab: 32768
Type - ID-Daten - Beschreibung: STB_250; Typname: STB 160
Type - Materialien und Oberflächen - Tragendes Material: Ortbeton - bewehrt
Type - Tragwerk - Filter Tragend / Nichttragend: yes
Type - Analytische Eigenschaften - Absorptionsgrad: 0.1; Rauigkeit: 1; Thermischer Widerstand (R): 0.152964 s3*K/kg; Thermisch wirksame Masse: 241776 kg/s2/K; Wärmedurchgangskoeffizient (U): 6.5375 kg/s3/K
Type - Pset_SlabCommon - ThermalTransmittance: 6.5375 kg/s3/K
Material: Ortbeton - bewehrt
Pset_QuantityTakeOff - Reference: STB 160; sets with these values: 2
Pset_SlabCommon - IsExternal: no; LoadBearing: no; PitchAngle: 0 deg; Reference: STB 160
AVA - GESCHOSSDECKENLISTE - Typ: STB 160; Umfang: 4.072 m; Fläche: 1.04302 m2; Volumen: 0.120165 m3
ING - GESCHOSSDECKENLISTE - Typ: STB 160; Material: Ortbeton - bewehrt; Umfang: 4.072 m; Fläche: 1.04302 m2; Volumen: 0.120165 m3
BaseQuantities - GrossArea: 1.04302 m2; NetArea: 1.04302 m2; NetVolume: 0.120165 m3
Andere - Familie: Geschossdecke; Familie und Typ: Geschossdecke: STB 160; Typ: STB 160; Typ-ID: 2710377
Abhängigkeiten - Abhängig von Körper: no; Raumbegrenzung: yes; Ebene: Erdgeschoss; Höhenversatz von Ebene: 0.0107869 m
Bemaßungen - Dicke: 0.16 m; Fläche: 1.04302 m2; Höhe oben: 2.61079 m; Höhe oben Kern: 2.61079 m; Höhe unten: 2.45079 m; Höhe unten Kern: 2.45079 m; Umfang: 4.072 m; Volumen: 0.120165 m3
ID-Daten - Hat Verknüpfung: no
Phasen - Phase erstellt: Phase 01
Tragwerk - Tragwerk: no

# IfcStair: Betonfertigteil-Treppe:Fertigbetontreppe - 1 Stockwerkstrennlinie (2)
In: Untergeschoss
Type - Andere - Kategorie: Treppen; Familienname: Betonfertigteil-Treppe
Type - Konstruktion - Funktion: Außen; Podesttyp: Podest 180; Lauftyp: Naturstein - Auftritt 40 / Trittüberstand 30
Type - Grafiken - Schnittmarkierungstyp: Unterster Treppenlauf
Type - ID-Daten - Typname: Fertigbetontreppe - 1 Stockwerkstrennlinie
Type - Berechnungsregeln - Maximale Stufenhöhe: 0.2 m; Mindestauftrittsbreite: 0.2 m; Mindestlaufbreite: 1 m
Type - Endverbindung - Abstand horizontale Lücke: 0.01 m; Abstand vertikale Lücke: 0.01 m; Ausklinkung Dicke: 0.1 m; Ausklinkung Verlängerung: 0.1 m; Verbindungsmethode: Ausklinkung
Type - Auflager - Auflager links: Keine; Auflager Mitte: no; Auflager Mitte - Anzahl: 0; Auflager rechts: Keine; Seitlicher Versatz links: 0 m; Seitlicher Versatz rechts: 0 m
ShapeType: STRAIGHT_RUN_STAIR
Pset_QuantityTakeOff - Reference: Fertigbetontreppe - 1 Stockwerkstrennlinie
Pset_StairCommon - IsExternal: yes; Reference: Fertigbetontreppe - 1 Stockwerkstrennlinie
AVA - TREPPENLISTE - Typ: Fertigbetontreppe - 1 Stockwerkstrennlinie
Andere - Familie: Betonfertigteil-Treppe; Familie und Typ: Betonfertigteil-Treppe: Fertigbetontreppe - 1 Stockwerkstrennlinie; Typ: Fertigbetontreppe - 1 Stockwerkstrennlinie; Typ-ID: 770245
Bemaßungen - Nummer erster Auftritt/Steigung: 1
Phasen - Phase erstellt: Phase 01
Tragwerk - Betonüberdeckung: c=2.0cm <2,0 cm>
Name (Betonfertigteil-Treppe:Treppe:...) | NumberOfRiser = Tatsächliche Anzahl an Steigungen | NumberOfTreads = Gewünschte Anzahl Steigungen | RiserHeight (m) = Tatsächliche Stufenhöhe (m) | TreadLength (m) = Tatsächliche Auftrittsbreite (m) | AVA - TREPPENLISTE, Basisebene = Abhängigkeiten, Basisebene | AVA - TREPPENLISTE, Oberste Ebene = Abhängigkeiten, Oberste Ebene | Steigungsverhältnis | Versatz unten (m) | Gewünschte Treppenhöhe (m) | Versatz oben (m)
2695865 | 3 | 2 | 0.19205 | 0.2509 | Untergeschoss | Balkon UK | 3 x 0,192 m x 0,251 m | 0 | 0.3841 | -1.9309
2710850 | 5 | 4 | 0.156635 | 0.32173 | Schacht UK | Erdgeschoss | 5 x 0,157 m x 0,322 m | 0.0851 | 0.626539 | -0.1534

# IfcStair: Ortbetontreppe:Massiv - Stufen Naturstein - 1 Stockwerkstrennlinie, Ortbetontreppe:Treppe:2569920
In: Untergeschoss
Type - Andere - Kategorie: Treppen; Familienname: Ortbetontreppe
Type - Konstruktion - Funktion: Innen; Lauftyp: Naturstein - Auftritt 20 / Steigung 20; Podesttyp: Podest 180
Type - Grafiken - Schnittmarkierungstyp: Unterster Treppenlauf
Type - ID-Daten - Typname: Massiv - Stufen Naturstein - 1 Stockwerkstrennlinie
Type - Berechnungsregeln - Maximale Stufenhöhe: 0.2 m; Mindestauftrittsbreite: 0.2 m; Mindestlaufbreite: 0.82 m
Type - Auflager - Auflager links: Keine; Auflager Mitte: no; Auflager Mitte - Anzahl: 0; Auflager rechts: Keine; Seitlicher Versatz links: 0 m; Seitlicher Versatz rechts: 0 m
Pset_QuantityTakeOff - Reference: Massiv - Stufen Naturstein - 1 Stockwerkstrennlinie
Pset_StairCommon - IsExternal: no; Reference: Massiv - Stufen Naturstein - 1 Stockwerkstrennlinie; NumberOfRiser: 16; NumberOfTreads: 16; RiserHeight: 0.1625 m; TreadLength: 0.2058 m
AVA - TREPPENLISTE - Typ: Massiv - Stufen Naturstein - 1 Stockwerkstrennlinie; Basisebene: Untergeschoss; Steigungsverhältnis: 16 x 0,163 m x 0,206 m
Andere - Familie: Ortbetontreppe; Familie und Typ: Ortbetontreppe: Massiv - Stufen Naturstein - 1 Stockwerkstrennlinie; Typ: Massiv - Stufen Naturstein - 1 Stockwerkstrennlinie; Typ-ID: 770244
Abhängigkeiten - Versatz oben: 0 m; Versatz unten: 0 m; Basisebene: Untergeschoss; Gewünschte Treppenhöhe: 2.6 m
Bemaßungen - Gewünschte Anzahl Steigungen: 16; Nummer erster Auftritt/Steigung: 1; Tatsächliche Anzahl an Steigungen: 16; Tatsächliche Auftrittsbreite: 0.2058 m; Tatsächliche Stufenhöhe: 0.1625 m
Phasen - Phase erstellt: Phase 01
Tragwerk - Betonüberdeckung: c=2.0cm <2,0 cm>

# IfcStair: Zusammengebaute Treppe:Wangen Stahl - Stufen Holz - 1 Stockwerkstrennlinie (2)
Type - Andere - Kategorie: Treppen; Familienname: Zusammengebaute Treppe
Type - Konstruktion - Funktion: Innen; Lauftyp: Holz_40 mm Auftritt; Podesttyp: Podest (nicht massiv)
Type - Grafiken - Schnittmarkierungstyp: Unterster Treppenlauf
Type - ID-Daten - Typname: Wangen Stahl - Stufen Holz - 1 Stockwerkstrennlinie
Type - Berechnungsregeln - Maximale Stufenhöhe: 0.2 m; Mindestauftrittsbreite: 0.24 m; Mindestlaufbreite: 1 m
Type - Auflager - Auflager Mitte: no; Auflager Mitte - Anzahl: 0; Seitlicher Versatz links: 0 m; Seitlicher Versatz rechts: 0 m; Auflager links: Wangentreppe (eingestemmt); Auflager rechts: Wangentreppe (eingestemmt); Auflagertyp links: Metall 10 x 260; Auflagertyp rechts: Metall 10 x 260
Pset_QuantityTakeOff - Reference: Wangen Stahl - Stufen Holz - 1 Stockwerkstrennlinie
Pset_StairCommon - IsExternal: no; Reference: Wangen Stahl - Stufen Holz - 1 Stockwerkstrennlinie
AVA - TREPPENLISTE - Typ: Wangen Stahl - Stufen Holz - 1 Stockwerkstrennlinie
Andere - Familie: Zusammengebaute Treppe; Familie und Typ: Zusammengebaute Treppe: Wangen Stahl - Stufen Holz - 1 Stockwerkstrennlinie; Typ: Wangen Stahl - Stufen Holz - 1 Stockwerkstrennlinie; Typ-ID: 770258
Abhängigkeiten - Versatz oben: 0 m
Bemaßungen - Nummer erster Auftritt/Steigung: 1
Phasen - Phase erstellt: Phase 01
Name (Zusammengebaute Treppe:Treppe:...) | In | NumberOfRiser = Gewünschte Anzahl Steigungen = Tatsächliche Anzahl an Steigungen | NumberOfTreads | RiserHeight (m) = Tatsächliche Stufenhöhe (m) | TreadLength (m) = Tatsächliche Auftrittsbreite (m) | AVA - TREPPENLISTE, Basisebene = Abhängigkeiten, Basisebene | Steigungsverhältnis | Versatz unten (m) | Gewünschte Treppenhöhe (m)
2594539 | Erdgeschoss | 12 | 11 | 0.205417 | 0.24 | Erdgeschoss | 12 x 0,205 m x 0,240 m | 0 | 2.465
2595612 | 1. Obergeschoss | 2 | 1 | 0.0875 | 0.46 | 1. Obergeschoss | 2 x 0,088 m x 0,460 m | -0.2975 | 0.175 | ShapeType: STRAIGHT_RUN_STAIR

# IfcStairFlight: Massivtreppenlauf:Naturstein - Auftritt 20 / Steigung 20, Ortbetontreppe:Treppe:2569920 Run 1
In: Untergeschoss
Type - PredefinedType: WINDER
Type - Andere - Kategorie: Treppen: Läufe; Familienname: Massivtreppenlauf
Type - Konstruktion - Konstruktionstiefe: 0.13 m; Oberfläche von Unterseite: Glatt
Type - ID-Daten - Typenkommentare: Naturstein_Auftritt + Steigung_40+20; Typname: Naturstein - Auftritt 20 / Steigung 20
Type - Materialien und Oberflächen - Auftrittsmaterial: Fußboden - Granit grau 500 x 500; Material Massivtreppe: Ortbeton - bewehrt Verputzt; Steigungsmaterial: Fußboden - Granit grau 500 x 500
Type - Steigungen - Geneigt: no; Steigung: yes; Steigungsdicke: 0.02 m; Verbindung Steigung zu Auftritt: Auftritt unter Steigung erweitern
Type - Auftritte - Auftritt: yes; Auftrittshöhe: 0.02 m; Trittüberstandprofil anwenden: Nur vorn; Trittüberstandslänge: 0 m
NumberOfRiser: 16; NumberOfTreads: 16; RiserHeight: 0.533136 m; TreadLength: 0.675197 m; Material: Fußboden - Granit grau 500 x 500, Ortbeton - bewehrt Verputzt
Pset_QuantityTakeOff - Reference: Naturstein - Auftritt 20 / Steigung 20
Pset_StairFlightCommon - Reference: Naturstein - Auftritt 20 / Steigung 20; NumberOfRiser: 16; NumberOfTreads: 16; RiserHeight: 0.1625 m; TreadLength: 0.2058 m; NosingLength: 0 m; WalkingLineOffset: 1.34514 m; TreadLengthAtOffset: 0.2058 m; TreadLengthAtInnerSide: 0.2058 m
BaseQuantities - Length: 3.2993 m
Andere - Familie: Massivtreppenlauf; Familie und Typ: Massivtreppenlauf: Naturstein - Auftritt 20 / Steigung 20; Typ: Naturstein - Auftritt 20 / Steigung 20; Typ-ID: 769406
Abhängigkeiten - Basislinie: Lauf: rechts; Laufhöhe: 2.6 m; Relative Basishöhe: 0 m; Relative Höhe oben: 2.6 m
Konstruktion - Mit Steigung beginnen: yes; Mit Steigung enden: no; Unterhalb Steigungsbasis erweitern: 0 m
Bemaßungen - Tatsächliche Anzahl Auftritte: 16; Tatsächliche Anzahl Steigungen: 16; Tatsächliche Auftrittsbreite: 0.2058 m; Tatsächliche Laufbreite: 0.82 m; Tatsächliche Stufenhöhe: 0.1625 m
Phasen - Phase erstellt: Phase 01
Wendelstufen - Abrundungsradius: 0.18 m; Gehbereichsversatz innen: 0.12 m; Mindestbreite an Begrenzung innen: 0.072 m; Mindestbreite an Gehbereich innen: 0.2058 m; Parallele Stufen am Anfang: 2; Parallele Stufen am Ende: 2; Treppenknick abrunden: no; Verziehungsstil: Ausgeglichen

# IfcStairFlight: Massivtreppenlauf:Naturstein - Auftritt 40 / Trittüberstand 30 (2)
In: Untergeschoss
Type - Andere - Kategorie: Treppen: Läufe; Familienname: Massivtreppenlauf
Type - Konstruktion - Oberfläche von Unterseite: Glatt; Konstruktionstiefe: 0.1925 m
Type - ID-Daten - Typenkommentare: Naturstein_Auftritt + Trittüberstand_40+30; Typname: Naturstein - Auftritt 40 / Trittüberstand 30
Type - Materialien und Oberflächen - Auftrittsmaterial: Betonfertigteil - mit Dämmeigenschaften; Material Massivtreppe: Betonfertigteil - mit Dämmeigenschaften
Type - Steigungen - Geneigt: no; Steigung: no; Steigungsdicke: 0 m; Verbindung Steigung zu Auftritt: Steigung hinter Auftritt erweitern
Type - Auftritte - Trittüberstandprofil anwenden: Nur vorn; Trittüberstandslänge: 0 m; Auftritt: no; Auftrittshöhe: 0 m
Material: Betonfertigteil - mit Dämmeigenschaften
Pset_QuantityTakeOff - Reference: Naturstein - Auftritt 40 / Trittüberstand 30
Pset_StairFlightCommon - NosingLength: 0 m; Reference: Naturstein - Auftritt 40 / Trittüberstand 30
Andere - Familie: Massivtreppenlauf; Familie und Typ: Massivtreppenlauf: Naturstein - Auftritt 40 / Trittüberstand 30; Typ: Naturstein - Auftritt 40 / Trittüberstand 30; Typ-ID: 769403
Abhängigkeiten - Relative Basishöhe: 0 m
Konstruktion - Mit Steigung beginnen: yes; Unterhalb Steigungsbasis erweitern: 0 m; Mit Steigung enden: yes
Phasen - Phase erstellt: Phase 01
Name (Betonfertigteil-Treppe:Treppe:...) | NumberOfRiser = Pset_StairFlightCommon, NumberOfRiser = Tatsächliche Anzahl Steigungen | NumberOfTreads = Pset_StairFlightCommon, NumberOfTreads = Tatsächliche Anzahl Auftritte | RiserHeight (m) | TreadLength (m) | Pset_StairFlightCommon, RiserHeight (m) = Tatsächliche Stufenhöhe (m) | Pset_StairFlightCommon, TreadLength (m) = TreadLengthAtOffset (m) = TreadLengthAtInnerSide (m) | Length (m) | Laufhöhe (m) = Relative Höhe oben (m)
2695865 Run 1 | 3 | 2 | 0.630085 | 0.823163 | 0.19205 | 0.2509 | 0.708369 | 0.57615
2710850 Run 1 | 5 | 4 | 0.513894 | 1.05555 | 0.156635 | 0.32173 | 1.19373 | 0.783174

# IfcStairFlight: Treppenlauf (nicht massiv):Holz_40 mm Auftritt (2)
Type - Andere - Kategorie: Treppen: Läufe; Familienname: Treppenlauf (nicht massiv)
Type - ID-Daten - Typname: Holz_40 mm Auftritt
Type - Materialien und Oberflächen - Auftrittsmaterial: Holz - generisch 140-100-70
Type - Steigungen - Geneigt: no; Steigung: no; Steigungsdicke: 0 m; Verbindung Steigung zu Auftritt: Steigung hinter Auftritt erweitern
Type - Auftritte - Auftritt: yes; Trittüberstandprofil anwenden: Nur vorn; Auftrittshöhe: 0.04 m; Trittüberstandslänge: 0.03 m
Material: Holz - generisch 140-100-70
Pset_QuantityTakeOff - Reference: Holz_40 mm Auftritt
Pset_StairFlightCommon - Reference: Holz_40 mm Auftritt; NosingLength: 0.03 m
Andere - Familie: Treppenlauf (nicht massiv); Familie und Typ: Treppenlauf (nicht massiv): Holz_40 mm Auftritt; Typ: Holz_40 mm Auftritt; Typ-ID: 770249
Abhängigkeiten - Relative Basishöhe: 0 m
Konstruktion - Mit Steigung beginnen: yes; Mit Steigung enden: yes
Phasen - Phase erstellt: Phase 01
Name (Zusammengebaute Treppe:Treppe:...) | In | NumberOfRiser = Pset_StairFlightCommon, NumberOfRiser = Tatsächliche Anzahl Steigungen | NumberOfTreads = Pset_StairFlightCommon, NumberOfTreads = Tatsächliche Anzahl Auftritte | RiserHeight (m) | TreadLength (m) | Pset_StairFlightCommon, RiserHeight (m) = Tatsächliche Stufenhöhe (m) | Pset_StairFlightCommon, TreadLength (m) = TreadLengthAtOffset (m) = TreadLengthAtInnerSide (m) | Length (m) | Laufhöhe (m) = Relative Höhe oben (m) | Unterhalb Steigungsbasis erweitern (m)
2594539 Run 1 | Erdgeschoss | 12 | 11 | 0.673939 | 0.787402 | 0.205417 | 0.24 | 3.17797 | 2.465 | 0
2595612 Run 1 | 1. Obergeschoss | 2 | 1 | 0.287073 | 1.50919 | 0.0875 | 0.46 | 0.26 | 0.175 | -2

# IfcWall: Basiswand:1OG Wand 30, Basiswand:1OG Wand 30:2778598
In: 1. Obergeschoss
Type - PredefinedType: STANDARD; Material: Trockenbau - Gipsplatte 0.03 m
Type - Andere - Kategorie: Wände; Familienname: Basiswand
Type - Konstruktion - Abschluss an Öffnungen: Keine; Funktion: Außen; Abschluss an Wänden: Keine; Breite: 0.03 m
Type - Grafiken - Füllmuster für groben Maßstab: <Flächenfüllung>; Farbfüllung für groben Maßstab: 32768
Type - ID-Daten - Beschreibung: STB_200; Typname: 1OG Wand 30
Type - Materialien und Oberflächen - Tragendes Material: Trockenbau - Gipsplatte
Type - Tragwerk - Filter Tragend / Nichttragend: yes
Type - Analytische Eigenschaften - Absorptionsgrad: 0.1; Rauigkeit: 1; Thermischer Widerstand (R): 0.0461538 s3*K/kg; Thermisch wirksame Masse: 27720 kg/s2/K; Wärmedurchgangskoeffizient (U): 21.6667 kg/s3/K
Type - Pset_WallCommon - ThermalTransmittance: 21.6667 kg/s3/K
Pset_QuantityTakeOff - Reference: 1OG Wand 30; sets with these values: 2
Pset_WallCommon - IsExternal: yes; ExtendToStructure: no; LoadBearing: no; Reference: 1OG Wand 30
AVA - WANDLISTE - Typ: 1OG Wand 30; Breite: 0.03 m; Fläche: 0.942179 m2; Volumen: 0.0272392 m3
ING - WANDLISTE - Typ: 1OG Wand 30; Material: Trockenbau - Gipsplatte; Breite: 0.03 m; Länge: 5.11 m; Fläche: 0.942179 m2; Volumen: 0.0272392 m3
BaseQuantities - Length: 5.11 m; NetVolume: 0.0272392 m3
Andere - Familie: Basiswand; Familie und Typ: Basiswand: 1OG Wand 30; Typ: 1OG Wand 30; Typ-ID: 2775443
Abhängigkeiten - Abhängig von Körper: no; Basislinie: Oberfläche: Außenkante; Oberkante ist fixiert.: no; Raumbegrenzung: yes; Unterkante ist fixiert: no; Verlängerungsabstand oben: 0 m; Verlängerungsabstand unten: 0 m; Abhängigkeit oben: Bis Ebene: 1OG OK; Abhängigkeit unten: Traufe; Nicht verknüpfte Höhe: 0.21531 m; Versatz oben: -0.675729 m; Versatz unten: 1.85896 m
Bemaßungen - Fläche: 0.942179 m2; Länge: 5.11 m; Volumen: 0.0272392 m3
Phasen - Phase erstellt: Phase 01
Tragwerk - Tragwerk: no; Tragwerksverwendung: Nichttragend
Querschnittsdefinition - Querschnitt: Vertikal

# IfcWall: Basiswand:Ziegel 200, Basiswand:Ziegel 200:2834218
In: 1. Obergeschoss
Type - PredefinedType: STANDARD; Material: Mauerwerk - Ziegel 0.2 m
Type - Andere - Kategorie: Wände; Familienname: Basiswand
Type - Konstruktion - Abschluss an Öffnungen: Keine; Abschluss an Wänden: Keine; Breite: 0.2 m; Funktion: Innen
Type - Grafiken - Füllmuster für groben Maßstab: <Flächenfüllung>; Farbfüllung für groben Maßstab: 255
Type - ID-Daten - Beschreibung: Ziegel_200; Typname: Ziegel 200
Type - Materialien und Oberflächen - Tragendes Material: Mauerwerk - Ziegel
Type - Tragwerk - Filter Tragend / Nichttragend: yes
Type - Analytische Eigenschaften - Absorptionsgrad: 0.1; Rauigkeit: 1; Thermischer Widerstand (R): 0.37037 s3*K/kg; Thermisch wirksame Masse: 260400 kg/s2/K; Wärmedurchgangskoeffizient (U): 2.7 kg/s3/K
Type - Pset_WallCommon - ThermalTransmittance: 2.7 kg/s3/K
Pset_QuantityTakeOff - Reference: Ziegel 200; sets with these values: 2
Pset_WallCommon - ExtendToStructure: no; Reference: Ziegel 200; IsExternal: no; LoadBearing: no
AVA - WANDLISTE - Typ: Ziegel 200; Breite: 0.2 m; Fläche: 5.04282 m2; Volumen: 0.979621 m3
ING - WANDLISTE - Typ: Ziegel 200; Material: Mauerwerk - Ziegel; Breite: 0.2 m; Länge: 3.03 m; Fläche: 5.04282 m2; Volumen: 0.979621 m3
BaseQuantities - Length: 3.03 m; NetVolume: 0.979621 m3
Andere - Familie: Basiswand; Familie und Typ: Basiswand: Ziegel 200; Typ: Ziegel 200; Typ-ID: 712263
Abhängigkeiten - Abhängig von Körper: no; Oberkante ist fixiert.: no; Raumbegrenzung: yes; Unterkante ist fixiert: no; Verlängerungsabstand oben: 0 m; Verlängerungsabstand unten: 0 m; Versatz oben: 0 m; Basislinie: Oberfläche: Innenkante; Abhängigkeit oben: Bis Ebene: 1OG OK; Abhängigkeit unten: Traufe; Nicht verknüpfte Höhe: 3 m; Versatz unten: -0.25 m
Bemaßungen - Fläche: 5.04282 m2; Länge: 3.03 m; Volumen: 0.979621 m3
Phasen - Phase erstellt: Phase 01
Tragwerk - Tragwerk: no; Tragwerksverwendung: Nichttragend
Querschnittsdefinition - Querschnitt: Vertikal

# IfcWall: Basiswand:Ziegel+WD hart 200+200, Basiswand:Ziegel+WD hart 200+200:2542777
In: Erdgeschoss
Type - PredefinedType: STANDARD; Material: Dämmung - hart 0.2 m, Mauerwerk - Ziegel 0.2 m
Type - Andere - Kategorie: Wände; Familienname: Basiswand
Type - Konstruktion - Abschluss an Öffnungen: Keine; Abschluss an Wänden: Außen; Funktion: Außen; Breite: 0.4 m
Type - Grafiken - Füllmuster für groben Maßstab: <Flächenfüllung>; Farbfüllung für groben Maßstab: 255
Type - ID-Daten - Beschreibung: Ziegel+WD_hart_200+200; Typname: Ziegel+WD hart 200+200
Type - Materialien und Oberflächen - Tragendes Material: Mauerwerk - Ziegel
Type - Tragwerk - Filter Tragend / Nichttragend: yes
Type - Analytische Eigenschaften - Absorptionsgrad: 0.1; Rauigkeit: 1; Thermischer Widerstand (R): 7.77778 s3*K/kg; Thermisch wirksame Masse: 270690 kg/s2/K; Wärmedurchgangskoeffizient (U): 0.128571 kg/s3/K
Type - Pset_WallCommon - ThermalTransmittance: 0.128571 kg/s3/K
Pset_QuantityTakeOff - Reference: Ziegel+WD hart 200+200; sets with these values: 2
Pset_WallCommon - IsExternal: yes; ExtendToStructure: no; LoadBearing: no; Reference: Ziegel+WD hart 200+200
AVA - WANDLISTE - Typ: Ziegel+WD hart 200+200; Breite: 0.4 m; Fläche: 31.5007 m2; Volumen: 11.4267 m3
ING - WANDLISTE - Typ: Ziegel+WD hart 200+200; Material: Mauerwerk - Ziegel; Breite: 0.4 m; Länge: 12.75 m; Fläche: 31.5007 m2; Volumen: 11.4267 m3
BaseQuantities - Length: 12.75 m; NetVolume: 11.4267 m3
Andere - Familie: Basiswand; Familie und Typ: Basiswand: Ziegel+WD hart 200+200; Typ: Ziegel+WD hart 200+200; Typ-ID: 712286
Abhängigkeiten - Abhängig von Körper: no; Basislinie: Oberfläche: Außenkante; Oberkante ist fixiert.: no; Raumbegrenzung: yes; Unterkante ist fixiert: no; Verlängerungsabstand oben: 0 m; Verlängerungsabstand unten: 0 m; Versatz oben: 0 m; Versatz unten: 0 m; Abhängigkeit oben: Bis Ebene: 1. Obergeschoss; Abhängigkeit unten: Erdgeschoss; Nicht verknüpfte Höhe: 2.8 m
Bemaßungen - Fläche: 31.5007 m2; Länge: 12.75 m; Volumen: 11.4267 m3
Phasen - Phase erstellt: Phase 01
Tragwerk - Tragwerk: no; Tragwerksverwendung: Nichttragend
Querschnittsdefinition - Querschnitt: Vertikal

# IfcWall: Basiswand:Ziegel+WD hart 300+250 (10)
Type - PredefinedType: STANDARD; Material: Dämmung - hart 0.25 m, Mauerwerk - Ziegel 0.3 m
Type - Andere - Kategorie: Wände; Familienname: Basiswand
Type - Konstruktion - Abschluss an Öffnungen: Keine; Abschluss an Wänden: Außen; Breite: 0.55 m; Funktion: Außen
Type - Grafiken - Farbfüllung für groben Maßstab: 255; Füllmuster für groben Maßstab: <Flächenfüllung>
Type - ID-Daten - Beschreibung: Ziegel+WD_hart_300+160; Typname: Ziegel+WD hart 300+250
Type - Materialien und Oberflächen - Tragendes Material: Mauerwerk - Ziegel
Type - Tragwerk - Filter Tragend / Nichttragend: yes
Type - Analytische Eigenschaften - Absorptionsgrad: 0.1; Rauigkeit: 1; Thermischer Widerstand (R): 9.81481 s3*K/kg; Thermisch wirksame Masse: 403462 kg/s2/K; Wärmedurchgangskoeffizient (U): 0.101887 kg/s3/K
Type - Pset_WallCommon - ThermalTransmittance: 0.101887 kg/s3/K
Pset_QuantityTakeOff - Reference: Ziegel+WD hart 300+250; sets with these values: 2
Pset_WallCommon - Reference: Ziegel+WD hart 300+250; IsExternal: yes
AVA - WANDLISTE - Typ: Ziegel+WD hart 300+250; Breite: 0.55 m
ING - WANDLISTE - Typ: Ziegel+WD hart 300+250; Material: Mauerwerk - Ziegel; Breite: 0.55 m
Andere - Familie: Basiswand; Familie und Typ: Basiswand: Ziegel+WD hart 300+250; Typ: Ziegel+WD hart 300+250; Typ-ID: 2519354
Abhängigkeiten - Abhängig von Körper: no; Basislinie: Oberfläche: Außenkante; Raumbegrenzung: yes; Unterkante ist fixiert: no; Verlängerungsabstand oben: 0 m; Verlängerungsabstand unten: 0 m; Versatz oben: 0 m; Versatz unten: 0 m
Phasen - Phase erstellt: Phase 01
Querschnittsdefinition - Querschnitt: Vertikal
Name (Basiswand:Ziegel+WD hart 300+250:...) | In | ExtendToStructure = Oberkante ist fixiert. | LoadBearing = Tragwerk | AVA - WANDLISTE, Fläche (m2) = ING - WANDLISTE, Fläche (m2) = Bemaßungen, Fläche (m2) | AVA - WANDLISTE, Volumen (m3) = ING - WANDLISTE, Volumen (m3) = NetVolume (m3) = Bemaßungen, Volumen (m3) | ING - WANDLISTE, Länge (m) = Length (m) = Bemaßungen, Länge (m) | Abhängigkeit unten | Nicht verknüpfte Höhe (m) | Tragwerksverwendung
2519990 | Untergeschoss | no | yes | 22.7492 | 11.0837 | 8.54 | Untergeschoss | 2.6 | Tragend | ID-Daten - Hat Verknüpfung: no; Tragwerk - Betonüberdeckung - Andere Flächen: c=2.0cm <2,0 cm>; Betonüberdeckung - Außenfläche: c=2.0cm <2,0 cm>; Betonüberdeckung - Innenfläche: c=2.0cm <2,0 cm>
2520192 | Untergeschoss | no | yes | 33.5058 | 16.6596 | 12.75 | Untergeschoss | 2.6 | Tragend | ID-Daten - Hat Verknüpfung: no; Tragwerk - Betonüberdeckung - Andere Flächen: c=2.0cm <2,0 cm>; Betonüberdeckung - Außenfläche: c=2.0cm <2,0 cm>; Betonüberdeckung - Innenfläche: c=2.0cm <2,0 cm>
2520270 | Untergeschoss | no | yes | 28.3549 | 14.028 | 10.5259 | Untergeschoss | 2.6 | Tragend | ID-Daten - Hat Verknüpfung: no; Tragwerk - Betonüberdeckung - Andere Flächen: c=2.0cm <2,0 cm>; Betonüberdeckung - Außenfläche: c=2.0cm <2,0 cm>; Betonüberdeckung - Innenfläche: c=2.0cm <2,0 cm>
2520373 | Untergeschoss | no | yes | 11.169 | 5.35355 | 4.76 | Untergeschoss | 2.6 | Tragend | ID-Daten - Hat Verknüpfung: no; Tragwerk - Betonüberdeckung - Andere Flächen: c=2.0cm <2,0 cm>; Betonüberdeckung - Außenfläche: c=2.0cm <2,0 cm>; Betonüberdeckung - Innenfläche: c=2.0cm <2,0 cm>
2520506 | Untergeschoss | no | yes | 5.08828 | 2.67212 | 1.98588 | Untergeschoss | 2.6 | Tragend | ID-Daten - Hat Verknüpfung: no; Tragwerk - Betonüberdeckung - Andere Flächen: c=2.0cm <2,0 cm>; Betonüberdeckung - Außenfläche: c=2.0cm <2,0 cm>; Betonüberdeckung - Innenfläche: c=2.0cm <2,0 cm>
2542412 | Erdgeschoss | no | no | 15.2982 | 7.70877 | 7.99 | Erdgeschoss | 2.8 | Nichttragend | Abhängigkeiten - Abhängigkeit oben: Bis Ebene: 1. Obergeschoss
2542471 | Erdgeschoss | no | no | 3.65086 | 1.81151 | 1.98588 | Erdgeschoss | 2.8 | Nichttragend | Abhängigkeiten - Abhängigkeit oben: Bis Ebene: 1. Obergeschoss
2542662 | Erdgeschoss | no | no | 29.6321 | 14.7529 | 10.6009 | Erdgeschoss | 2.8 | Nichttragend | Abhängigkeiten - Abhängigkeit oben: Bis Ebene: 1. Obergeschoss
2542921 | Erdgeschoss | no | no | 23.7146 | 11.6419 | 8.615 | Erdgeschoss | 2.8 | Nichttragend | Abhängigkeiten - Abhängigkeit oben: Bis Ebene: 1. Obergeschoss
2547048 | 1. Obergeschoss | yes | no | 11.7612 | 6.10377 | 8.615 | 1. Obergeschoss | 3 | Nichttragend | Abhängigkeiten - Abhängigkeit oben: Bis Ebene: 1OG OK

# IfcWallStandardCase: Basiswand:1OG Wand 30 (7)
In: 1. Obergeschoss
Type - PredefinedType: STANDARD; Material: Trockenbau - Gipsplatte 0.03 m
Type - Andere - Kategorie: Wände; Familienname: Basiswand
Type - Konstruktion - Abschluss an Öffnungen: Keine; Funktion: Außen; Abschluss an Wänden: Keine; Breite: 0.03 m
Type - Grafiken - Füllmuster für groben Maßstab: <Flächenfüllung>; Farbfüllung für groben Maßstab: 32768
Type - ID-Daten - Beschreibung: STB_200; Typname: 1OG Wand 30
Type - Materialien und Oberflächen - Tragendes Material: Trockenbau - Gipsplatte
Type - Tragwerk - Filter Tragend / Nichttragend: yes
Type - Analytische Eigenschaften - Absorptionsgrad: 0.1; Rauigkeit: 1; Thermischer Widerstand (R): 0.0461538 s3*K/kg; Thermisch wirksame Masse: 27720 kg/s2/K; Wärmedurchgangskoeffizient (U): 21.6667 kg/s3/K
Type - Pset_WallCommon - ThermalTransmittance: 21.6667 kg/s3/K
BaseQuantities - Width: 0.03 m
Pset_QuantityTakeOff - Reference: 1OG Wand 30; sets with these values: 2
Pset_WallCommon - IsExternal: yes; ExtendToStructure: no; LoadBearing: no; Reference: 1OG Wand 30
AVA - WANDLISTE - Typ: 1OG Wand 30; Breite: 0.03 m
ING - WANDLISTE - Typ: 1OG Wand 30; Material: Trockenbau - Gipsplatte; Breite: 0.03 m
Andere - Familie: Basiswand; Familie und Typ: Basiswand: 1OG Wand 30; Typ: 1OG Wand 30; Typ-ID: 2775443
Abhängigkeiten - Abhängig von Körper: no; Basislinie: Oberfläche: Außenkante; Oberkante ist fixiert.: no; Raumbegrenzung: yes; Unterkante ist fixiert: no; Verlängerungsabstand oben: 0 m; Verlängerungsabstand unten: 0 m
Phasen - Phase erstellt: Phase 01
Tragwerk - Tragwerk: no; Tragwerksverwendung: Nichttragend
Querschnittsdefinition - Querschnitt: Vertikal
Name (Basiswand:1OG Wand 30:...) | Height (m) | Length (m) | GrossFootprintArea (m2) | GrossVolume (m3) | GrossSideArea (m2) = NetSideArea (m2) = AVA - WANDLISTE, Fläche (m2) = ING - WANDLISTE, Fläche (m2) = Bemaßungen, Fläche (m2) | NetVolume (m3) = AVA - WANDLISTE, Volumen (m3) = ING - WANDLISTE, Volumen (m3) = Bemaßungen, Volumen (m3) | ING - WANDLISTE, Länge (m) = Bemaßungen, Länge (m) | Abhängigkeit oben | Abhängigkeit unten | Nicht verknüpfte Höhe (m) | Versatz oben (m) | Versatz unten (m)
2775627 | 0.210972 | 4.21 | 0.1263 | 0.0266434 | 0.888114 | 0.0256855 | 4.61 | Bis Ebene: 1OG OK | Traufe | 0.215291 | -0.677855 | 1.85685
2777597 | 0.208927 | 4.21 | 0.1263 | 0.0263852 | 0.879505 | 0.0254272 | 4.61 | Bis Ebene: 1OG OK | Traufe | 0.21531 | -0.675729 | 1.85896
2778569 | 0.210972 | 4.71 | 0.1413 | 0.0298077 | 0.993591 | 0.028736 | 5.11 | Bis Ebene: 1OG OK | Traufe | 0.215291 | -0.677855 | 1.85685
2785604 | 0.642272 | 1.0182 | 0.0305459 | 0.00546718 | 0.182239 | 0.00546718 | 1.04 | Bis Ebene: First OK | 1OG OK | 0.951727 | -1.40683 | -1.60856
2786545 | 0.642272 | 1.0182 | 0.0305459 | 0.00546718 | 0.182239 | 0.00546718 | 1.04 | Bis Ebene: First OK | 1OG OK | 0.951727 | -1.40683 | -1.60856
2831608 | 0.210972 | 2.78 | 0.0834 | 0.0175935 | 0.586451 | 0.0169609 | 3.03 | Bis Ebene: 1OG OK | Traufe | 0.215291 | -0.677855 | 1.85685
2831984 | 0.25027 | 2.78 | 0.0834 | 0.0208725 | 0.695749 | 0.0202213 | 3.03 | Bis Ebene: 1OG OK | Traufe | 0.275634 | -0.617513 | 1.85685

# IfcWallStandardCase: Basiswand:STB 100 (9)
In: Untergeschoss
Type - PredefinedType: STANDARD; Material: Ortbeton - bewehrt Verputzt 0.1 m
Type - Andere - Kategorie: Wände; Familienname: Basiswand
Type - Konstruktion - Abschluss an Öffnungen: Keine; Funktion: Außen; Abschluss an Wänden: Keine; Breite: 0.1 m
Type - Grafiken - Füllmuster für groben Maßstab: <Flächenfüllung>; Farbfüllung für groben Maßstab: 32768
Type - ID-Daten - Beschreibung: STB_200; Typname: STB 100
Type - Materialien und Oberflächen - Tragendes Material: Ortbeton - bewehrt Verputzt
Type - Tragwerk - Filter Tragend / Nichttragend: yes
Type - Analytische Eigenschaften - Absorptionsgrad: 0.1; Rauigkeit: 1; Thermischer Widerstand (R): 0.0956023 s3*K/kg; Thermisch wirksame Masse: 151110 kg/s2/K; Wärmedurchgangskoeffizient (U): 10.46 kg/s3/K
Type - Pset_WallCommon - ThermalTransmittance: 10.46 kg/s3/K
BaseQuantities - Height: 0.715826 m; Width: 0.1 m
Pset_QuantityTakeOff - Reference: STB 100; sets with these values: 2
Pset_WallCommon - IsExternal: yes; ExtendToStructure: no; LoadBearing: no; Reference: STB 100
AVA - WANDLISTE - Typ: STB 100; Breite: 0.1 m
ING - WANDLISTE - Typ: STB 100; Material: Ortbeton - bewehrt Verputzt; Breite: 0.1 m
Andere - Familie: Basiswand; Familie und Typ: Basiswand: STB 100; Typ: STB 100; Typ-ID: 2696892
Abhängigkeiten - Abhängig von Körper: no; Basislinie: Oberfläche: Außenkante; Oberkante ist fixiert.: no; Raumbegrenzung: yes; Unterkante ist fixiert: no; Verlängerungsabstand oben: 0 m; Verlängerungsabstand unten: 0 m; Versatz unten: 0 m; Abhängigkeit oben: Bis Ebene: Erdgeschoss; Abhängigkeit unten: Schacht UK; Nicht verknüpfte Höhe: 0.715826 m; Versatz oben: -0.149213 m
Phasen - Phase erstellt: Phase 01
Tragwerk - Tragwerk: no; Tragwerksverwendung: Nichttragend
Querschnittsdefinition - Querschnitt: Vertikal
Name (Basiswand:STB 100:...) | Length (m) | GrossFootprintArea (m2) | GrossVolume (m3) = NetVolume (m3) = AVA - WANDLISTE, Volumen (m3) = ING - WANDLISTE, Volumen (m3) = Bemaßungen, Volumen (m3) | GrossSideArea (m2) = NetSideArea (m2) = AVA - WANDLISTE, Fläche (m2) = ING - WANDLISTE, Fläche (m2) = Bemaßungen, Fläche (m2) | ING - WANDLISTE, Länge (m) = Bemaßungen, Länge (m)
2697450 | 0.5 | 0.05 | 0.0357913 | 0.357913 | 0.725
2697507 | 1.34 | 0.134 | 0.0959207 | 0.959207 | 1.34
2697550 | 0.4 | 0.04 | 0.028633 | 0.28633 | 0.725
2706563 | 0.5 | 0.05 | 0.0357913 | 0.357913 | 0.725
2706564 | 1.34 | 0.134 | 0.0959207 | 0.959207 | 1.34
2706565 | 0.4 | 0.04 | 0.028633 | 0.28633 | 0.725
2706604 | 0.5 | 0.05 | 0.0357913 | 0.357913 | 0.725
2706605 | 1.34 | 0.134 | 0.0959207 | 0.959207 | 1.34
2706606 | 0.4 | 0.04 | 0.028633 | 0.28633 | 0.725

# IfcWallStandardCase: Basiswand:STB 300 (6)
In: Untergeschoss
Type - PredefinedType: STANDARD; Material: Ortbeton - bewehrt Verputzt 0.3 m
Type - Andere - Kategorie: Wände; Familienname: Basiswand
Type - Konstruktion - Abschluss an Öffnungen: Keine; Funktion: Außen; Abschluss an Wänden: Keine; Breite: 0.3 m
Type - Grafiken - Füllmuster für groben Maßstab: <Flächenfüllung>; Farbfüllung für groben Maßstab: 32768
Type - ID-Daten - Beschreibung: STB_300; Typname: STB 300
Type - Materialien und Oberflächen - Tragendes Material: Ortbeton - bewehrt Verputzt
Type - Tragwerk - Filter Tragend / Nichttragend: yes
Type - Analytische Eigenschaften - Absorptionsgrad: 0.1; Rauigkeit: 1; Thermischer Widerstand (R): 0.286807 s3*K/kg; Thermisch wirksame Masse: 453330 kg/s2/K; Wärmedurchgangskoeffizient (U): 3.48667 kg/s3/K
Type - Pset_WallCommon - ThermalTransmittance: 3.48667 kg/s3/K
BaseQuantities - Height: 0.2 m; Width: 0.3 m
Pset_QuantityTakeOff - Reference: STB 300; sets with these values: 2
Pset_WallCommon - IsExternal: yes; ExtendToStructure: yes; LoadBearing: no; Reference: STB 300
AVA - WANDLISTE - Typ: STB 300; Breite: 0.3 m
ING - WANDLISTE - Typ: STB 300; Material: Ortbeton - bewehrt Verputzt; Breite: 0.3 m
Andere - Familie: Basiswand; Familie und Typ: Basiswand: STB 300; Typ: STB 300; Typ-ID: 712296
Abhängigkeiten - Abhängigkeit unten: Untergeschoss; Abhängig von Körper: no; Raumbegrenzung: yes; Unterkante ist fixiert: no; Verlängerungsabstand oben: 0 m; Verlängerungsabstand unten: 0 m; Versatz oben: 0 m; Basislinie: Oberfläche: Innenkante; Oberkante ist fixiert.: yes; Abhängigkeit oben: Bis Ebene: Untergeschoss; Nicht verknüpfte Höhe: 0.2 m; Versatz unten: -0.2 m
Phasen - Phase erstellt: Phase 01
Tragwerk - Tragwerk: no; Tragwerksverwendung: Nichttragend
Querschnittsdefinition - Querschnitt: Vertikal
Name (Basiswand:STB 300:...) | Length (m) | GrossFootprintArea (m2) | GrossVolume (m3) = NetVolume (m3) = AVA - WANDLISTE, Volumen (m3) = ING - WANDLISTE, Volumen (m3) = Bemaßungen, Volumen (m3) | GrossSideArea (m2) = NetSideArea (m2) = AVA - WANDLISTE, Fläche (m2) = ING - WANDLISTE, Fläche (m2) = Bemaßungen, Fläche (m2) | ING - WANDLISTE, Länge (m) = Bemaßungen, Länge (m)
2536669 | 8.59 | 2.577 | 0.5154 | 1.718 | 8.84
2537151 | 12.5 | 3.75 | 0.75 | 2.5 | 12.5
2537402 | 10.2759 | 3.08276 | 0.616553 | 2.05518 | 10.2759
2537591 | 4.51 | 1.353 | 0.2706 | 0.902 | 4.51
2537720 | 1.98588 | 0.595764 | 0.119153 | 0.397176 | 1.98588
2538001 | 7.69 | 2.307 | 0.4614 | 1.538 | 7.99

# IfcWallStandardCase: Basiswand:WD weich 250 (7)
In: Untergeschoss
Type - PredefinedType: STANDARD; Material: Dämmung - weich 0.25 m
Type - Andere - Kategorie: Wände; Familienname: Basiswand
Type - Konstruktion - Abschluss an Öffnungen: Keine; Abschluss an Wänden: Außen; Funktion: Außen; Breite: 0.25 m
Type - Grafiken - Füllmuster für groben Maßstab: <Flächenfüllung>; Farbfüllung für groben Maßstab: 33023
Type - ID-Daten - Beschreibung: WD_weich_200; Typname: WD weich 250
Type - Materialien und Oberflächen - Tragendes Material: Dämmung - weich
Type - Tragwerk - Filter Tragend / Nichttragend: no
Type - Analytische Eigenschaften - Absorptionsgrad: 0.1; Rauigkeit: 1; Thermischer Widerstand (R): 7.35294 s3*K/kg; Thermisch wirksame Masse: 35500 kg/s2/K; Wärmedurchgangskoeffizient (U): 0.136 kg/s3/K
Type - Pset_WallCommon - ThermalTransmittance: 0.136 kg/s3/K
BaseQuantities - Height: 0.2 m; Width: 0.25 m
Pset_QuantityTakeOff - Reference: WD weich 250; sets with these values: 2
Pset_WallCommon - IsExternal: yes; LoadBearing: no; Reference: WD weich 250
AVA - WANDLISTE - Typ: WD weich 250; Breite: 0.25 m
ING - WANDLISTE - Typ: WD weich 250; Material: Dämmung - weich; Breite: 0.25 m
Andere - Familie: Basiswand; Familie und Typ: Basiswand: WD weich 250; Typ: WD weich 250; Typ-ID: 2528716
Abhängigkeiten - Abhängigkeit unten: Untergeschoss; Abhängig von Körper: no; Raumbegrenzung: yes; Unterkante ist fixiert: no; Verlängerungsabstand oben: 0 m; Verlängerungsabstand unten: 0 m; Versatz oben: 0 m; Basislinie: Oberfläche: Innenkante; Abhängigkeit oben: Bis Ebene: Untergeschoss; Nicht verknüpfte Höhe: 0.2 m; Versatz unten: -0.2 m
Phasen - Phase erstellt: Phase 01
Tragwerk - Tragwerk: no; Tragwerksverwendung: Nichttragend
Querschnittsdefinition - Querschnitt: Vertikal
Name (Basiswand:WD weich 250:...) | Length (m) | GrossFootprintArea (m2) | GrossVolume (m3) = NetVolume (m3) = AVA - WANDLISTE, Volumen (m3) = ING - WANDLISTE, Volumen (m3) = Bemaßungen, Volumen (m3) | GrossSideArea (m2) = NetSideArea (m2) = AVA - WANDLISTE, Fläche (m2) = ING - WANDLISTE, Fläche (m2) = Bemaßungen, Fläche (m2) | ExtendToStructure = Oberkante ist fixiert. | ING - WANDLISTE, Länge (m) = Bemaßungen, Länge (m)
2534400 | 9.09 | 2.2725 | 0.4545 | 1.818 | no | 8.84
2534627 | 13.05 | 3.2625 | 0.6525 | 2.61 | no | 13.05
2534848 | 10.8259 | 2.70647 | 0.541294 | 2.16518 | no | 10.8259
2535043 | 5.06 | 1.265 | 0.253 | 1.012 | no | 5.06
2535135 | 1.98588 | 0.49647 | 0.0992939 | 0.397176 | yes | 1.98588
2535431 | 5.15 | 1.2875 | 0.2575 | 1.03 | yes | 5.275
2693132 | 0.67 | 0.1675 | 0.0335 | 0.134 | no | 0.795

# IfcWallStandardCase: Basiswand:Ziegel 100, Basiswand:Ziegel 100:2598554
In: 1. Obergeschoss
Type - PredefinedType: STANDARD; Material: Mauerwerk - Ziegel 0.1 m
Type - Andere - Kategorie: Wände; Familienname: Basiswand
Type - Konstruktion - Abschluss an Öffnungen: Keine; Abschluss an Wänden: Keine; Funktion: Innen; Breite: 0.1 m
Type - Grafiken - Füllmuster für groben Maßstab: <Flächenfüllung>; Farbfüllung für groben Maßstab: 255
Type - ID-Daten - Beschreibung: Ziegel_100; Typname: Ziegel 100
Type - Materialien und Oberflächen - Tragendes Material: Mauerwerk - Ziegel
Type - Tragwerk - Filter Tragend / Nichttragend: no
Type - Analytische Eigenschaften - Absorptionsgrad: 0.1; Rauigkeit: 1; Thermischer Widerstand (R): 0.185185 s3*K/kg; Thermisch wirksame Masse: 130200 kg/s2/K; Wärmedurchgangskoeffizient (U): 5.4 kg/s3/K
Type - Pset_WallCommon - ThermalTransmittance: 5.4 kg/s3/K
BaseQuantities - Height: 1.18926 m; Length: 4.21 m; Width: 0.1 m; GrossFootprintArea: 0.421 m2; GrossVolume: 0.500678 m3; GrossSideArea: 5.00678 m2; NetSideArea: 5.00678 m2; NetVolume: 0.48972 m3
Pset_QuantityTakeOff - Reference: Ziegel 100; sets with these values: 2
Pset_WallCommon - IsExternal: no; ExtendToStructure: yes; LoadBearing: no; Reference: Ziegel 100
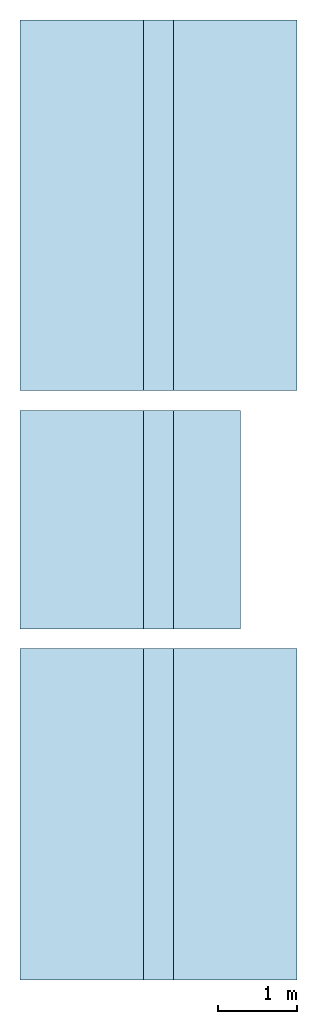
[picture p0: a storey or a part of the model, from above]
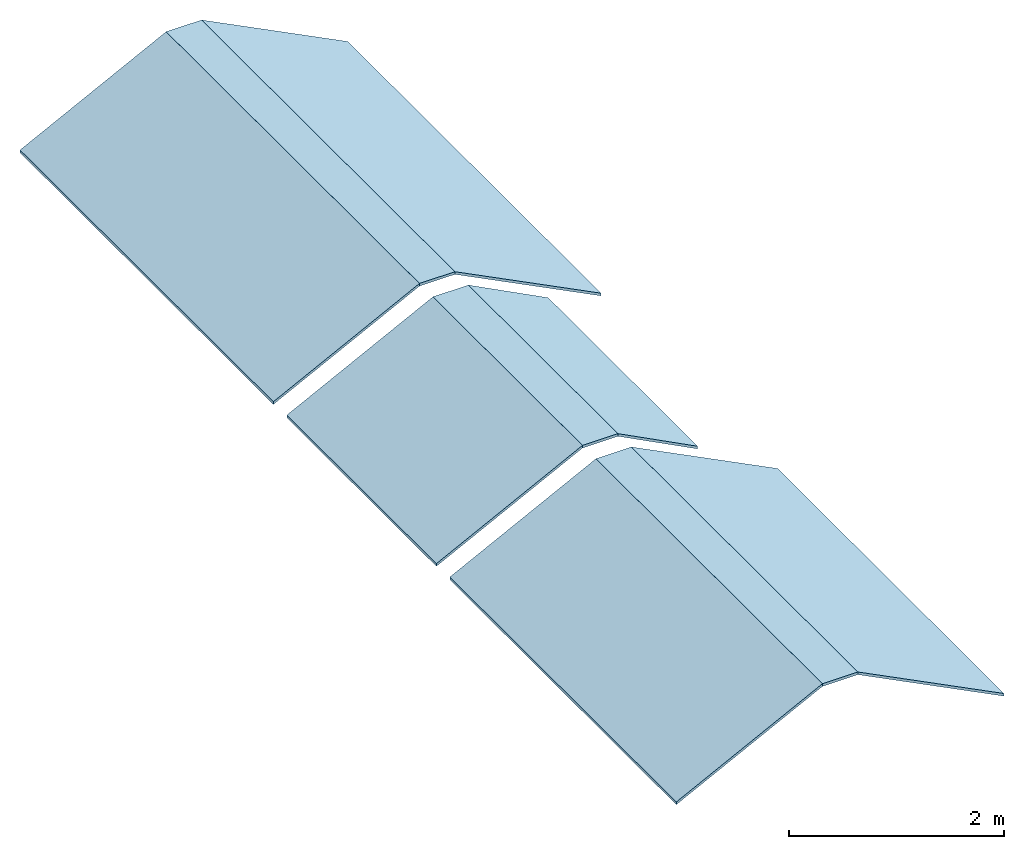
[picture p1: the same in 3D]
Properties of the parts of a building model (IFC2X3), part 4 of 5

# IfcWallStandardCase: Basiswand:Ziegel 100, Basiswand:Ziegel 100:2598554
AVA - WANDLISTE - Typ: Ziegel 100; Breite: 0.1 m; Fläche: 5.00678 m2; Volumen: 0.48972 m3
ING - WANDLISTE - Typ: Ziegel 100; Material: Mauerwerk - Ziegel; Breite: 0.1 m; Länge: 4.61 m; Fläche: 5.00678 m2; Volumen: 0.48972 m3
Andere - Familie: Basiswand; Familie und Typ: Basiswand: Ziegel 100; Typ: Ziegel 100; Typ-ID: 712209
Abhängigkeiten - Abhängig von Körper: no; Raumbegrenzung: yes; Unterkante ist fixiert: no; Verlängerungsabstand oben: 0 m; Verlängerungsabstand unten: 0 m; Versatz oben: 0 m; Versatz unten: 0 m; Basislinie: Oberfläche: Innenkante; Oberkante ist fixiert.: yes; Abhängigkeit oben: Bis Ebene: 1OG OK; Abhängigkeit unten: 1. Obergeschoss; Nicht verknüpfte Höhe: 3 m
Bemaßungen - Fläche: 5.00678 m2; Länge: 4.61 m; Volumen: 0.48972 m3
Phasen - Phase erstellt: Phase 01
Tragwerk - Tragwerk: no; Tragwerksverwendung: Nichttragend
Querschnittsdefinition - Querschnitt: Vertikal

# IfcWallStandardCase: Basiswand:Ziegel 120, Basiswand:Ziegel 120:2547641
In: Erdgeschoss
Type - PredefinedType: STANDARD; Material: Mauerwerk - Ziegel 0.12 m
Type - Andere - Kategorie: Wände; Familienname: Basiswand
Type - Konstruktion - Abschluss an Öffnungen: Keine; Abschluss an Wänden: Keine; Funktion: Innen; Breite: 0.12 m
Type - Grafiken - Füllmuster für groben Maßstab: <Flächenfüllung>; Farbfüllung für groben Maßstab: 255
Type - ID-Daten - Beschreibung: Ziegel_120; Typname: Ziegel 120
Type - Materialien und Oberflächen - Tragendes Material: Mauerwerk - Ziegel
Type - Tragwerk - Filter Tragend / Nichttragend: no
Type - Analytische Eigenschaften - Absorptionsgrad: 0.1; Rauigkeit: 1; Thermischer Widerstand (R): 0.222222 s3*K/kg; Thermisch wirksame Masse: 156240 kg/s2/K; Wärmedurchgangskoeffizient (U): 4.5 kg/s3/K
Type - Pset_WallCommon - ThermalTransmittance: 4.5 kg/s3/K
BaseQuantities - Height: 2.51506 m; Length: 1.8 m; Width: 0.12 m; GrossFootprintArea: 0.216 m2; GrossVolume: 0.382738 m3; GrossSideArea: 3.18948 m2; NetSideArea: 3.18948 m2; NetVolume: 0.382738 m3
Pset_QuantityTakeOff - Reference: Ziegel 120; sets with these values: 2
Pset_WallCommon - ExtendToStructure: no; IsExternal: no; LoadBearing: no; Reference: Ziegel 120
AVA - WANDLISTE - Typ: Ziegel 120; Breite: 0.12 m; Fläche: 3.18948 m2; Volumen: 0.382738 m3
ING - WANDLISTE - Typ: Ziegel 120; Material: Mauerwerk - Ziegel; Breite: 0.12 m; Länge: 1.8 m; Fläche: 3.18948 m2; Volumen: 0.382738 m3
Andere - Familie: Basiswand; Familie und Typ: Basiswand: Ziegel 120; Typ: Ziegel 120; Typ-ID: 712211
Abhängigkeiten - Abhängig von Körper: no; Oberkante ist fixiert.: no; Raumbegrenzung: yes; Unterkante ist fixiert: no; Verlängerungsabstand oben: 0 m; Verlängerungsabstand unten: 0 m; Basislinie: Oberfläche: Innenkante; Abhängigkeit oben: Bis Ebene: 1. Obergeschoss; Abhängigkeit unten: Erdgeschoss; Nicht verknüpfte Höhe: 2.49748 m; Versatz oben: -1.90994 m; Versatz unten: -1.60743 m
Bemaßungen - Fläche: 3.18948 m2; Länge: 1.8 m; Volumen: 0.382738 m3
Phasen - Phase erstellt: Phase 01
Tragwerk - Tragwerk: no; Tragwerksverwendung: Nichttragend
Querschnittsdefinition - Querschnitt: Vertikal

# IfcWallStandardCase: Basiswand:Ziegel 200 (22)
Type - PredefinedType: STANDARD; Material: Mauerwerk - Ziegel 0.2 m
Type - Andere - Kategorie: Wände; Familienname: Basiswand
Type - Konstruktion - Abschluss an Öffnungen: Keine; Abschluss an Wänden: Keine; Breite: 0.2 m; Funktion: Innen
Type - Grafiken - Füllmuster für groben Maßstab: <Flächenfüllung>; Farbfüllung für groben Maßstab: 255
Type - ID-Daten - Beschreibung: Ziegel_200; Typname: Ziegel 200
Type - Materialien und Oberflächen - Tragendes Material: Mauerwerk - Ziegel
Type - Tragwerk - Filter Tragend / Nichttragend: yes
Type - Analytische Eigenschaften - Absorptionsgrad: 0.1; Rauigkeit: 1; Thermischer Widerstand (R): 0.37037 s3*K/kg; Thermisch wirksame Masse: 260400 kg/s2/K; Wärmedurchgangskoeffizient (U): 2.7 kg/s3/K
Type - Pset_WallCommon - ThermalTransmittance: 2.7 kg/s3/K
BaseQuantities - Width: 0.2 m
Pset_QuantityTakeOff - Reference: Ziegel 200; sets with these values: 2
Pset_WallCommon - Reference: Ziegel 200; IsExternal: no
AVA - WANDLISTE - Typ: Ziegel 200; Breite: 0.2 m
ING - WANDLISTE - Typ: Ziegel 200; Material: Mauerwerk - Ziegel; Breite: 0.2 m
Andere - Familie: Basiswand; Familie und Typ: Basiswand: Ziegel 200; Typ: Ziegel 200; Typ-ID: 712263
Abhängigkeiten - Abhängig von Körper: no; Raumbegrenzung: yes; Unterkante ist fixiert: no; Verlängerungsabstand oben: 0 m; Verlängerungsabstand unten: 0 m; Versatz unten: 0 m
Phasen - Phase erstellt: Phase 01
Querschnittsdefinition - Querschnitt: Vertikal
Name (Basiswand:Ziegel 200:...) | In | Height (m) | Length (m) | GrossFootprintArea (m2) | GrossVolume (m3) | GrossSideArea (m2) = NetSideArea (m2) = AVA - WANDLISTE, Fläche (m2) = ING - WANDLISTE, Fläche (m2) = Bemaßungen, Fläche (m2) | NetVolume (m3) = AVA - WANDLISTE, Volumen (m3) = ING - WANDLISTE, Volumen (m3) = Bemaßungen, Volumen (m3) | ExtendToStructure = Oberkante ist fixiert. | LoadBearing = Tragwerk | ING - WANDLISTE, Länge (m) = Bemaßungen, Länge (m) | Abhängigkeit unten | Abhängigkeit oben | Basislinie | Nicht verknüpfte Höhe (m) | Versatz oben (m) | Tragwerksverwendung
2521004 | Untergeschoss | 2.35 | 7.65 | 1.53 | 2.88384 | 14.4192 | 2.88384 | yes | no | 8.025 | Untergeschoss | Bis Ebene: Erdgeschoss | Oberfläche: Innenkante | 2.35 | -0.25 | Nichttragend
2521217 | Untergeschoss | 2.35 | 3.89703 | 0.779407 | 1.83161 | 9.15803 | 1.83161 | yes | no | 4.27203 | Untergeschoss | Bis Ebene: Erdgeschoss | Oberfläche: Innenkante | 2.35 | -0.25 | Nichttragend
2521336 | Untergeschoss | 2.35 | 1.46 | 0.292 | 0.33037 | 1.65185 | 0.33037 | yes | no | 1.46 | Untergeschoss | Bis Ebene: Erdgeschoss | Oberfläche: Innenkante | 2.35 | -0.25 | Nichttragend
2521438 | Untergeschoss | 2.35 | 3.12 | 0.624 | 1.11057 | 5.55285 | 1.11057 | yes | no | 3.32 | Untergeschoss | Bis Ebene: Erdgeschoss | Oberfläche: Innenkante | 2.35 | -0.25 | Nichttragend
2521985 | Untergeschoss | 2.35 | 3.89297 | 0.778593 | 1.47386 | 7.36932 | 1.47386 | yes | yes | 4.26797 | Untergeschoss | Bis Ebene: Erdgeschoss | Oberfläche: Außenkante | 2.35 | -0.25 | Tragend | ID-Daten - Hat Verknüpfung: no; Tragwerk - Betonüberdeckung - Andere Flächen: c=2.0cm <2,0 cm>; Betonüberdeckung - Außenfläche: c=2.0cm <2,0 cm>; Betonüberdeckung - Innenfläche: c=2.0cm <2,0 cm>
2522097 | Untergeschoss | 2.35 | 4.55 | 0.91 | 2.1385 | 10.6925 | 2.1385 | yes | yes | 4.725 | Untergeschoss | Bis Ebene: Erdgeschoss | Oberfläche: Außenkante | 2.35 | -0.25 | Tragend | ID-Daten - Hat Verknüpfung: no; Tragwerk - Betonüberdeckung - Andere Flächen: c=2.0cm <2,0 cm>; Betonüberdeckung - Außenfläche: c=2.0cm <2,0 cm>; Betonüberdeckung - Innenfläche: c=2.0cm <2,0 cm>
2522173 | Untergeschoss | 2.35 | 4.59297 | 0.918593 | 1.44703 | 7.23517 | 1.44703 | yes | yes | 4.96797 | Untergeschoss | Bis Ebene: Erdgeschoss | Oberfläche: Außenkante | 2.35 | -0.25 | Tragend | ID-Daten - Hat Verknüpfung: no; Tragwerk - Betonüberdeckung - Andere Flächen: c=2.0cm <2,0 cm>; Betonüberdeckung - Außenfläche: c=2.0cm <2,0 cm>; Betonüberdeckung - Innenfläche: c=2.0cm <2,0 cm>
2522307 | Untergeschoss | 2.35 | 4.35 | 0.87 | 1.70098 | 8.50492 | 1.70098 | yes | yes | 4.725 | Untergeschoss | Bis Ebene: Erdgeschoss | Oberfläche: Außenkante | 2.35 | -0.25 | Tragend | ID-Daten - Hat Verknüpfung: no; Tragwerk - Betonüberdeckung - Andere Flächen: c=2.0cm <2,0 cm>; Betonüberdeckung - Außenfläche: c=2.0cm <2,0 cm>; Betonüberdeckung - Innenfläche: c=2.0cm <2,0 cm>
2522374 | Untergeschoss | 2.35 | 2.23297 | 0.446593 | 1.04949 | 5.24747 | 1.04949 | yes | yes | 2.60797 | Untergeschoss | Bis Ebene: Erdgeschoss | Oberfläche: Außenkante | 2.35 | -0.25 | Tragend | ID-Daten - Hat Verknüpfung: no; Tragwerk - Betonüberdeckung - Andere Flächen: c=2.0cm <2,0 cm>; Betonüberdeckung - Außenfläche: c=2.0cm <2,0 cm>; Betonüberdeckung - Innenfläche: c=2.0cm <2,0 cm>
2522542 | Untergeschoss | 2.35 | 2.43297 | 0.486593 | 1.14349 | 5.71747 | 1.14349 | yes | no | 2.80797 | Untergeschoss | Bis Ebene: Erdgeschoss | Oberfläche: Innenkante | 2.35 | -0.25 | Nichttragend
2543580 | Erdgeschoss | 2.55 | 7.74 | 1.548 | 3.23574 | 16.1787 | 3.23574 | no | no | 8.14 | Erdgeschoss | Bis Ebene: 1. Obergeschoss | Oberfläche: Innenkante | 2.55 | -0.25 | Nichttragend
2544161 | Erdgeschoss | 2.55 | 4.21 | 0.842 | 1.8111 | 9.0555 | 1.8111 | no | no | 4.61 | Erdgeschoss | Bis Ebene: 1. Obergeschoss | Oberfläche: Innenkante | 2.55 | -0.25 | Nichttragend
2544267 | Erdgeschoss | 2.55 | 3.85797 | 0.771593 | 1.60355 | 8.01776 | 1.60355 | no | no | 4.15797 | Erdgeschoss | Bis Ebene: 1. Obergeschoss | Oberfläche: Innenkante | 2.55 | -0.25 | Nichttragend
2544570 | Erdgeschoss | 2.55 | 2.2 | 0.44 | 0.75799 | 3.78995 | 0.75799 | no | no | 2.175 | Erdgeschoss | Bis Ebene: 1. Obergeschoss | Oberfläche: Innenkante | 2.55 | -0.25 | Nichttragend
2549160 | 1. Obergeschoss | 3.46516 | 1.75 | 0.35 | 1.20237 | 6.01185 | 1.20203 | yes | no | 1.775 | 1. Obergeschoss | Bis Ebene: 1OG OK | Oberfläche: Innenkante | 3 | 0 | Nichttragend
2549305 | 1. Obergeschoss | 3.39086 | 3.65 | 0.73 | 1.7818 | 8.909 | 1.7818 | yes | no | 3.625 | 1. Obergeschoss | Bis Ebene: 1OG OK | Oberfläche: Innenkante | 3 | 0 | Nichttragend
2549715 | 1. Obergeschoss | 2.00693 | 4.21 | 0.842 | 1.38469 | 6.92343 | 1.34085 | yes | no | 4.61 | 1. Obergeschoss | Bis Ebene: 1OG OK | Oberfläche: Innenkante | 3 | 0 | Nichttragend
2549786 | 1. Obergeschoss | 1.30945 | 4.21 | 0.842 | 1.10255 | 5.51277 | 1.05872 | yes | no | 4.76 | 1. Obergeschoss | Bis Ebene: 1OG OK | Oberfläche: Innenkante | 3 | 0 | Nichttragend
2551705 | Untergeschoss | 2.35 | 1.26 | 0.252 | 0.25508 | 1.2754 | 0.25508 | yes | no | 1.46 | Untergeschoss | Bis Ebene: Erdgeschoss | Oberfläche: Innenkante | 2.6 | 0 | Nichttragend
2553752 | Erdgeschoss | 2.55 | 1.6 | 0.32 | 0.816 | 4.08 | 0.816 | no | no | 1.775 | Erdgeschoss | Bis Ebene: 1. Obergeschoss | Oberfläche: Innenkante | 2.55 | -0.25 | Nichttragend
2553791 | Erdgeschoss | 2.55 | 0.54 | 0.108 | 0.2754 | 1.377 | 0.2754 | no | no | 0.54 | Erdgeschoss | Bis Ebene: 1. Obergeschoss | Oberfläche: Innenkante | 2.55 | -0.25 | Nichttragend
2553831 | Erdgeschoss | 2.55 | 2.48203 | 0.496407 | 1.26584 | 6.32919 | 1.26584 | no | no | 2.68203 | Erdgeschoss | Bis Ebene: 1. Obergeschoss | Oberfläche: Innenkante | 2.55 | -0.25 | Nichttragend

# IfcWallStandardCase: Basiswand:Ziegel 250 (9)
Type - PredefinedType: STANDARD; Material: Mauerwerk - Ziegel 0.25 m
Type - Andere - Kategorie: Wände; Familienname: Basiswand
Type - Konstruktion - Abschluss an Öffnungen: Keine; Abschluss an Wänden: Keine; Funktion: Innen; Breite: 0.25 m
Type - Grafiken - Füllmuster für groben Maßstab: <Flächenfüllung>; Farbfüllung für groben Maßstab: 255
Type - ID-Daten - Beschreibung: Ziegel_250; Typname: Ziegel 250
Type - Materialien und Oberflächen - Tragendes Material: Mauerwerk - Ziegel
Type - Tragwerk - Filter Tragend / Nichttragend: yes
Type - Analytische Eigenschaften - Absorptionsgrad: 0.1; Rauigkeit: 1; Thermischer Widerstand (R): 0.462963 s3*K/kg; Thermisch wirksame Masse: 325500 kg/s2/K; Wärmedurchgangskoeffizient (U): 2.16 kg/s3/K
Type - Pset_WallCommon - ThermalTransmittance: 2.16 kg/s3/K
BaseQuantities - Width: 0.25 m
Pset_QuantityTakeOff - Reference: Ziegel 250; sets with these values: 2
Pset_WallCommon - IsExternal: no; LoadBearing: no; Reference: Ziegel 250
AVA - WANDLISTE - Typ: Ziegel 250; Breite: 0.25 m
ING - WANDLISTE - Typ: Ziegel 250; Material: Mauerwerk - Ziegel; Breite: 0.25 m
Andere - Familie: Basiswand; Familie und Typ: Basiswand: Ziegel 250; Typ: Ziegel 250; Typ-ID: 712214
Abhängigkeiten - Abhängig von Körper: no; Raumbegrenzung: yes; Unterkante ist fixiert: no; Verlängerungsabstand oben: 0 m; Verlängerungsabstand unten: 0 m; Versatz unten: 0 m
Phasen - Phase erstellt: Phase 01
Tragwerk - Tragwerk: no; Tragwerksverwendung: Nichttragend
Querschnittsdefinition - Querschnitt: Vertikal
Name (Basiswand:Ziegel 250:...) | In | Height (m) | Length (m) | GrossFootprintArea (m2) | GrossVolume (m3) | GrossSideArea (m2) = NetSideArea (m2) | NetVolume (m3) = AVA - WANDLISTE, Volumen (m3) = ING - WANDLISTE, Volumen (m3) = Bemaßungen, Volumen (m3) | ExtendToStructure = Oberkante ist fixiert. | AVA - WANDLISTE, Fläche (m2) = ING - WANDLISTE, Fläche (m2) = Bemaßungen, Fläche (m2) | ING - WANDLISTE, Länge (m) = Bemaßungen, Länge (m) | Basislinie | Abhängigkeit oben | Abhängigkeit unten | Nicht verknüpfte Höhe (m) | Versatz oben (m)
2543919 | Erdgeschoss | 2.55 | 8.14 | 2.035 | 4.31424 | 17.257 | 4.31424 | no | 17.257 | 8.615 | Oberfläche: Außenkante | Bis Ebene: 1. Obergeschoss | Erdgeschoss | 2.55 | -0.25
2544834 | Erdgeschoss | 2.55 | 1.075 | 0.26875 | 0.284375 | 1.1375 | 0.265312 | no | 1.06125 | 1.275 | Oberfläche: Innenkante | Bis Ebene: 1. Obergeschoss | Erdgeschoss | 2.55 | -0.25
2544954 | Erdgeschoss | 2.55 | 2.58297 | 0.645741 | 1.64664 | 6.58656 | 1.64664 | no | 6.58656 | 2.88297 | Oberfläche: Innenkante | Bis Ebene: 1. Obergeschoss | Erdgeschoss | 2.55 | -0.25
2548959 | 1. Obergeschoss | 3.46516 | 8.14 | 2.035 | 4.32205 | 17.2882 | 4.32205 | yes | 17.2882 | 8.615 | Oberfläche: Innenkante | Bis Ebene: 1OG OK | 1. Obergeschoss | 3 | 0
2549120 | 1. Obergeschoss | 3.46516 | 3.17854 | 0.794635 | 1.71795 | 6.87178 | 1.71795 | yes | 6.87178 | 3.35354 | Oberfläche: Innenkante | Bis Ebene: 1OG OK | 1. Obergeschoss | 3 | 0
2549374 | 1. Obergeschoss | 1.62093 | 2.96 | 0.74 | 0.913674 | 3.6547 | 0.865522 | yes | 3.6547 | 3.335 | Oberfläche: Innenkante | Bis Ebene: 1OG OK | 1. Obergeschoss | 3 | 0
2549586 | 1. Obergeschoss | 1.62093 | 1.55 | 0.3875 | 0.62811 | 2.51244 | 0.602895 | yes | 2.51244 | 1.775 | Oberfläche: Innenkante | Bis Ebene: 1OG OK | 1. Obergeschoss | 3 | 0
2549631 | 1. Obergeschoss | 3.39086 | 4.96146 | 1.24036 | 2.16955 | 8.67819 | 2.16955 | yes | 8.67819 | 5.26146 | Oberfläche: Innenkante | Bis Ebene: 1OG OK | 1. Obergeschoss | 3 | 0
2809002 | Untergeschoss | 0.8 | 0.502046 | 0.0630115 | 0.100409 | 0.401637 | 0.0504092 | no | 0.401637 | 0.534889 | Oberfläche: Außenkante |  | Untergeschoss | 0.8 | 0

# IfcWallStandardCase: Basiswand:Ziegel+WD hart 200+200, Basiswand:Ziegel+WD hart 200+200:2546969
In: 1. Obergeschoss
Type - PredefinedType: STANDARD; Material: Dämmung - hart 0.2 m, Mauerwerk - Ziegel 0.2 m
Type - Andere - Kategorie: Wände; Familienname: Basiswand
Type - Konstruktion - Abschluss an Öffnungen: Keine; Abschluss an Wänden: Außen; Funktion: Außen; Breite: 0.4 m
Type - Grafiken - Füllmuster für groben Maßstab: <Flächenfüllung>; Farbfüllung für groben Maßstab: 255
Type - ID-Daten - Beschreibung: Ziegel+WD_hart_200+200; Typname: Ziegel+WD hart 200+200
Type - Materialien und Oberflächen - Tragendes Material: Mauerwerk - Ziegel
Type - Tragwerk - Filter Tragend / Nichttragend: yes
Type - Analytische Eigenschaften - Absorptionsgrad: 0.1; Rauigkeit: 1; Thermischer Widerstand (R): 7.77778 s3*K/kg; Thermisch wirksame Masse: 270690 kg/s2/K; Wärmedurchgangskoeffizient (U): 0.128571 kg/s3/K
Type - Pset_WallCommon - ThermalTransmittance: 0.128571 kg/s3/K
BaseQuantities - Height: 0.808084 m; Length: 13.3 m; Width: 0.4 m; GrossFootprintArea: 5.1 m2; GrossVolume: 3.94345 m3; GrossSideArea: 9.85862 m2; NetSideArea: 9.85862 m2; NetVolume: 3.58262 m3
Pset_QuantityTakeOff - Reference: Ziegel+WD hart 200+200; sets with these values: 2
Pset_WallCommon - IsExternal: yes; ExtendToStructure: yes; LoadBearing: no; Reference: Ziegel+WD hart 200+200
AVA - WANDLISTE - Typ: Ziegel+WD hart 200+200; Breite: 0.4 m; Fläche: 9.85862 m2; Volumen: 3.58262 m3
ING - WANDLISTE - Typ: Ziegel+WD hart 200+200; Material: Mauerwerk - Ziegel; Breite: 0.4 m; Länge: 12.75 m; Fläche: 9.85862 m2; Volumen: 3.58262 m3
Andere - Familie: Basiswand; Familie und Typ: Basiswand: Ziegel+WD hart 200+200; Typ: Ziegel+WD hart 200+200; Typ-ID: 712286
Abhängigkeiten - Abhängig von Körper: no; Basislinie: Oberfläche: Außenkante; Raumbegrenzung: yes; Unterkante ist fixiert: no; Verlängerungsabstand oben: 0 m; Verlängerungsabstand unten: 0 m; Versatz oben: 0 m; Versatz unten: 0 m; Oberkante ist fixiert.: yes; Abhängigkeit oben: Bis Ebene: 1OG OK; Abhängigkeit unten: 1. Obergeschoss; Nicht verknüpfte Höhe: 3 m
Bemaßungen - Fläche: 9.85862 m2; Länge: 12.75 m; Volumen: 3.58262 m3
Phasen - Phase erstellt: Phase 01
Tragwerk - Tragwerk: no; Tragwerksverwendung: Nichttragend
Querschnittsdefinition - Querschnitt: Vertikal

# IfcWallStandardCase: Basiswand:Ziegel+WD hart 300+250 (6)
Type - PredefinedType: STANDARD; Material: Dämmung - hart 0.25 m, Mauerwerk - Ziegel 0.3 m
Type - Andere - Kategorie: Wände; Familienname: Basiswand
Type - Konstruktion - Abschluss an Öffnungen: Keine; Abschluss an Wänden: Außen; Breite: 0.55 m; Funktion: Außen
Type - Grafiken - Farbfüllung für groben Maßstab: 255; Füllmuster für groben Maßstab: <Flächenfüllung>
Type - ID-Daten - Beschreibung: Ziegel+WD_hart_300+160; Typname: Ziegel+WD hart 300+250
Type - Materialien und Oberflächen - Tragendes Material: Mauerwerk - Ziegel
Type - Tragwerk - Filter Tragend / Nichttragend: yes
Type - Analytische Eigenschaften - Absorptionsgrad: 0.1; Rauigkeit: 1; Thermischer Widerstand (R): 9.81481 s3*K/kg; Thermisch wirksame Masse: 403462 kg/s2/K; Wärmedurchgangskoeffizient (U): 0.101887 kg/s3/K
Type - Pset_WallCommon - ThermalTransmittance: 0.101887 kg/s3/K
BaseQuantities - Width: 0.55 m
Pset_QuantityTakeOff - Reference: Ziegel+WD hart 300+250; sets with these values: 2
Pset_WallCommon - Reference: Ziegel+WD hart 300+250; IsExternal: yes; LoadBearing: no
AVA - WANDLISTE - Typ: Ziegel+WD hart 300+250; Breite: 0.55 m
ING - WANDLISTE - Typ: Ziegel+WD hart 300+250; Material: Mauerwerk - Ziegel; Breite: 0.55 m
Andere - Familie: Basiswand; Familie und Typ: Basiswand: Ziegel+WD hart 300+250; Typ: Ziegel+WD hart 300+250; Typ-ID: 2519354
Abhängigkeiten - Abhängig von Körper: no; Basislinie: Oberfläche: Außenkante; Raumbegrenzung: yes; Unterkante ist fixiert: no; Verlängerungsabstand oben: 0 m; Verlängerungsabstand unten: 0 m; Versatz oben: 0 m; Versatz unten: 0 m
Phasen - Phase erstellt: Phase 01
Tragwerk - Tragwerk: no; Tragwerksverwendung: Nichttragend
Querschnittsdefinition - Querschnitt: Vertikal
Name (Basiswand:Ziegel+WD hart 300+250:...) | In | Height (m) | Length (m) | GrossFootprintArea (m2) | GrossVolume (m3) | GrossSideArea (m2) | NetSideArea (m2) = AVA - WANDLISTE, Fläche (m2) = ING - WANDLISTE, Fläche (m2) = Bemaßungen, Fläche (m2) | NetVolume (m3) = AVA - WANDLISTE, Volumen (m3) = ING - WANDLISTE, Volumen (m3) = Bemaßungen, Volumen (m3) | ExtendToStructure = Oberkante ist fixiert. | ING - WANDLISTE, Länge (m) = Bemaßungen, Länge (m) | Abhängigkeit unten | Abhängigkeit oben | Nicht verknüpfte Höhe (m)
2542197 | Untergeschoss | 2.6 | 7.99 | 4.24325 | 9.34538 | 16.9916 | 14.3546 | 7.40185 | no | 7.99 | Untergeschoss | Bis Ebene: Erdgeschoss | 2.6
2542556 | Erdgeschoss | 2.8 | 5.31 | 2.618 | 8.1774 | 14.868 | 10.14 | 4.3289 | no | 4.76 | Erdgeschoss | Bis Ebene: 1. Obergeschoss | 2.8
2546553 | 1. Obergeschoss | 1.88482 | 8.54 | 4.3945 | 8.28282 | 15.0597 | 15.0597 | 7.65372 | yes | 7.99 | 1. Obergeschoss | Bis Ebene: 1OG OK | 3
2546657 | 1. Obergeschoss | 1.88482 | 2.53588 | 1.09223 | 1.49409 | 2.71653 | 2.71653 | 1.33773 | yes | 1.98588 | 1. Obergeschoss | Bis Ebene: 1OG OK | 3
2546791 | 1. Obergeschoss | 0.851032 | 5.31 | 2.618 | 1.97056 | 3.58285 | 3.58285 | 1.83878 | yes | 4.76 | 1. Obergeschoss | Bis Ebene: 1OG OK | 3
2546884 | 1. Obergeschoss | 3.46516 | 11.0759 | 5.83048 | 12.3277 | 22.4139 | 15.0346 | 8.03687 | yes | 10.6009 | 1. Obergeschoss | Bis Ebene: 1OG OK | 3

# IfcWindow: FE 1 tlg - DrehKipp:1000 x 450, FE 1 tlg - DrehKipp:1000 x 450:2697631
In: Untergeschoss
Type - ParameterTakesPrecedence: no; Sizeable: no; Material: Glas - Isolierverglasung klar, Holz - generisch 140-100-70, Metall - Edelstahl gebürstet, Kunststoff - grau 70-70-70
Type - Andere - Kategorie: Fenster; Familienname: FE 1 tlg - DrehKipp; Vorgabewert für Einbauhöhe: 0.85 m
Type - Konstruktion - Wandabschluss: Nach Basisbauteil; Griffhöhe = Flügelmitte: yes; Flügelbreite: 0.07 m; Glasstärke: 0.044 m; Griffhöhe ab Flügelunterkante: 0.35 m; Rahmentiefe: 0.09 m
Type - Daten - Ausführung Verglasung: Isolierverglasung 3-fach; Bauart Fenster: Einfachfenster; Form Fenster: rechteckig; Lage Bauteil: außen; Teiligkeit Fenster: einteilig
Type - Bemaßungen - Randabstand Öffnungssymbol: 0 m; Breite: 1 m; Dicke: 0.09 m; Höhe: 0.45 m; Rohbaubreite: 1 m; Rohbauhöhe: 0.45 m
Type - ID-Daten - Beschreibung: 1-teilig; OmniClass-Nummer: 23.30.20.00; OmniClass-Titel: Windows; Typenkommentare: FE 1 tlg_DrehKipp; Typenmarkierung: 151; Typname: 1000 x 450; URL: www.autodesk.de/BIM
Type - Vollständige Legende - Fensterbank Schattenfuge Höhe: 0.007 m
Type - Segmente und Formteile - Fensterbankdicke Innen: 0.025 m; Fensterbank Metall Dicke: 0.002 m; Fensterbank Metall Höhe hinten: 0.02 m; Fensterbank Metall Höhe Tropfnase: 0.04 m; Fensterbank Stein Dicke: 0.02 m; Fensterbank Stein Überstand: 0.02 m
Type - Analytische Eigenschaften - Thermische Eigenschaften definieren durch: Schemaplantypen; Analytische Konstruktion: <Keine Auswahl>
OverallHeight: 1.3 m; OverallWidth: 1 m
Pset_QuantityTakeOff - Reference: 1000 x 450
Pset_WindowCommon - IsExternal: yes; Reference: 1000 x 450
AVA - FENSTERLISTE - Nr: FE 54; Familie: FE 1 tlg - DrehKipp; Typ: 1000 x 450; Breite: 1 m; Höhe: 0.45 m; BRH: 1.825 m; UK ST: 2.275 m
BaseQuantities - Height: 0.45 m; Width: 1 m; Area: 0.45 m2
Andere - Familie: FE 1 tlg - DrehKipp; AL Breite: 0.94 m; AL Höhe: 0.4 m; Familie und Typ: FE 1 tlg - DrehKipp: 1000 x 450; Host-ID: 2520192; Sturzhöhe: 2.275 m; Typ: 1000 x 450; Typ-ID: 2697622
Modelleigenschaften - Rahmenbreite Bandseite: 0.09 m; Rahmenbreite Griffseite: 0.09 m; Rahmenbreite Oben: 0.09 m; Rahmenbreite Unten: 0.1 m
Abhängigkeiten - Ebene: Untergeschoss; Fußbodenaufbau: 0 m; Wandaufbau Aussen: 0 m; Wandaufbau Innen: 0 m; Winkel Bandseite: 90 deg; Winkel Griffseite: 90 deg; Einbautiefe: 0.25 m; Schwelle/Brüstung: 1.825 m
Konstruktion - Leibungsschräge Oben: 0 m; Leibungsschräge Bandseite: 0 m; Leibungsschräge Griffseite: 0 m; AL_Abzug Bandseite: 0.03 m; AL_Abzug Griffseite: 0.03 m; AL_Abzug Oben: 0.03 m; AL_Abzug Unten: 0.02 m; Glasflaeche: 0.152 m2; Leibungsschräge Unten: 0.01 m
Bemaßungen - Fläche: 0.624074 m2; Volumen: 0.0405816 m3
Grafiken - Symbol Drehflügel im Grundriss: no; Winkel Öffnungssymbol: 45 deg
ID-Daten - Kennzeichen: FE 54
Vollständige Legende - B_Winkel 1: 0 deg; B_Winkel 2: 0 deg; B_AL_Abzug Rechts: 0.03 m; B_AL Abzug Links: 0.03 m; B_Einbautiefe: 1.25 m; B_Griffhöhe: 0.13 m; B_Leibungsschräge Links: 1 m; B_Leibungsschräge Oben: 1 m; B_Leibungsschräge Rechts: 1 m; B_Leibungsschräge Unten: 0.99 m; B_Neigung Fensterbank: 2.29061 deg; B_Rahmenbreite Links: 0.09 m; B_Rahmenbreite Rechts: 0.09 m; Rahmenlichte Breite: 0.82 m; Rahmenlichte Höhe: 0.26 m; Wandstärke: 0.55 m
Phasen - Phase erstellt: Phase 01
Schichten - Fensterbank Aussen Metall: yes; Fensterbank Aussen Stein: no; Fensterbank Innen vorhanden: yes

# IfcWindow: FE 1 tlg - DrehKipp:1250 x 1200 (2)
In: Erdgeschoss
Type - ParameterTakesPrecedence: no; Sizeable: no; Material: Glas - Isolierverglasung klar, Holz - generisch 140-100-70, Metall - Edelstahl gebürstet, Kunststoff - grau 70-70-70
Type - Andere - Kategorie: Fenster; Familienname: FE 1 tlg - DrehKipp; Vorgabewert für Einbauhöhe: 0.85 m
Type - Konstruktion - Wandabschluss: Nach Basisbauteil; Griffhöhe = Flügelmitte: yes; Flügelbreite: 0.07 m; Glasstärke: 0.044 m; Griffhöhe ab Flügelunterkante: 0.35 m; Rahmentiefe: 0.09 m
Type - Daten - Ausführung Verglasung: Isolierverglasung 3-fach; Bauart Fenster: Einfachfenster; Form Fenster: rechteckig; Lage Bauteil: außen; Teiligkeit Fenster: einteilig
Type - Bemaßungen - Randabstand Öffnungssymbol: 0 m; Breite: 1.25 m; Dicke: 0.09 m; Höhe: 1.2 m; Rohbaubreite: 1.25 m; Rohbauhöhe: 1.2 m
Type - ID-Daten - Beschreibung: 1-teilig; OmniClass-Nummer: 23.30.20.00; OmniClass-Titel: Windows; Typenkommentare: FE 1 tlg_DrehKipp; Typenmarkierung: 138; Typname: 1250 x 1200; URL: www.autodesk.de/BIM
Type - Vollständige Legende - Fensterbank Schattenfuge Höhe: 0.007 m
Type - Segmente und Formteile - Fensterbankdicke Innen: 0.025 m; Fensterbank Metall Dicke: 0.002 m; Fensterbank Metall Höhe hinten: 0.02 m; Fensterbank Metall Höhe Tropfnase: 0.04 m; Fensterbank Stein Dicke: 0.02 m; Fensterbank Stein Überstand: 0.02 m
Type - Analytische Eigenschaften - Thermische Eigenschaften definieren durch: Schemaplantypen; Analytische Konstruktion: <Keine Auswahl>
OverallHeight: 2.05 m; OverallWidth: 1.25 m
Pset_QuantityTakeOff - Reference: 1250 x 1200
Pset_WindowCommon - IsExternal: yes; Reference: 1250 x 1200
AVA - FENSTERLISTE - Familie: FE 1 tlg - DrehKipp; Typ: 1250 x 1200; Breite: 1.25 m; Höhe: 1.2 m
BaseQuantities - Height: 1.2 m; Width: 1.25 m; Area: 1.5 m2
Andere - AL Breite: 1.19 m; AL Höhe: 1.15 m; Familie: FE 1 tlg - DrehKipp; Familie und Typ: FE 1 tlg - DrehKipp: 1250 x 1200; Typ: 1250 x 1200; Typ-ID: 2562135
Modelleigenschaften - Rahmenbreite Bandseite: 0.09 m; Rahmenbreite Griffseite: 0.09 m; Rahmenbreite Oben: 0.09 m; Rahmenbreite Unten: 0.1 m
Abhängigkeiten - Ebene: Erdgeschoss; Fußbodenaufbau: 0 m; Wandaufbau Aussen: 0 m; Wandaufbau Innen: 0 m; Einbautiefe: 0.25 m; Winkel Bandseite: 90 deg; Winkel Griffseite: 90 deg
Konstruktion - Leibungsschräge Oben: 0 m; AL_Abzug Bandseite: 0.03 m; AL_Abzug Griffseite: 0.03 m; AL_Abzug Oben: 0.03 m; AL_Abzug Unten: 0.02 m; Glasflaeche: 0.9595 m2; Leibungsschräge Bandseite: 0 m; Leibungsschräge Griffseite: 0 m; Leibungsschräge Unten: 0.01 m
Bemaßungen - Fläche: 1.87829 m2; Volumen: 0.135306 m3
Grafiken - Symbol Drehflügel im Grundriss: no; Winkel Öffnungssymbol: 45 deg
Vollständige Legende - B_Winkel 1: 0 deg; B_Winkel 2: 0 deg; B_AL_Abzug Rechts: 0.03 m; B_AL Abzug Links: 0.03 m; B_Einbautiefe: 1.25 m; B_Griffhöhe: 0.505 m; B_Leibungsschräge Links: 1 m; B_Leibungsschräge Oben: 1 m; B_Leibungsschräge Rechts: 1 m; B_Leibungsschräge Unten: 0.99 m; B_Neigung Fensterbank: 2.29061 deg; B_Rahmenbreite Links: 0.09 m; B_Rahmenbreite Rechts: 0.09 m; Rahmenlichte Breite: 1.07 m; Rahmenlichte Höhe: 1.01 m
Phasen - Phase erstellt: Phase 01
Schichten - Fensterbank Aussen Metall: yes; Fensterbank Aussen Stein: no; Fensterbank Innen vorhanden: yes
Name (FE 1 tlg - DrehKipp:1250 x 1200:...) | Nr = Kennzeichen | BRH (m) = Schwelle/Brüstung (m) | UK ST (m) = Sturzhöhe (m) | Host-ID | Wandstärke (m)
2562141 | FE 19 | 1.00697 | 2.20697 | 2542662 | 0.55
2562364 | FE 20 | 0.99 | 2.19 | 2542777 | 0.4

# IfcWindow: FE 1 tlg - DrehKipp:600 x 1250 (3)
In: Erdgeschoss
Type - ParameterTakesPrecedence: no; Sizeable: no; Material: Glas - Isolierverglasung klar, Holz - generisch 140-100-70, Metall - Edelstahl gebürstet, Kunststoff - grau 70-70-70
Type - Andere - Kategorie: Fenster; Familienname: FE 1 tlg - DrehKipp; Vorgabewert für Einbauhöhe: 0.85 m
Type - Konstruktion - Wandabschluss: Nach Basisbauteil; Griffhöhe = Flügelmitte: yes; Flügelbreite: 0.07 m; Glasstärke: 0.044 m; Griffhöhe ab Flügelunterkante: 0.35 m; Rahmentiefe: 0.09 m
Type - Daten - Ausführung Verglasung: Isolierverglasung 3-fach; Bauart Fenster: Einfachfenster; Form Fenster: rechteckig; Lage Bauteil: außen; Teiligkeit Fenster: einteilig
Type - Bemaßungen - Randabstand Öffnungssymbol: 0 m; Breite: 0.6 m; Dicke: 0.09 m; Höhe: 1.25 m; Rohbaubreite: 0.6 m; Rohbauhöhe: 1.25 m
Type - ID-Daten - Beschreibung: 1-teilig; OmniClass-Nummer: 23.30.20.00; OmniClass-Titel: Windows; Typenkommentare: FE 1 tlg_DrehKipp; Typenmarkierung: 139; Typname: 600 x 1250; URL: www.autodesk.de/BIM
Type - Vollständige Legende - Fensterbank Schattenfuge Höhe: 0.007 m
Type - Segmente und Formteile - Fensterbankdicke Innen: 0.025 m; Fensterbank Metall Dicke: 0.002 m; Fensterbank Metall Höhe hinten: 0.02 m; Fensterbank Metall Höhe Tropfnase: 0.04 m; Fensterbank Stein Dicke: 0.02 m; Fensterbank Stein Überstand: 0.02 m
Type - Analytische Eigenschaften - Thermische Eigenschaften definieren durch: Schemaplantypen; Analytische Konstruktion: <Keine Auswahl>
OverallHeight: 2.1 m; OverallWidth: 0.6 m
Pset_QuantityTakeOff - Reference: 600 x 1250
Pset_WindowCommon - IsExternal: yes; Reference: 600 x 1250
AVA - FENSTERLISTE - Familie: FE 1 tlg - DrehKipp; Typ: 600 x 1250; Breite: 0.6 m; Höhe: 1.25 m
BaseQuantities - Height: 1.25 m; Width: 0.6 m; Area: 0.75 m2
Andere - Familie: FE 1 tlg - DrehKipp; Host-ID: 2542777; AL Breite: 0.54 m; AL Höhe: 1.2 m; Familie und Typ: FE 1 tlg - DrehKipp: 600 x 1250; Typ: 600 x 1250; Typ-ID: 2562653
Modelleigenschaften - Rahmenbreite Bandseite: 0.09 m; Rahmenbreite Griffseite: 0.09 m; Rahmenbreite Oben: 0.09 m; Rahmenbreite Unten: 0.1 m
Abhängigkeiten - Ebene: Erdgeschoss; Fußbodenaufbau: 0 m; Wandaufbau Aussen: 0 m; Wandaufbau Innen: 0 m; Winkel Bandseite: 90 deg; Winkel Griffseite: 90 deg; Einbautiefe: 0.2 m
Konstruktion - Leibungsschräge Oben: 0 m; Leibungsschräge Bandseite: 0 m; Leibungsschräge Griffseite: 0 m; AL_Abzug Bandseite: 0.03 m; AL_Abzug Griffseite: 0.03 m; AL_Abzug Oben: 0.03 m; AL_Abzug Unten: 0.02 m; Glasflaeche: 0.36 m2; Leibungsschräge Unten: 0.01 m
Bemaßungen - Fläche: 0.989433 m2; Volumen: 0.0676387 m3
Grafiken - Symbol Drehflügel im Grundriss: no; Winkel Öffnungssymbol: 45 deg
Vollständige Legende - B_Winkel 1: 0 deg; B_Winkel 2: 0 deg; B_AL_Abzug Rechts: 0.03 m; B_AL Abzug Links: 0.03 m; B_Einbautiefe: 1.2 m; B_Griffhöhe: 0.53 m; B_Leibungsschräge Links: 1 m; B_Leibungsschräge Oben: 1 m; B_Leibungsschräge Rechts: 1 m; B_Leibungsschräge Unten: 0.99 m; B_Neigung Fensterbank: 2.86241 deg; B_Rahmenbreite Links: 0.09 m; B_Rahmenbreite Rechts: 0.09 m; Rahmenlichte Breite: 0.42 m; Rahmenlichte Höhe: 1.06 m; Wandstärke: 0.4 m
Phasen - Phase erstellt: Phase 01
Schichten - Fensterbank Aussen Metall: yes; Fensterbank Aussen Stein: no; Fensterbank Innen vorhanden: yes
Name (FE 1 tlg - DrehKipp:600 x 1250:...) | Nr = Kennzeichen | BRH (m) = Schwelle/Brüstung (m) | UK ST (m) = Sturzhöhe (m)
2562662 | FE 21 | 0.975857 | 2.22586
2563012 | FE 22 | 0.95 | 2.2
2563026 | FE 23 | 0.95 | 2.2

# IfcWindow: FE 1 tlg - DrehKipp:850 x 600 (3)
In: Untergeschoss
Type - ParameterTakesPrecedence: no; Sizeable: no; Material: Glas - Isolierverglasung klar, Holz - generisch 140-100-70, Metall - Edelstahl gebürstet, Kunststoff - grau 70-70-70
Type - Andere - Kategorie: Fenster; Familienname: FE 1 tlg - DrehKipp; Vorgabewert für Einbauhöhe: 0.85 m
Type - Konstruktion - Wandabschluss: Nach Basisbauteil; Griffhöhe = Flügelmitte: yes; Flügelbreite: 0.07 m; Glasstärke: 0.044 m; Griffhöhe ab Flügelunterkante: 0.35 m; Rahmentiefe: 0.09 m
Type - Daten - Ausführung Verglasung: Isolierverglasung 3-fach; Bauart Fenster: Einfachfenster; Form Fenster: rechteckig; Lage Bauteil: außen; Teiligkeit Fenster: einteilig
Type - Bemaßungen - Randabstand Öffnungssymbol: 0 m; Breite: 0.85 m; Dicke: 0.09 m; Höhe: 0.6 m; Rohbaubreite: 0.85 m; Rohbauhöhe: 0.6 m
Type - ID-Daten - Beschreibung: 1-teilig; OmniClass-Nummer: 23.30.20.00; OmniClass-Titel: Windows; Typenkommentare: FE 1 tlg_DrehKipp; Typenmarkierung: 150; Typname: 850 x 600; URL: www.autodesk.de/BIM
Type - Vollständige Legende - Fensterbank Schattenfuge Höhe: 0.007 m
Type - Segmente und Formteile - Fensterbankdicke Innen: 0.025 m; Fensterbank Metall Dicke: 0.002 m; Fensterbank Metall Höhe hinten: 0.02 m; Fensterbank Metall Höhe Tropfnase: 0.04 m; Fensterbank Stein Dicke: 0.02 m; Fensterbank Stein Überstand: 0.02 m
Type - Analytische Eigenschaften - Thermische Eigenschaften definieren durch: Schemaplantypen; Analytische Konstruktion: <Keine Auswahl>
OverallHeight: 1.45 m; OverallWidth: 0.85 m
Pset_QuantityTakeOff - Reference: 850 x 600
Pset_WindowCommon - IsExternal: yes; Reference: 850 x 600
AVA - FENSTERLISTE - Familie: FE 1 tlg - DrehKipp; Typ: 850 x 600; Breite: 0.85 m; Höhe: 0.6 m; BRH: 1.78628 m; UK ST: 2.38628 m
BaseQuantities - Height: 0.6 m; Width: 0.85 m; Area: 0.51 m2
Andere - Familie: FE 1 tlg - DrehKipp; AL Breite: 0.79 m; AL Höhe: 0.55 m; Familie und Typ: FE 1 tlg - DrehKipp: 850 x 600; Sturzhöhe: 2.38628 m; Typ: 850 x 600; Typ-ID: 2690108
Modelleigenschaften - Rahmenbreite Bandseite: 0.09 m; Rahmenbreite Griffseite: 0.09 m; Rahmenbreite Oben: 0.09 m; Rahmenbreite Unten: 0.1 m
Abhängigkeiten - Ebene: Untergeschoss; Fußbodenaufbau: 0 m; Wandaufbau Aussen: 0 m; Wandaufbau Innen: 0 m; Winkel Bandseite: 90 deg; Winkel Griffseite: 90 deg; Einbautiefe: 0.25 m; Schwelle/Brüstung: 1.78628 m
Konstruktion - Leibungsschräge Oben: 0 m; Leibungsschräge Bandseite: 0 m; Leibungsschräge Griffseite: 0 m; AL_Abzug Bandseite: 0.03 m; AL_Abzug Griffseite: 0.03 m; AL_Abzug Oben: 0.03 m; AL_Abzug Unten: 0.02 m; Glasflaeche: 0.2135 m2; Leibungsschräge Unten: 0.01 m
Bemaßungen - Fläche: 0.697634 m2; Volumen: 0.0460087 m3
Grafiken - Symbol Drehflügel im Grundriss: no; Winkel Öffnungssymbol: 45 deg
Vollständige Legende - B_Winkel 1: 0 deg; B_Winkel 2: 0 deg; B_AL_Abzug Rechts: 0.03 m; B_AL Abzug Links: 0.03 m; B_Einbautiefe: 1.25 m; B_Griffhöhe: 0.205 m; B_Leibungsschräge Links: 1 m; B_Leibungsschräge Oben: 1 m; B_Leibungsschräge Rechts: 1 m; B_Leibungsschräge Unten: 0.99 m; B_Neigung Fensterbank: 2.29061 deg; B_Rahmenbreite Links: 0.09 m; B_Rahmenbreite Rechts: 0.09 m; Rahmenlichte Breite: 0.67 m; Rahmenlichte Höhe: 0.41 m; Wandstärke: 0.55 m
Phasen - Phase erstellt: Phase 01
Schichten - Fensterbank Aussen Metall: yes; Fensterbank Aussen Stein: no; Fensterbank Innen vorhanden: yes
Name (FE 1 tlg - DrehKipp:850 x 600:...) | Nr = Kennzeichen | Host-ID
2690117 | FE 50 | 2519990
2690509 | FE 51 | 2519990
2803115 | FE 67 | 2520270

# IfcWindow: FE 1 tlg - DrehKipp:900 x 450 (2)
In: Untergeschoss
Type - ParameterTakesPrecedence: no; Sizeable: no; Material: Glas - Isolierverglasung klar, Holz - generisch 140-100-70, Metall - Edelstahl gebürstet, Kunststoff - grau 70-70-70
Type - Andere - Kategorie: Fenster; Familienname: FE 1 tlg - DrehKipp; Vorgabewert für Einbauhöhe: 0.85 m
Type - Konstruktion - Wandabschluss: Nach Basisbauteil; Griffhöhe = Flügelmitte: yes; Flügelbreite: 0.07 m; Glasstärke: 0.044 m; Griffhöhe ab Flügelunterkante: 0.35 m; Rahmentiefe: 0.09 m
Type - Daten - Ausführung Verglasung: Isolierverglasung 3-fach; Bauart Fenster: Einfachfenster; Form Fenster: rechteckig; Lage Bauteil: außen; Teiligkeit Fenster: einteilig
Type - Bemaßungen - Randabstand Öffnungssymbol: 0 m; Breite: 0.9 m; Dicke: 0.09 m; Höhe: 0.45 m; Rohbaubreite: 0.9 m; Rohbauhöhe: 0.45 m
Type - ID-Daten - Beschreibung: 1-teilig; OmniClass-Nummer: 23.30.20.00; OmniClass-Titel: Windows; Typenkommentare: FE 1 tlg_DrehKipp; Typenmarkierung: 152; Typname: 900 x 450; URL: www.autodesk.de/BIM
Type - Vollständige Legende - Fensterbank Schattenfuge Höhe: 0.007 m
Type - Segmente und Formteile - Fensterbankdicke Innen: 0.025 m; Fensterbank Metall Dicke: 0.002 m; Fensterbank Metall Höhe hinten: 0.02 m; Fensterbank Metall Höhe Tropfnase: 0.04 m; Fensterbank Stein Dicke: 0.02 m; Fensterbank Stein Überstand: 0.02 m
Type - Analytische Eigenschaften - Thermische Eigenschaften definieren durch: Schemaplantypen; Analytische Konstruktion: <Keine Auswahl>
OverallHeight: 1.3 m; OverallWidth: 0.9 m
Pset_QuantityTakeOff - Reference: 900 x 450
Pset_WindowCommon - IsExternal: yes; Reference: 900 x 450
AVA - FENSTERLISTE - Familie: FE 1 tlg - DrehKipp; Typ: 900 x 450; Breite: 0.9 m; Höhe: 0.45 m; BRH: 1.825 m; UK ST: 2.275 m
BaseQuantities - Height: 0.45 m; Width: 0.9 m; Area: 0.405 m2
Andere - Familie: FE 1 tlg - DrehKipp; Host-ID: 2520192; AL Breite: 0.84 m; AL Höhe: 0.4 m; Familie und Typ: FE 1 tlg - DrehKipp: 900 x 450; Sturzhöhe: 2.275 m; Typ: 900 x 450; Typ-ID: 2705762
Modelleigenschaften - Rahmenbreite Bandseite: 0.09 m; Rahmenbreite Griffseite: 0.09 m; Rahmenbreite Oben: 0.09 m; Rahmenbreite Unten: 0.1 m
Abhängigkeiten - Ebene: Untergeschoss; Fußbodenaufbau: 0 m; Wandaufbau Aussen: 0 m; Wandaufbau Innen: 0 m; Winkel Bandseite: 90 deg; Winkel Griffseite: 90 deg; Einbautiefe: 0.25 m; Schwelle/Brüstung: 1.825 m
Konstruktion - Leibungsschräge Oben: 0 m; Leibungsschräge Bandseite: 0 m; Leibungsschräge Griffseite: 0 m; AL_Abzug Bandseite: 0.03 m; AL_Abzug Griffseite: 0.03 m; AL_Abzug Oben: 0.03 m; AL_Abzug Unten: 0.02 m; Glasflaeche: 0.132 m2; Leibungsschräge Unten: 0.01 m
Bemaßungen - Fläche: 0.567062 m2; Volumen: 0.0365259 m3
Grafiken - Symbol Drehflügel im Grundriss: no; Winkel Öffnungssymbol: 80 deg
Vollständige Legende - B_Winkel 1: 0 deg; B_Winkel 2: 0 deg; B_AL_Abzug Rechts: 0.03 m; B_AL Abzug Links: 0.03 m; B_Einbautiefe: 1.25 m; B_Griffhöhe: 0.13 m; B_Leibungsschräge Links: 1 m; B_Leibungsschräge Oben: 1 m; B_Leibungsschräge Rechts: 1 m; B_Leibungsschräge Unten: 0.99 m; B_Neigung Fensterbank: 2.29061 deg; B_Rahmenbreite Links: 0.09 m; B_Rahmenbreite Rechts: 0.09 m; Rahmenlichte Breite: 0.72 m; Rahmenlichte Höhe: 0.26 m; Wandstärke: 0.55 m
Phasen - Phase erstellt: Phase 01
Schichten - Fensterbank Aussen Metall: yes; Fensterbank Aussen Stein: no; Fensterbank Innen vorhanden: yes
Name (FE 1 tlg - DrehKipp:900 x 450:...) | Nr = Kennzeichen
2705769 | FE 55
2706013 | FE 56

# IfcWindow: FE 1 tlg - Fix:1100 x 1500 (2)
In: Erdgeschoss
Type - ParameterTakesPrecedence: no; Sizeable: no; Material: Glas - Isolierverglasung klar, Kunststoff - grau 70-70-70, Holz - generisch 140-100-70
Type - Andere - Kategorie: Fenster; Familienname: FE 1 tlg - Fix; Vorgabewert für Einbauhöhe: 0.85 m
Type - Konstruktion - Wandabschluss: Nach Basisbauteil; Griffhöhe = Flügelmitte: yes; Flügelbreite: 0.07 m; Glasstärke: 0.044 m; Griffhöhe ab Flügelunterkante: 0.35 m; Rahmentiefe: 0.09 m
Type - Daten - Ausführung Verglasung: Isolierverglasung 3-fach; Bauart Fenster: Einfachfenster; Form Fenster: rechteckig; Lage Bauteil: außen; Teiligkeit Fenster: einteilig
Type - Bemaßungen - Randabstand Öffnungssymbol: 0 m; Breite: 1.1 m; Dicke: 0.09 m; Höhe: 1.5 m; Rohbaubreite: 1.1 m; Rohbauhöhe: 1.5 m
Type - ID-Daten - Beschreibung: 1-teilig; OmniClass-Nummer: 23.30.20.00; OmniClass-Titel: Windows; Typenkommentare: FE 1 tlg_Fix; Typenmarkierung: 135; Typname: 1100 x 1500; URL: www.autodesk.de/BIM
Type - Vollständige Legende - Fensterbank Schattenfuge Höhe: 0.007 m
Type - Segmente und Formteile - Fensterbankdicke Innen: 0.025 m; Fensterbank Metall Dicke: 0.002 m; Fensterbank Metall Höhe hinten: 0.02 m; Fensterbank Metall Höhe Tropfnase: 0.04 m; Fensterbank Stein Dicke: 0.02 m; Fensterbank Stein Überstand: 0.02 m
Type - Analytische Eigenschaften - Thermische Eigenschaften definieren durch: Schemaplantypen; Analytische Konstruktion: <Keine Auswahl>
OverallHeight: 2.35 m; OverallWidth: 1.1 m
Pset_QuantityTakeOff - Reference: 1100 x 1500
Pset_WindowCommon - IsExternal: yes; Reference: 1100 x 1500
AVA - FENSTERLISTE - Familie: FE 1 tlg - Fix; Typ: 1100 x 1500; Breite: 1.1 m; Höhe: 1.5 m; BRH: 0.7 m; UK ST: 2.2 m
BaseQuantities - Height: 1.5 m; Width: 1.1 m; Area: 1.65 m2
Andere - AL Breite: 1.07 m; AL Höhe: 1.45 m; Familie: FE 1 tlg - Fix; Familie und Typ: FE 1 tlg - Fix: 1100 x 1500; Host-ID: 2542412; Sturzhöhe: 2.2 m; Typ: 1100 x 1500; Typ-ID: 2555165
Modelleigenschaften - Rahmenbreite Links: 0.09 m; Rahmenbreite Oben: 0.09 m; Rahmenbreite Rechts: 0.09 m; Rahmenbreite Unten: 0.1 m
Abhängigkeiten - Ebene: Erdgeschoss; Fußbodenaufbau: 0 m; Einbautiefe: 0.25 m; Schwelle/Brüstung: 0.7 m; Wandaufbau Aussen: 0 m; Wandaufbau Innen: 0 m; Winkel Links: 90 deg; Winkel Rechts: 90 deg
Konstruktion - Leibungsschräge Oben: 0 m; AL_Abzug Oben: 0.03 m; AL_Abzug Unten: 0.02 m; Glasflaeche: 1.2052 m2; Leibungsschräge Links: 0 m; Leibungsschräge Rechts: 0 m; Leibungsschräge Unten: 0.01 m
Bemaßungen - Fläche: 2.05146 m2; Volumen: 0.148825 m3
Vollständige Legende - B_Winkel 1: 0 deg; B_Winkel 2: 0 deg; B_Einbautiefe: 1.25 m; B_Griffhöhe: 0.655 m; B_Leibungsschräge Links: 1 m; B_Leibungsschräge Oben: 1 m; B_Leibungsschräge Rechts: 1 m; B_Leibungsschräge Unten: 0.99 m; B_Neigung Fensterbank: 2.29061 deg; B_Rahmenbreite Links: 0.09 m; B_Rahmenbreite Rechts: 0.09 m; Rahmenlichte Breite: 0.92 m; Rahmenlichte Höhe: 1.31 m; Wandstärke: 0.55 m
Phasen - Phase erstellt: Phase 01
Schichten - Fensterbank Aussen Metall: yes; Fensterbank Aussen Stein: no; Fensterbank Innen vorhanden: yes
Name (FE 1 tlg - Fix:1100 x 1500:...) | Nr = Kennzeichen | AL_Abzug Links (m) = B_AL Abzug Links (m) | AL_Abzug Rechts (m) = B_AL_Abzug Rechts (m)
2556220 | FE 7 | 0.03 | 0
2558261 | FE 10 | 0 | 0.03

# IfcWindow: FE 1 tlg - Fix:1250 x 1500, FE 1 tlg - Fix:1250 x 1500:2558677
In: Erdgeschoss
Type - ParameterTakesPrecedence: no; Sizeable: no; Material: Glas - Isolierverglasung klar, Kunststoff - grau 70-70-70, Holz - generisch 140-100-70
Type - Andere - Kategorie: Fenster; Familienname: FE 1 tlg - Fix; Vorgabewert für Einbauhöhe: 0.85 m
Type - Konstruktion - Wandabschluss: Nach Basisbauteil; Griffhöhe = Flügelmitte: yes; Flügelbreite: 0.07 m; Glasstärke: 0.044 m; Griffhöhe ab Flügelunterkante: 0.35 m; Rahmentiefe: 0.09 m
Type - Daten - Ausführung Verglasung: Isolierverglasung 3-fach; Bauart Fenster: Einfachfenster; Form Fenster: rechteckig; Lage Bauteil: außen; Teiligkeit Fenster: einteilig
Type - Bemaßungen - Randabstand Öffnungssymbol: 0 m; Breite: 1.25 m; Dicke: 0.09 m; Höhe: 1.5 m; Rohbaubreite: 1.25 m; Rohbauhöhe: 1.5 m
Type - ID-Daten - Beschreibung: 1-teilig; OmniClass-Nummer: 23.30.20.00; OmniClass-Titel: Windows; Typenkommentare: FE 1 tlg_Fix; Typenmarkierung: 136; Typname: 1250 x 1500; URL: www.autodesk.de/BIM
Type - Vollständige Legende - Fensterbank Schattenfuge Höhe: 0.007 m
Type - Segmente und Formteile - Fensterbankdicke Innen: 0.025 m; Fensterbank Metall Dicke: 0.002 m; Fensterbank Metall Höhe hinten: 0.02 m; Fensterbank Metall Höhe Tropfnase: 0.04 m; Fensterbank Stein Dicke: 0.02 m; Fensterbank Stein Überstand: 0.02 m
Type - Analytische Eigenschaften - Thermische Eigenschaften definieren durch: Schemaplantypen; Analytische Konstruktion: <Keine Auswahl>
OverallHeight: 2.35 m; OverallWidth: 1.25 m
Pset_QuantityTakeOff - Reference: 1250 x 1500
Pset_WindowCommon - IsExternal: yes; Reference: 1250 x 1500
AVA - FENSTERLISTE - Nr: FE 11; Familie: FE 1 tlg - Fix; Typ: 1250 x 1500; Breite: 1.25 m; Höhe: 1.5 m; BRH: 0.79 m; UK ST: 2.29 m
BaseQuantities - Height: 1.5 m; Width: 1.25 m; Area: 1.875 m2
Andere - Familie: FE 1 tlg - Fix; AL Breite: 1.19 m; AL Höhe: 1.45 m; Familie und Typ: FE 1 tlg - Fix: 1250 x 1500; Host-ID: 2542921; Sturzhöhe: 2.29 m; Typ: 1250 x 1500; Typ-ID: 2558670
Modelleigenschaften - Rahmenbreite Links: 0.09 m; Rahmenbreite Oben: 0.09 m; Rahmenbreite Rechts: 0.09 m; Rahmenbreite Unten: 0.1 m
Abhängigkeiten - Ebene: Erdgeschoss; Fußbodenaufbau: 0 m; Wandaufbau Aussen: 0 m; Wandaufbau Innen: 0 m; Winkel Links: 90 deg; Winkel Rechts: 90 deg; Einbautiefe: 0.25 m; Schwelle/Brüstung: 0.79 m
Konstruktion - Leibungsschräge Oben: 0 m; Leibungsschräge Links: 0 m; Leibungsschräge Rechts: 0 m; AL_Abzug Links: 0.03 m; AL_Abzug Oben: 0.03 m; AL_Abzug Rechts: 0.03 m; AL_Abzug Unten: 0.02 m; Glasflaeche: 1.4017 m2; Leibungsschräge Unten: 0.01 m
Bemaßungen - Fläche: 2.29964 m2; Volumen: 0.169094 m3
ID-Daten - Kennzeichen: FE 11
Vollständige Legende - B_Winkel 1: 0 deg; B_Winkel 2: 0 deg; B_AL_Abzug Rechts: 0.03 m; B_AL Abzug Links: 0.03 m; B_Einbautiefe: 1.25 m; B_Griffhöhe: 0.655 m; B_Leibungsschräge Links: 1 m; B_Leibungsschräge Oben: 1 m; B_Leibungsschräge Rechts: 1 m; B_Leibungsschräge Unten: 0.99 m; B_Neigung Fensterbank: 2.29061 deg; B_Rahmenbreite Links: 0.09 m; B_Rahmenbreite Rechts: 0.09 m; Rahmenlichte Breite: 1.07 m; Rahmenlichte Höhe: 1.31 m; Wandstärke: 0.55 m
Phasen - Phase erstellt: Phase 01
Schichten - Fensterbank Aussen Metall: yes; Fensterbank Aussen Stein: no; Fensterbank Innen vorhanden: yes

# IfcWindow: FE 2 tlg - DrehKipp mit Stulp:2000 x 1400 (2)
In: Untergeschoss
Type - ParameterTakesPrecedence: no; Sizeable: no; Material: Glas - Isolierverglasung klar, Holz - generisch 140-100-70, Metall - Edelstahl gebürstet, Kunststoff - grau 70-70-70
Type - Andere - Kategorie: Fenster; Familienname: FE 2 tlg - DrehKipp mit Stulp; Vorgabewert für Einbauhöhe: 0.85 m
Type - Konstruktion - Wandabschluss: Nach Basisbauteil; Flügelbreite: 0.07 m; Glasstärke: 0.044 m; Griffhöhe = Flügelmitte: yes; Griffhöhe ab Flügelunterkante: 0.35 m; Rahmentiefe: 0.09 m; Stulpbreite: 0.12 m
Type - Daten - Ausführung Verglasung: Isolierverglasung 3-fach; Bauart Fenster: Einfachfenster; Form Fenster: rechteckig; Lage Bauteil: außen; Teiligkeit Fenster: 2-teilig senkrecht geteilt
Type - Bemaßungen - Randabstand Öffnungssymbol: 0 m; Breite: 2 m; Dicke: 0.09 m; Höhe: 1.4 m; Rohbaubreite: 2 m; Rohbauhöhe: 1.4 m
Type - ID-Daten - Beschreibung: 2-teilig; OmniClass-Nummer: 23.30.20.00; OmniClass-Titel: Windows; Typenkommentare: FE 2 tlg_DrehKipp mit Stulp; Typenmarkierung: 133; Typname: 2000 x 1400; URL: www.autodesk.de/BIM
Type - Vollständige Legende - Fensterbank Schattenfuge Höhe: 0.007 m
Type - Segmente und Formteile - Fensterbankdicke Innen: 0.025 m; Fensterbank Metall Dicke: 0.002 m; Fensterbank Metall Höhe hinten: 0.02 m; Fensterbank Metall Höhe Tropfnase: 0.04 m; Fensterbank Stein Dicke: 0.02 m; Fensterbank Stein Überstand: 0.02 m
Type - Analytische Eigenschaften - Thermische Eigenschaften definieren durch: Schemaplantypen; Analytische Konstruktion: <Keine Auswahl>
OverallHeight: 2.25 m; OverallWidth: 2 m
Pset_QuantityTakeOff - Reference: 2000 x 1400
Pset_WindowCommon - IsExternal: yes; Reference: 2000 x 1400
AVA - FENSTERLISTE - Familie: FE 2 tlg - DrehKipp mit Stulp; Typ: 2000 x 1400; Breite: 2 m; Höhe: 1.4 m
BaseQuantities - Height: 1.4 m; Width: 2 m; Area: 2.8 m2
Andere - AL Breite: 1.94 m; AL Höhe: 1.35 m; Familie: FE 2 tlg - DrehKipp mit Stulp; Familie und Typ: FE 2 tlg - DrehKipp mit Stulp: 2000 x 1400; Typ: 2000 x 1400; Typ-ID: 2552322
Modelleigenschaften - Rahmenbreite Drehflügelseite: 0.09 m; Rahmenbreite DrehKippflügel-Seite: 0.12 m; Rahmenbreite Oben: 0.09 m; Rahmenbreite Unten: 0.1 m
Abhängigkeiten - Ebene: Untergeschoss; Einbautiefe: 0.25 m; Fußbodenaufbau: 0 m; Wandaufbau Aussen: 0.02 m; Wandaufbau Innen: 0.05 m; Winkel Drehflügelseite: 90 deg; Winkel DrehKippflügel-Seite: 90 deg
Konstruktion - AL_Abzug Drehflügelseite: 0.03 m; AL_Abzug DrehKippflügel-Seite: 0.03 m; AL_Abzug Oben: 0.03 m; AL_Abzug Unten: 0.02 m; Glasflaeche: 1.8515 m2; Leibungsschräge Drehflügelseite: 0 m; Leibungsschräge DrehKippflügel-Seite: 0 m; Leibungsschräge Oben: 0 m; Leibungsschräge Unten: 0.01 m
Bemaßungen - DK_Flügelbreite: 0.5 m; Fläche: 3.32506 m2; Gleiche Flügelbreiten: yes; Volumen: 0.252425 m3
Grafiken - Symbol Drehflügel im Grundriss: yes; Winkel Öffnungssymbol: 30 deg
Vollständige Legende - B_AL_Abzug Rechts: 0.03 m; B_AL Abzug Links: 0.03 m; B_DK_Flügelbreite: 0.9525 m; B_Einbautiefe: 1.25 m; B_Griffhöhe: 0.605 m; B_Leibungsschräge Links: 1 m; B_Leibungsschräge Oben: 1 m; B_Leibungsschräge Rechts: 1 m; B_Leibungsschräge Unten: 0.99 m; B_Neigung Fensterbank: 2.1211 deg; B_Rahmenbreite Links: 0.12 m; B_Rahmenbreite Rechts: 0.09 m; B_Winkel 1: 0 deg; B_Winkel 2: 0 deg; Rahmenlichte Breite: 1.79 m; Rahmenlichte Höhe: 1.21 m; Stulpposition: 0.895 m; Wandstärke: 0.55 m
Phasen - Phase erstellt: Phase 01
Schichten - Fensterbank Aussen Metall: yes; Fensterbank Aussen Stein: no; Fensterbank Innen vorhanden: yes
Name (FE 2 tlg - DrehKipp mit Stulp:2000 x 1400:...) | Nr = Kennzeichen | BRH (m) = Schwelle/Brüstung (m) | UK ST (m) = Sturzhöhe (m) | Host-ID
2552327 | FE 3 | 0.85 | 2.25 | 2520373
2838212 | FE 68 | 0.745 | 2.145 | 2542197

# IfcWindow: FE 3 tlg - Kipp-Fix im Rahmen-Kipp:3300 x 1500, FE 3 tlg - Kipp-Fix im Rahmen-Kipp:3300 x 1500:2852565
In: Erdgeschoss
Type - ParameterTakesPrecedence: no; Sizeable: no; Material: Glas - Isolierverglasung klar, Holz - generisch 140-100-70, Metall - Edelstahl gebürstet, Kunststoff - grau 70-70-70
Type - Andere - Kategorie: Fenster; Familienname: FE 3 tlg - Kipp-Fix im Rahmen-Kipp; Vorgabewert für Einbauhöhe: 0.85 m
Type - Konstruktion - Wandabschluss: Nach Basisbauteil; Griffhöhe = Flügelmitte: yes; Flügelbreite: 0.07 m; Glasstärke: 0.044 m; Griffhöhe ab Flügelunterkante: 0.35 m; Pfostenbreite: 0.12 m; Rahmentiefe: 0.09 m
Type - Daten - Ausführung Verglasung: Isolierverglasung 3-fach; Bauart Fenster: Einfachfenster; Form Fenster: rechteckig; Lage Bauteil: außen; Teiligkeit Fenster: 3-teilig senkrecht geteilt
Type - Bemaßungen - Randabstand Öffnungssymbol: 0 m; Breite: 3.3 m; Dicke: 0.09 m; Höhe: 1.5 m; Rohbaubreite: 3.3 m; Rohbauhöhe: 1.5 m
Type - ID-Daten - Beschreibung: 3-teilig; OmniClass-Nummer: 23.30.20.00; OmniClass-Titel: Windows; Typenkommentare: FE 3 tlg_Kipp-Fix im Rahmen-Kipp; Typenmarkierung: 156; Typname: 3300 x 1500; URL: www.autodesk.de/BIM
Type - Vollständige Legende - Fensterbank Schattenfuge Höhe: 0.007 m
Type - Segmente und Formteile - Fensterbankdicke Innen: 0.025 m; Fensterbank Metall Dicke: 0.002 m; Fensterbank Metall Höhe hinten: 0.02 m; Fensterbank Metall Höhe Tropfnase: 0.04 m; Fensterbank Stein Dicke: 0.02 m; Fensterbank Stein Überstand: 0.02 m
Type - Analytische Eigenschaften - Thermische Eigenschaften definieren durch: Schemaplantypen; Analytische Konstruktion: <Keine Auswahl>
OverallHeight: 2.35 m; OverallWidth: 3.3 m
Pset_QuantityTakeOff - Reference: 3300 x 1500
Pset_WindowCommon - IsExternal: yes; Reference: 3300 x 1500
AVA - FENSTERLISTE - Nr: FE 71; Familie: FE 3 tlg - Kipp-Fix im Rahmen-Kipp; Typ: 3300 x 1500; Breite: 3.3 m; Höhe: 1.5 m; BRH: 0.85 m; UK ST: 2.35 m
BaseQuantities - Height: 1.5 m; Width: 3.3 m; Area: 4.95 m2
Andere - AL Breite: 3.24 m; AL Höhe: 1.45 m; Familie: FE 3 tlg - Kipp-Fix im Rahmen-Kipp; Familie und Typ: FE 3 tlg - Kipp-Fix im Rahmen-Kipp: 3300 x 1500; Host-ID: 2542556; Sturzhöhe: 2.35 m; Typ: 3300 x 1500; Typ-ID: 2852107
Modelleigenschaften - Rahmenbreite Links: 0.09 m; Rahmenbreite Oben: 0.09 m; Rahmenbreite Rechts: 0.09 m; Rahmenbreite Unten: 0.1 m
Abhängigkeiten - Ebene: Erdgeschoss; Fußbodenaufbau: 0 m; Wandaufbau Innen: 0 m; Winkel Links: 90 deg; Winkel Rechts: 90 deg; Einbautiefe: 0.25 m; Schwelle/Brüstung: 0.85 m; Wandaufbau Aussen: 0.02 m
Konstruktion - Leibungsschräge Oben: 0 m; Leibungsschräge Links: 0 m; Leibungsschräge Rechts: 0 m; AL_Abzug Links: 0.03 m; AL_Abzug Oben: 0.03 m; AL_Abzug Rechts: 0.03 m; AL_Abzug Unten: 0.02 m; Glasflaeche: 3.375 m2; Leibungsschräge Unten: 0.01 m
Bemaßungen - Feldbreite Links: 0.3 m; Feldbreite Rechts: 0.3 m; Fläche: 5.69136 m2; Gleiche Feldbreiten: yes; Volumen: 0.4461 m3
ID-Daten - Kennzeichen: FE 71
Vollständige Legende - B_Winkel 1: 0 deg; B_Winkel 2: 0 deg; B_AL_Abzug Rechts: 0.03 m; B_AL Abzug Links: 0.03 m; B_Einbautiefe: 1.25 m; B_Feldbreite Links: 0.96 m; B_Feldbreite Mitte: 0.96 m; B_Feldbreite Rechts: 0.96 m; B_Griffhöhe: 0.655 m; B_Leibungsschräge Links: 1 m; B_Leibungsschräge Oben: 1 m; B_Leibungsschräge Rechts: 1 m; B_Leibungsschräge Unten: 0.99 m; B_Neigung Fensterbank: 2.1211 deg; B_Rahmenbreite Links: 0.09 m; B_Rahmenbreite Rechts: 0.09 m; Kämpferposition 1: 1.02 m; Kämpferposition 2: 1.02 m; Rahmenlichte Breite: 3.12 m; Rahmenlichte Höhe: 1.31 m; Wandstärke: 0.55 m
Phasen - Phase erstellt: Phase 01
Schichten - Fensterbank Aussen Metall: yes; Fensterbank Aussen Stein: no; Fensterbank Innen vorhanden: yes

# IfcWindow: FE Dachfenster:1100 x 1200, FE Dachfenster:1100 x 1200:2608827
In: Untergeschoss
Type - ParameterTakesPrecedence: no; Sizeable: no; Material: Glas - Isolierverglasung klar, Metall - Edelstahl satiniert, Dämmung - ausgeschäumt, Holz - generisch 140-100-70, Lack - grau 80-80-80
Type - Andere - Kategorie: Fenster; Familienname: FE Dachfenster
Type - Abhängigkeiten - Vorgabe-Ansicht: 13.1234 m
Type - Daten - Ausführung Verglasung: Isolierverglasung 2-fach; Bauart Fenster: Dachfenster; Feuerwiderstandsklasse: Keine Anforderung; Form Fenster: rechteckig; Lage Bauteil: außen; Teiligkeit Fenster: einteilig
Type - Bemaßungen - Winkel Oben: 89 deg; Winkel Unten: 89 deg; Ausschnitt Höhe Oben: 0.12 m; Ausschnitt Höhe Unten: 0.12 m; Breite: 1.1 m; Höhe: 0.95 m; Tiefe Ausschnitt: 0.4 m
Type - ID-Daten - Beschreibung: Dachfenster; OmniClass-Nummer: 23.30.30.00; OmniClass-Titel: Skylights; Typenmarkierung: 142; Typname: 1100 x 1200; URL: www.autodesk.com/BIM
Type - Materialien und Oberflächen - Dämmung: Dämmung - ausgeschäumt; Eindeckrahmen: Lack - grau 80-80-80; Fensterolive: Metall - Edelstahl satiniert; Glas: Glas - Isolierverglasung klar; Holz: Holz - generisch 140-100-70
Type - Analytische Eigenschaften - Thermische Eigenschaften definieren durch: Schemaplantypen; Analytische Konstruktion: <Keine Auswahl>
Type - Pset_WindowCommon - FireRating: Keine Anforderung
OverallHeight: 1.05202 m; OverallWidth: 1.18153 m
Pset_QuantityTakeOff - Reference: 1100 x 1200
Pset_WindowCommon - IsExternal: yes; Reference: 1100 x 1200
AVA - FENSTERLISTE - Nr: FE 27; Familie: FE Dachfenster; Typ: 1100 x 1200; Breite: 1.1 m; Höhe: 0.95 m
BaseQuantities - Height: 0.95 m; Width: 1.1 m; Area: 1.045 m2
Andere - Familie: FE Dachfenster; Familie und Typ: FE Dachfenster: 1100 x 1200; Typ: 1100 x 1200; Typ-ID: 2608822
Abhängigkeiten - Ebene: Untergeschoss; Bauteillistenebene: Untergeschoss; Versatz von Host: 0 m; Arbeitsebene: Basisdach : Ziegeldach 340
Bemaßungen - Fläche: 1.4971 m2; Volumen: 0.17574 m3
ID-Daten - Kennzeichen: FE 27
Phasen - Phase erstellt: Phase 01

# IfcWindow: FE Dachfenster:800 x 1050, FE Dachfenster:800 x 1050:2608571
In: Untergeschoss
Type - ParameterTakesPrecedence: no; Sizeable: no; Material: Glas - Isolierverglasung klar, Metall - Edelstahl satiniert, Dämmung - ausgeschäumt, Holz - generisch 140-100-70, Lack - grau 80-80-80
Type - Andere - Kategorie: Fenster; Familienname: FE Dachfenster
Type - Abhängigkeiten - Vorgabe-Ansicht: 13.1234 m
Type - Daten - Ausführung Verglasung: Isolierverglasung 2-fach; Bauart Fenster: Dachfenster; Feuerwiderstandsklasse: Keine Anforderung; Form Fenster: rechteckig; Lage Bauteil: außen; Teiligkeit Fenster: einteilig
Type - Bemaßungen - Ausschnitt Höhe Oben: 0.12 m; Ausschnitt Höhe Unten: 0.12 m; Breite: 0.8 m; Höhe: 1.05 m; Tiefe Ausschnitt: 1 m; Winkel Oben: 89 deg; Winkel Unten: 89 deg
Type - ID-Daten - Beschreibung: Dachfenster; OmniClass-Nummer: 23.30.30.00; OmniClass-Titel: Skylights; Typenmarkierung: 141; Typname: 800 x 1050; URL: www.autodesk.com/BIM
Type - Materialien und Oberflächen - Dämmung: Dämmung - ausgeschäumt; Eindeckrahmen: Lack - grau 80-80-80; Fensterolive: Metall - Edelstahl satiniert; Glas: Glas - Isolierverglasung klar; Holz: Holz - generisch 140-100-70
Type - Analytische Eigenschaften - Thermische Eigenschaften definieren durch: Schemaplantypen; Analytische Konstruktion: <Keine Auswahl>
Type - Pset_WindowCommon - FireRating: Keine Anforderung
OverallHeight: 1.15202 m; OverallWidth: 0.881533 m
Pset_QuantityTakeOff - Reference: 800 x 1050
Pset_WindowCommon - IsExternal: yes; Reference: 800 x 1050
AVA - FENSTERLISTE - Nr: FE 26; Familie: FE Dachfenster; Typ: 800 x 1050; Breite: 0.8 m; Höhe: 1.05 m
BaseQuantities - Height: 1.05 m; Width: 0.8 m; Area: 0.84 m2
Andere - Familie: FE Dachfenster; Familie und Typ: FE Dachfenster: 800 x 1050; Typ: 800 x 1050; Typ-ID: 2608470
Abhängigkeiten - Ebene: Untergeschoss; Arbeitsebene: Basisdach : Ziegeldach 340; Bauteillistenebene: Untergeschoss; Versatz von Host: 0 m
Bemaßungen - Fläche: 1.2501 m2; Volumen: 0.14319 m3
ID-Daten - Kennzeichen: FE 26
Phasen - Phase erstellt: Phase 01

# IfcWindow: FE Schräg 1 tlg - Fix:700 x 1050 (3)
In: 1. Obergeschoss
Type - ParameterTakesPrecedence: no; Sizeable: no; Material: Holz - generisch 140-100-70, Kunststoff - grau 70-70-70, Glas - Isolierverglasung klar
Type - Andere - Kategorie: Fenster; Familienname: FE Schräg 1 tlg - Fix; Vorgabewert für Einbauhöhe: 0.85 m
Type - Konstruktion - Wandabschluss: Nach Basisbauteil; Glasstärke: 0.044 m; Rahmentiefe: 0.09 m
Type - Daten - Ausführung Verglasung: Isolierverglasung 3-fach; Bauart Fenster: Einfachfenster; Form Fenster: schräg; Lage Bauteil: außen; Teiligkeit Fenster: einteilig
Type - Bemaßungen - Randabstand Öffnungssymbol: 0 m; Schräge: 28 deg; Breite: 1.05 m; Dicke: 0.09 m; Höhe: 0.7 m; Höhe 2: 1.25829 m; Höhe Dreieck: 0.558295 m; Rohbaubreite: 1.05 m; Rohbauhöhe: 0.7 m
Type - ID-Daten - Beschreibung: Sonderformen; OmniClass-Nummer: 23.30.20.00; OmniClass-Titel: Windows; Typenkommentare: FE Schräg 1 tlg_Fix; Typenmarkierung: 147; Typname: 700 x 1050; URL: www.autodesk.de/BIM
Type - Vollständige Legende - Fensterbank Schattenfuge Höhe: 0.007 m
Type - Segmente und Formteile - Fensterbankdicke Innen: 0.025 m; Fensterbank Metall Dicke: 0.002 m; Fensterbank Metall Höhe hinten: 0.02 m; Fensterbank Metall Höhe Tropfnase: 0.04 m; Fensterbank Stein Dicke: 0.02 m; Fensterbank Stein Überstand: 0.02 m
Type - Analytische Eigenschaften - Thermische Eigenschaften definieren durch: Schemaplantypen; Analytische Konstruktion: <Keine Auswahl>
OverallHeight: 2.25872 m; OverallWidth: 1.1558 m
Pset_QuantityTakeOff - Reference: 700 x 1050
Pset_WindowCommon - IsExternal: yes; Reference: 700 x 1050
AVA - FENSTERLISTE - Familie: FE Schräg 1 tlg - Fix; Typ: 700 x 1050; Breite: 1.05 m; Höhe: 0.7 m; BRH: 0.4525 m; UK ST: 1.1525 m
BaseQuantities - Height: 0.7 m; Width: 1.05 m; Area: 0.735 m2
Andere - Familie: FE Schräg 1 tlg - Fix; AL Höhe: 0.65 m; Familie und Typ: FE Schräg 1 tlg - Fix: 700 x 1050; Sturzhöhe: 1.1525 m; Typ: 700 x 1050; Typ-ID: 2656084
Modelleigenschaften - Rahmenbreite Links: 0.09 m; Rahmenbreite Oben: 0.09 m; Rahmenbreite Unten: 0.1 m
Abhängigkeiten - Fußbodenaufbau: 0 m; Wandaufbau Innen: 0 m; Ebene: Traufe; Einbautiefe: 0.25 m; Schwelle/Brüstung: 0.4525 m; Wandaufbau Aussen: 0.02 m
Konstruktion - Leibungsschräge Oben: 0 m; AL_Abzug Rechts: 0 m; Leibungsschräge Links: 0 m; Leibungsschräge Rechts: 0 m; AL_Abzug Oben: 0.03 m; AL_Abzug Unten: 0.02 m; Leibungsschräge Unten: 0.01 m
Bemaßungen - Fläche: 1.32081 m2; Volumen: 0.0927297 m3
Vollständige Legende - B_Einbautiefe: 1.25 m; B_Leibungsschräge Links: 1 m; B_Leibungsschräge Rechts: 1 m; B_Leibungsschräge Unten: 0.99 m; B_Neigung Fensterbank: 2.1211 deg; Glashöhe 1: 0.545923 m; Rahmenlichte Höhe: 0.51 m; Wandstärke: 0.55 m
Phasen - Phase erstellt: Phase 01
Schichten - Fensterbank Aussen Metall: yes; Fensterbank Aussen Stein: no; Fensterbank Innen vorhanden: yes
Name (FE Schräg 1 tlg - Fix:700 x 1050:...) | Nr = Kennzeichen | AL Breite (m) | Host-ID | Rahmenbreite Rechts (m) | AL_Abzug Links (m) | Glasflaeche (m2) | B_AL_Abzug Oben (m) | Glashöhe 2 (m) | Rahmenlichte Breite (m)
2660234 | FE 38 | 1.02 | 2547048 | 0.2 | 0.03 | 0.568459 | -0.0180258 | 0.950022 | 0.76
2887814 | FE 73 | 1.05 | 2547048 | 0.09 | 0 | 0.676178 | -0.0339771 | 1.00851 | 0.87
2889053 | FE 75 | 1.05 | 2546884 | 0.09 | 0 | 0.676178 | -0.0339771 | 1.00851 | 0.87

# IfcWindow: FE Schräg 1 tlg - Fix:920 x 1258 (4)
In: 1. Obergeschoss
Type - ParameterTakesPrecedence: no; Sizeable: no; Material: Holz - generisch 140-100-70, Kunststoff - grau 70-70-70, Glas - Isolierverglasung klar
Type - Andere - Kategorie: Fenster; Familienname: FE Schräg 1 tlg - Fix; Vorgabewert für Einbauhöhe: 0.85 m
Type - Konstruktion - Wandabschluss: Nach Basisbauteil; Glasstärke: 0.044 m; Rahmentiefe: 0.09 m
Type - Daten - Ausführung Verglasung: Isolierverglasung 3-fach; Bauart Fenster: Einfachfenster; Form Fenster: schräg; Lage Bauteil: außen; Teiligkeit Fenster: einteilig
Type - Bemaßungen - Randabstand Öffnungssymbol: 0 m; Breite: 0.92 m; Dicke: 0.09 m; Höhe: 1.2583 m; Höhe 2: 1.74747 m; Höhe Dreieck: 0.489173 m; Rohbaubreite: 0.92 m; Rohbauhöhe: 1.2583 m; Schräge: 28 deg
Type - ID-Daten - Beschreibung: Sonderformen; OmniClass-Nummer: 23.30.20.00; OmniClass-Titel: Windows; Typenkommentare: FE Schräg 1 tlg_Fix; Typenmarkierung: 146; Typname: 920 x 1258; URL: www.autodesk.de/BIM
Type - Vollständige Legende - Fensterbank Schattenfuge Höhe: 0.007 m
Type - Segmente und Formteile - Fensterbankdicke Innen: 0.025 m; Fensterbank Metall Dicke: 0.002 m; Fensterbank Metall Höhe hinten: 0.02 m; Fensterbank Metall Höhe Tropfnase: 0.04 m; Fensterbank Stein Dicke: 0.02 m; Fensterbank Stein Überstand: 0.02 m
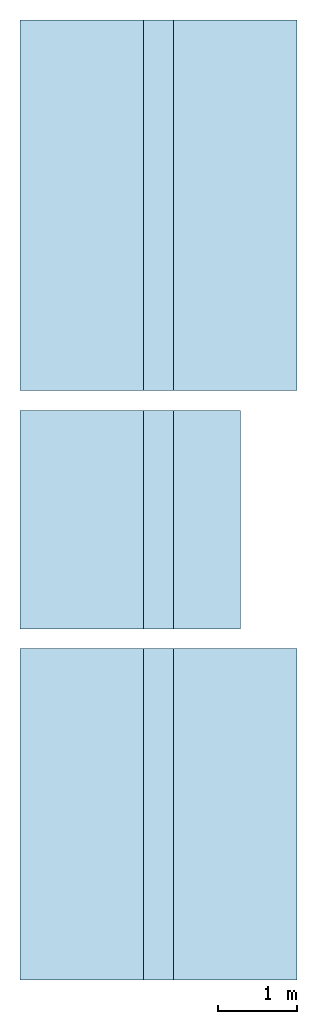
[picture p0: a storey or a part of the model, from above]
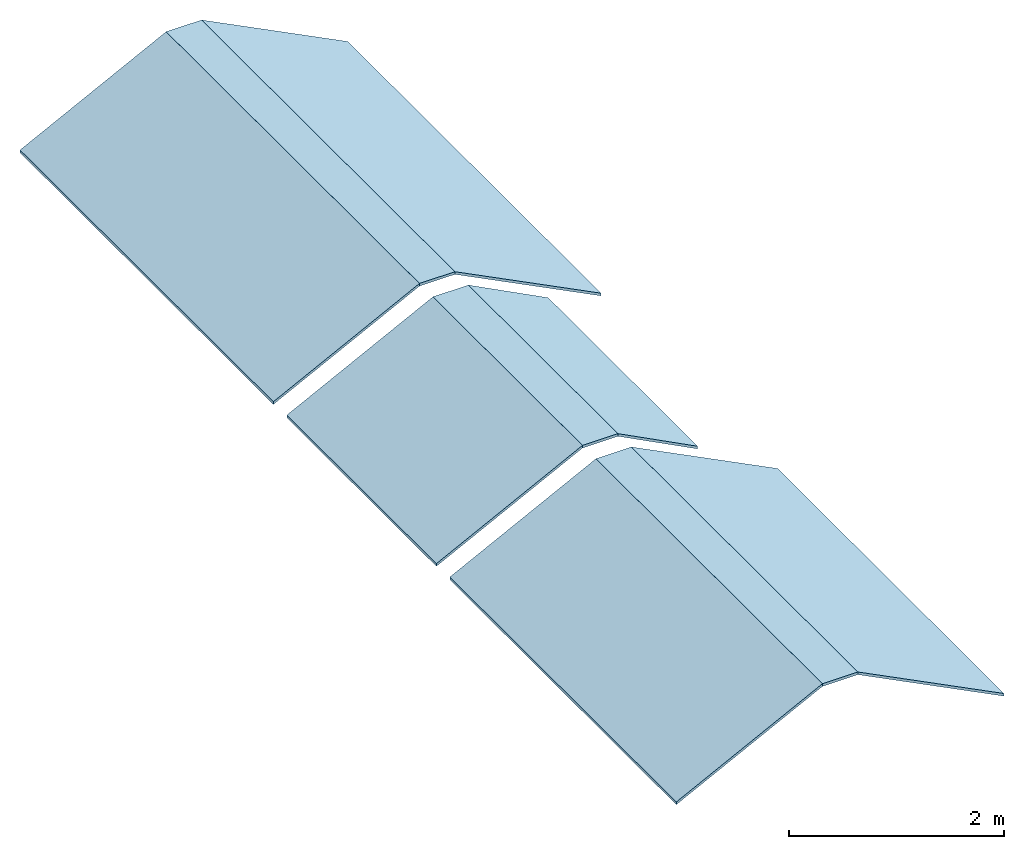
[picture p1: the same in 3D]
Properties of the parts of a building model (IFC2X3), part 5 of 5

# IfcWindow: FE Schräg 1 tlg - Fix:920 x 1258 (4)
Type - Analytische Eigenschaften - Thermische Eigenschaften definieren durch: Schemaplantypen; Analytische Konstruktion: <Keine Auswahl>
OverallHeight: 2.59747 m; OverallWidth: 1.0258 m
Pset_QuantityTakeOff - Reference: 920 x 1258
Pset_WindowCommon - IsExternal: yes; Reference: 920 x 1258
AVA - FENSTERLISTE - Familie: FE Schräg 1 tlg - Fix; Typ: 920 x 1258; Breite: 0.92 m; Höhe: 1.2583 m; BRH: 0.4525 m; UK ST: 1.7108 m
BaseQuantities - Height: 1.2583 m; Width: 0.92 m; Area: 1.15764 m2
Andere - AL Breite: 0.92 m; AL Höhe: 1.2083 m; Familie: FE Schräg 1 tlg - Fix; Familie und Typ: FE Schräg 1 tlg - Fix: 920 x 1258; Sturzhöhe: 1.7108 m; Typ: 920 x 1258; Typ-ID: 2654323
Modelleigenschaften - Rahmenbreite Links: 0.09 m; Rahmenbreite Oben: 0.09 m; Rahmenbreite Rechts: 0.095 m; Rahmenbreite Unten: 0.1 m
Abhängigkeiten - Fußbodenaufbau: 0 m; Wandaufbau Innen: 0 m; Ebene: Traufe; Einbautiefe: 0.25 m; Schwelle/Brüstung: 0.4525 m; Wandaufbau Aussen: 0.02 m
Konstruktion - Leibungsschräge Oben: 0 m; AL_Abzug Rechts: 0 m; Leibungsschräge Links: 0 m; Leibungsschräge Rechts: 0 m; AL_Abzug Links: 0 m; AL_Abzug Oben: 0.03 m; AL_Abzug Unten: 0.02 m; Glasflaeche: 0.955225 m2; Leibungsschräge Unten: 0.01 m
Bemaßungen - Fläche: 1.72643 m2; Volumen: 0.12467 m3
Vollständige Legende - B_AL_Abzug Oben: -0.0339771 m; B_Einbautiefe: 1.25 m; B_Leibungsschräge Links: 1 m; B_Leibungsschräge Rechts: 1 m; B_Leibungsschräge Unten: 0.99 m; B_Neigung Fensterbank: 2.1211 deg; Glashöhe 1: 1.10422 m; Glashöhe 2: 1.49503 m; Rahmenlichte Breite: 0.735 m; Rahmenlichte Höhe: 1.0683 m; Wandstärke: 0.55 m
Phasen - Phase erstellt: Phase 01
Schichten - Fensterbank Aussen Metall: yes; Fensterbank Aussen Stein: no; Fensterbank Innen vorhanden: yes
Name (FE Schräg 1 tlg - Fix:920 x 1258:...) | Nr = Kennzeichen | Host-ID
2656041 | FE 32 | 2546884
2659038 | FE 37 | 2546884
2660235 | FE 39 | 2547048
2660238 | FE 42 | 2547048

# IfcWindow: FE Schräg 1 tlg - Fix:950 x 1747 (4)
In: 1. Obergeschoss
Type - ParameterTakesPrecedence: no; Sizeable: no; Material: Holz - generisch 140-100-70, Kunststoff - grau 70-70-70, Glas - Isolierverglasung klar
Type - Andere - Kategorie: Fenster; Familienname: FE Schräg 1 tlg - Fix; Vorgabewert für Einbauhöhe: 0.85 m
Type - Konstruktion - Wandabschluss: Nach Basisbauteil; Glasstärke: 0.044 m; Rahmentiefe: 0.09 m
Type - Daten - Ausführung Verglasung: Isolierverglasung 3-fach; Bauart Fenster: Einfachfenster; Form Fenster: schräg; Lage Bauteil: außen; Teiligkeit Fenster: einteilig
Type - Bemaßungen - Randabstand Öffnungssymbol: 0 m; Schräge: 28 deg; Breite: 0.95 m; Dicke: 0.09 m; Höhe: 1.7475 m; Höhe 2: 2.25262 m; Höhe Dreieck: 0.505124 m; Rohbaubreite: 0.95 m; Rohbauhöhe: 1.7475 m
Type - ID-Daten - Beschreibung: Sonderformen; OmniClass-Nummer: 23.30.20.00; OmniClass-Titel: Windows; Typenkommentare: FE Schräg 1 tlg_Fix; Typenmarkierung: 148; Typname: 950 x 1747; URL: www.autodesk.de/BIM
Type - Vollständige Legende - Fensterbank Schattenfuge Höhe: 0.007 m
Type - Segmente und Formteile - Fensterbankdicke Innen: 0.025 m; Fensterbank Metall Dicke: 0.002 m; Fensterbank Metall Höhe hinten: 0.02 m; Fensterbank Metall Höhe Tropfnase: 0.04 m; Fensterbank Stein Dicke: 0.02 m; Fensterbank Stein Überstand: 0.02 m
Type - Analytische Eigenschaften - Thermische Eigenschaften definieren durch: Schemaplantypen; Analytische Konstruktion: <Keine Auswahl>
OverallHeight: 3.10262 m; OverallWidth: 1.0558 m
Pset_QuantityTakeOff - Reference: 950 x 1747
Pset_WindowCommon - IsExternal: yes; Reference: 950 x 1747
AVA - FENSTERLISTE - Familie: FE Schräg 1 tlg - Fix; Typ: 950 x 1747; Breite: 0.95 m; Höhe: 1.7475 m
BaseQuantities - Height: 1.7475 m; Width: 0.95 m; Area: 1.66012 m2
Andere - Familie: FE Schräg 1 tlg - Fix; AL Breite: 0.95 m; AL Höhe: 1.6975 m; Familie und Typ: FE Schräg 1 tlg - Fix: 950 x 1747; Typ: 950 x 1747; Typ-ID: 2657442
Modelleigenschaften - Rahmenbreite Links: 0.09 m; Rahmenbreite Oben: 0.09 m; Rahmenbreite Unten: 0.1 m
Abhängigkeiten - Fußbodenaufbau: 0 m; Wandaufbau Innen: 0 m; Ebene: Traufe; Einbautiefe: 0.25 m; Wandaufbau Aussen: 0.02 m
Konstruktion - Leibungsschräge Oben: 0 m; AL_Abzug Rechts: 0 m; Leibungsschräge Links: 0 m; Leibungsschräge Rechts: 0 m; AL_Abzug Links: 0 m; AL_Abzug Oben: 0.03 m; AL_Abzug Unten: 0.02 m; Leibungsschräge Unten: 0.01 m
Bemaßungen - Fläche: 2.31572 m2; Volumen: 0.171283 m3
Vollständige Legende - B_AL_Abzug Oben: -0.0339771 m; B_Einbautiefe: 1.25 m; B_Leibungsschräge Links: 1 m; B_Leibungsschräge Rechts: 1 m; B_Leibungsschräge Unten: 0.99 m; B_Neigung Fensterbank: 2.1211 deg; Glashöhe 1: 1.59342 m; Rahmenlichte Höhe: 1.5575 m; Wandstärke: 0.55 m
Phasen - Phase erstellt: Phase 01
Schichten - Fensterbank Aussen Metall: yes; Fensterbank Aussen Stein: no; Fensterbank Innen vorhanden: yes
Name (FE Schräg 1 tlg - Fix:950 x 1747:...) | Nr = Kennzeichen | BRH (m) = Schwelle/Brüstung (m) | UK ST (m) = Sturzhöhe (m) | Host-ID | Rahmenbreite Rechts (m) | Glasflaeche (m2) | Glashöhe 2 (m) | Rahmenlichte Breite (m)
2658140 | FE 34 | 0.452473 | 2.19997 | 2546884 | 0.195 | 1.17719 | 1.94701 | 0.665
2660237 | FE 41 | 0.452473 | 2.19997 | 2547048 | 0.195 | 1.17719 | 1.94701 | 0.665
2886102 | FE 72 | 0.452473 | 2.19997 | 2546884 | 0.15 | 1.26535 | 1.97094 | 0.71
2888334 | FE 74 | 0.4525 | 2.2 | 2547048 | 0.195 | 1.17719 | 1.94701 | 0.665

# IfcWindow: FE TÜR 1 tlg - DrehKipp:940 x 2200 (3)
In: Erdgeschoss
Type - ParameterTakesPrecedence: no; Sizeable: no; Material: Glas - Isolierverglasung klar, Metall - Edelstahl gebürstet, Kunststoff - grau 70-70-70
Type - Andere - Kategorie: Fenster; Familienname: FE TÜR 1 tlg - DrehKipp; Vorgabewert für Einbauhöhe: 0 m
Type - Konstruktion - Wandabschluss: Nach Basisbauteil; Griffhöhe = Flügelmitte: yes; Flügelbreite: 0.07 m; Glasstärke: 0.044 m; Griffhöhe ab Flügelunterkante: 0.35 m; Rahmentiefe: 0.09 m
Type - Daten - Ausführung Verglasung: Isolierverglasung 3-fach; Bauart Fenster: Fenstertür; Form Fenster: rechteckig; Lage Bauteil: außen; Teiligkeit Fenster: einteilig
Type - Bemaßungen - Höhe ab FBOK berechnen: yes; Randabstand Öffnungssymbol: 0 m; Breite: 0.94 m; Dicke: 0.09 m; Höhe ab FBOK: 2.2 m; Rohbaubreite: 0.94 m
Type - ID-Daten - Beschreibung: 1-teilig; OmniClass-Nummer: 23.30.20.00; OmniClass-Titel: Windows; Typenkommentare: FE TUER 1 tlg_DrehKipp; Typenmarkierung: 123; Typname: 940 x 2200; URL: www.autodesk.de/BIM
Type - Vollständige Legende - Fensterbankdicke Innen: 0 m; Fensterbank Schattenfuge Höhe: 0 m
Type - Segmente und Formteile - Fensterbank Metall Dicke: 0.002 m; Fensterbank Metall Höhe hinten: 0.02 m; Fensterbank Metall Höhe Tropfnase: 0.04 m; Fensterbank Stein Dicke: 0.02 m; Fensterbank Stein Überstand: 0.02 m
Type - Analytische Eigenschaften - Thermische Eigenschaften definieren durch: Schemaplantypen; Analytische Konstruktion: <Keine Auswahl>
OverallHeight: 2.4 m; OverallWidth: 0.94 m
Pset_QuantityTakeOff - Reference: 940 x 2200
Pset_WindowCommon - IsExternal: yes; Reference: 940 x 2200
AVA - FENSTERLISTE - Familie: FE TÜR 1 tlg - DrehKipp; Typ: 940 x 2200; Breite: 0.94 m; Höhe: 2.2 m; BRH: 0 m; UK ST: 2.2 m
BaseQuantities - Height: 2.2 m; Width: 0.94 m; Area: 2.068 m2
Andere - AL Höhe: 2.17 m; Familie: FE TÜR 1 tlg - DrehKipp; Familie und Typ: FE TÜR 1 tlg - DrehKipp: 940 x 2200; Sturzhöhe: 2.2 m; Typ: 940 x 2200; Typ-ID: 2180752
Modelleigenschaften - Rahmenbreite Bandseite: 0.09 m; Rahmenbreite Drückerseite: 0.09 m; Rahmenbreite Oben: 0.09 m; Rahmenbreite Unten: 0.1 m
Abhängigkeiten - Ebene: Erdgeschoss; Schwelle/Brüstung: 0 m; Wandaufbau Innen: 0 m; Winkel Bandseite: 90 deg; Winkel Griffseite: 90 deg; Einbautiefe: 0.25 m; Fußbodenaufbau: 0.2 m; Wandaufbau Aussen: 0.16 m
Konstruktion - Leibungsschräge Oben: 0 m; Leibungsschräge Bandseite: 0 m; Leibungsschräge Drückerseite: 0 m; AL_Abzug Oben: 0.03 m; AL_Abzug Unten: 0.2 m; Glasflaeche: 1.365 m2
Bemaßungen - Fläche: 2.74713 m2; Höhe: 2.2 m; Rohbauhöhe: 2.4 m; Volumen: 0.203409 m3; Wandstärke: 0.55 m
Grafiken - Symbol Drehflügel im Grundriss: yes; Winkel Öffnungssymbol: 90 deg
Vollständige Legende - B_Winkel 1: 0 deg; B_Winkel 2: 0 deg; B_Einbautiefe: 1.25 m; B_Griffhöhe: 1.005 m; B_Leibungsschräge Links: 1 m; B_Leibungsschräge Oben: 1 m; B_Leibungsschräge Rechts: 1 m; B_Rahmenbreite Links: 0.09 m; B_Rahmenbreite Rechts: 0.09 m; Rahmenlichte Breite: 0.76 m; Rahmenlichte Höhe: 2.01 m
Phasen - Phase erstellt: Phase 01
Schichten - Fensterbank Aussen Metall: yes; Fensterbank Aussen Stein: no
Name (FE TÜR 1 tlg - DrehKipp:940 x 2200:...) | Nr = Kennzeichen | Host-ID | AL Breite (m) | AL_Abzug Bandseite (m) = B_AL Abzug Links (m) | AL_Abzug Drückerseite (m) = B_AL_Abzug Rechts (m) | Leibungsschräge Unten (m) | B_Leibungsschräge Unten (m) | B_Neigung Fensterbank (deg)
2664455 | FE 46 | 2542412 | 0.91 | 0.03 | 0 | 0 | 1 | 0
2679635 | FE 47 | 2542412 | 0.91 | 0 | 0.03 | 0 | 1 | 0
2679811 | FE 48 | 2542471 | 0.88 | 0.03 | 0.03 | 0.01 | 0.99 | 1.39718

# IfcWindow: FE TÜR 2 tlg - DrehKipp mit Stulp:1900 x 1980, FE TÜR 2 tlg - DrehKipp mit Stulp:1900 x 1980:2681310
In: Untergeschoss
Type - ParameterTakesPrecedence: no; Sizeable: no; Material: Glas - Isolierverglasung klar, Metall - Edelstahl gebürstet, Kunststoff - grau 70-70-70
Type - Andere - Kategorie: Fenster; Vorgabewert für Einbauhöhe: 0 m; Familienname: FE TÜR 2 tlg - DrehKipp mit Stulp
Type - Konstruktion - Wandabschluss: Nach Basisbauteil; Griffhöhe = Flügelmitte: yes; Flügelbreite: 0.07 m; Glasstärke: 0.044 m; Griffhöhe ab Flügelunterkante: 0.35 m; Rahmentiefe: 0.09 m; Stulpbreite: 0.12 m
Type - Daten - Ausführung Verglasung: Isolierverglasung 3-fach; Bauart Fenster: Fenstertür; Form Fenster: rechteckig; Lage Bauteil: außen; Teiligkeit Fenster: 2-teilig senkrecht geteilt
Type - Bemaßungen - Höhe ab FBOK berechnen: yes; Randabstand Öffnungssymbol: 0 m; Breite: 1.98 m; Dicke: 0.09 m; Höhe ab FBOK: 2 m; Rohbaubreite: 1.98 m
Type - ID-Daten - Beschreibung: 2-teilig; OmniClass-Nummer: 23.30.20.00; OmniClass-Titel: Windows; Typenkommentare: FE TUER 2 tlg_DrehKipp mit Stulp; Typenmarkierung: 132; Typname: 1900 x 1980; URL: www.autodesk.de/BIM
Type - Vollständige Legende - Fensterbankdicke Innen: 0 m; Fensterbank Schattenfuge Höhe: 0 m; Rahmenfräsung: 0 m
Type - Segmente und Formteile - Fensterbank Metall Dicke: 0 m; Fensterbank Metall Höhe hinten: 0 m; Fensterbank Metall Höhe Tropfnase: 0 m; Fensterbank Stein Dicke: 0 m; Fensterbank Stein Überstand: 0 m
Type - Analytische Eigenschaften - Thermische Eigenschaften definieren durch: Schemaplantypen; Analytische Konstruktion: <Keine Auswahl>
OverallHeight: 2.2 m; OverallWidth: 1.98 m
Pset_QuantityTakeOff - Reference: 1900 x 1980
Pset_WindowCommon - IsExternal: yes; Reference: 1900 x 1980
AVA - FENSTERLISTE - BRH: 0 m; Nr: FE 49; Familie: FE TÜR 2 tlg - DrehKipp mit Stulp; Typ: 1900 x 1980; Breite: 1.98 m; Höhe: 2 m; UK ST: 2 m
BaseQuantities - Height: 2 m; Width: 1.98 m; Area: 3.96 m2
Andere - AL Breite: 1.92 m; AL Höhe: 1.97 m; Familie: FE TÜR 2 tlg - DrehKipp mit Stulp; Familie und Typ: FE TÜR 2 tlg - DrehKipp mit Stulp: 1900 x 1980; Host-ID: 2542197; Sturzhöhe: 2 m; Typ: 1900 x 1980; Typ-ID: 2552084
Modelleigenschaften - Rahmenbreite Drehflügelseite: 0.09 m; Rahmenbreite DrehKippflügel-Seite: 0.09 m; Rahmenbreite Oben: 0.09 m; Rahmenbreite Unten: 0.1 m
Abhängigkeiten - Ebene: Untergeschoss; Schwelle/Brüstung: 0 m; Winkel Drehflügelseite: 90 deg; Winkel DrehKippflügel-Seite: 90 deg; Wandaufbau Innen: 0 m; Einbautiefe: 0.25 m; Fußbodenaufbau: 0.2 m; Wandaufbau Aussen: 0.16 m
Konstruktion - Leibungsschräge Drehflügelseite: 0 m; Leibungsschräge DrehKippflügel-Seite: 0 m; Leibungsschräge Oben: 0 m; AL_Abzug Drehflügelseite: 0.03 m; AL_Abzug DrehKippflügel-Seite: 0.03 m; AL_Abzug Oben: 0.03 m; AL_Abzug Unten: 0.2 m; Glasflaeche: 2.835 m2; Leibungsschräge Unten: 0.01 m
Bemaßungen - Gleiche Flügelbreiten: yes; DK_Flügelbreite: 0.5 m; Fläche: 4.98867 m2; Höhe: 2 m; Rohbauhöhe: 2.2 m; Volumen: 0.392537 m3
Grafiken - Symbol Drehflügel im Grundriss: yes; Winkel Öffnungssymbol: 90 deg
ID-Daten - Kennzeichen: FE 49
Vollständige Legende - B_Winkel 1: 0 deg; B_Winkel 2: 0 deg; B_AL_Abzug Rechts: 0.03 m; B_AL Abzug Links: 0.03 m; B_DK_Flügelbreite: 0.9575 m; B_Einbautiefe: 1.25 m; B_Griffhöhe: 0.905 m; B_Leibungsschräge Links: 1 m; B_Leibungsschräge Oben: 1 m; B_Leibungsschräge Rechts: 1 m; B_Leibungsschräge Unten: 0.99 m; B_Neigung Fensterbank: 1.39718 deg; B_Rahmenbreite Links: 0.09 m; B_Rahmenbreite Rechts: 0.09 m; Rahmenlichte Breite: 1.8 m; Rahmenlichte Höhe: 1.81 m; Stulpposition: 0.9 m; Wandstärke: 0.55 m
Phasen - Phase erstellt: Phase 01
Schichten - Fensterbank Aussen Metall: yes; Fensterbank Aussen Stein: no
